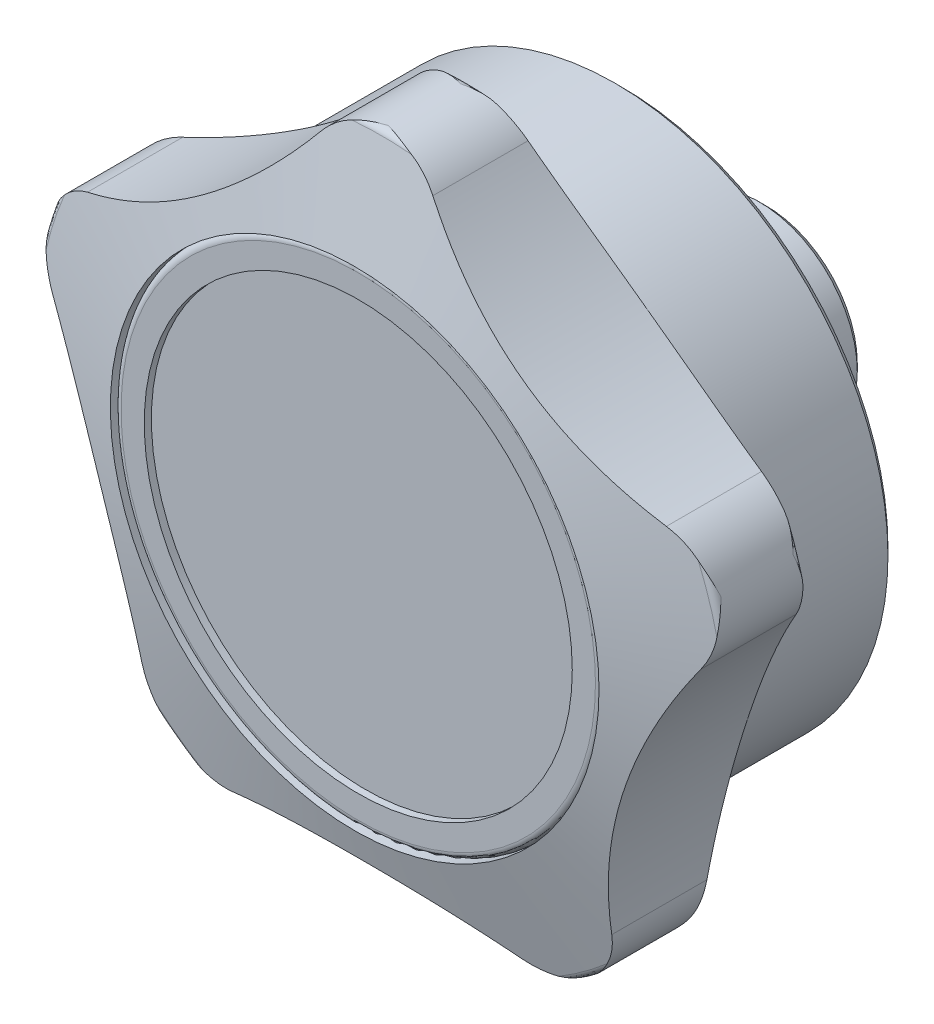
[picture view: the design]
ISO-10303-21;
HEADER;
FILE_DESCRIPTION(('STEP AP214'),'2;1');
FILE_NAME('part.step','',(''),(''),'','','');
FILE_SCHEMA(('AUTOMOTIVE_DESIGN { 1 0 10303 214 1 1 1 1 }'));
ENDSEC;
DATA;
#1=APPLICATION_CONTEXT('core data for automotive mechanical design processes');
#2=APPLICATION_PROTOCOL_DEFINITION('international standard','automotive_design',2000,#1);
#3=PRODUCT_CONTEXT('',#1,'mechanical');
#4=PRODUCT('Part','Part','',(#3));
#5=PRODUCT_RELATED_PRODUCT_CATEGORY('part','',(#4));
#6=PRODUCT_DEFINITION_FORMATION('','',#4);
#7=PRODUCT_DEFINITION_CONTEXT('part definition',#1,'design');
#8=PRODUCT_DEFINITION('design','',#6,#7);
#9=PRODUCT_DEFINITION_SHAPE('','',#8);
#10=(LENGTH_UNIT() NAMED_UNIT(*) SI_UNIT(.MILLI.,.METRE.));
#11=(NAMED_UNIT(*) PLANE_ANGLE_UNIT() SI_UNIT($,.RADIAN.));
#12=(NAMED_UNIT(*) SI_UNIT($,.STERADIAN.) SOLID_ANGLE_UNIT());
#13=UNCERTAINTY_MEASURE_WITH_UNIT(LENGTH_MEASURE(1.E-05),#10,'distance_accuracy_value','');
#14=(GEOMETRIC_REPRESENTATION_CONTEXT(3) GLOBAL_UNCERTAINTY_ASSIGNED_CONTEXT((#13)) GLOBAL_UNIT_ASSIGNED_CONTEXT((#10,
#11,#12)) REPRESENTATION_CONTEXT('',''));
#15=CARTESIAN_POINT('',(0.,0.,0.));
#16=DIRECTION('',(0.,0.,1.));
#17=DIRECTION('',(1.,0.,0.));
#18=AXIS2_PLACEMENT_3D('',#15,#16,#17);
#19=CARTESIAN_POINT('',(0.,0.,56.5000000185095));
#20=DIRECTION('',(0.,0.,1.));
#21=DIRECTION('',(1.,0.,0.));
#22=AXIS2_PLACEMENT_3D('',#19,#20,#21);
#23=TOROIDAL_SURFACE('',#22,33.2501924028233,1.);
#24=CARTESIAN_POINT('',(0.,0.,56.5196155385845));
#25=DIRECTION('',(0.,0.,1.));
#26=DIRECTION('',(1.,0.,0.));
#27=AXIS2_PLACEMENT_3D('',#24,#25,#26);
#28=CIRCLE('',#27,34.25);
#29=CARTESIAN_POINT('',(34.25,0.,56.5196155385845));
#30=VERTEX_POINT('',#29);
#31=EDGE_CURVE('E9',#30,#30,#28,.T.);
#32=ORIENTED_EDGE('',*,*,#31,.T.);
#33=EDGE_LOOP('',(#32));
#34=FACE_BOUND('',#33,.T.);
#35=CARTESIAN_POINT('',(0.,0.,57.5));
#36=DIRECTION('',(0.,0.,1.));
#37=DIRECTION('',(1.,0.,0.));
#38=AXIS2_PLACEMENT_3D('',#35,#36,#37);
#39=CIRCLE('',#38,33.25);
#40=CARTESIAN_POINT('',(33.25,0.,57.5));
#41=VERTEX_POINT('',#40);
#42=EDGE_CURVE('E23',#41,#41,#39,.T.);
#43=ORIENTED_EDGE('',*,*,#42,.F.);
#44=EDGE_LOOP('',(#43));
#45=FACE_BOUND('',#44,.T.);
#46=ADVANCED_FACE('F14',(#34,#45),#23,.T.);
#47=CARTESIAN_POINT('',(0.,-33.25,57.5));
#48=DIRECTION('',(0.,0.,-1.));
#49=DIRECTION('',(-1.,0.,0.));
#50=AXIS2_PLACEMENT_3D('',#47,#48,#49);
#51=PLANE('',#50);
#52=CARTESIAN_POINT('',(0.,0.,57.5));
#53=DIRECTION('',(0.,0.,1.));
#54=DIRECTION('',(1.,0.,0.));
#55=AXIS2_PLACEMENT_3D('',#52,#53,#54);
#56=CIRCLE('',#55,30.);
#57=CARTESIAN_POINT('',(30.,0.,57.5));
#58=VERTEX_POINT('',#57);
#59=EDGE_CURVE('E922',#58,#58,#56,.T.);
#60=ORIENTED_EDGE('',*,*,#59,.F.);
#61=EDGE_LOOP('',(#60));
#62=FACE_BOUND('',#61,.T.);
#63=ORIENTED_EDGE('',*,*,#42,.T.);
#64=EDGE_LOOP('',(#63));
#65=FACE_BOUND('',#64,.T.);
#66=ADVANCED_FACE('F856',(#62,#65),#51,.F.);
#67=CARTESIAN_POINT('',(0.,0.,56.5));
#68=DIRECTION('',(0.,0.,1.));
#69=DIRECTION('',(1.,0.,0.));
#70=AXIS2_PLACEMENT_3D('',#67,#68,#69);
#71=CYLINDRICAL_SURFACE('',#70,30.);
#72=CARTESIAN_POINT('',(0.,0.,56.5));
#73=DIRECTION('',(0.,0.,1.));
#74=DIRECTION('',(1.,0.,0.));
#75=AXIS2_PLACEMENT_3D('',#72,#73,#74);
#76=CIRCLE('',#75,30.);
#77=CARTESIAN_POINT('',(30.,0.,56.5));
#78=VERTEX_POINT('',#77);
#79=EDGE_CURVE('E924',#78,#78,#76,.T.);
#80=ORIENTED_EDGE('',*,*,#79,.F.);
#81=EDGE_LOOP('',(#80));
#82=FACE_BOUND('',#81,.T.);
#83=ORIENTED_EDGE('',*,*,#59,.T.);
#84=EDGE_LOOP('',(#83));
#85=FACE_BOUND('',#84,.T.);
#86=ADVANCED_FACE('F862',(#82,#85),#71,.F.);
#87=CARTESIAN_POINT('',(0.,0.,56.5));
#88=DIRECTION('',(0.,0.,1.));
#89=DIRECTION('',(1.,0.,0.));
#90=AXIS2_PLACEMENT_3D('',#87,#88,#89);
#91=PLANE('',#90);
#92=ORIENTED_EDGE('',*,*,#79,.T.);
#93=EDGE_LOOP('',(#92));
#94=FACE_BOUND('',#93,.T.);
#95=ADVANCED_FACE('F865',(#94),#91,.T.);
#96=CARTESIAN_POINT('',(0.,6.,8.0095));
#97=DIRECTION('',(0.,1.,0.));
#98=DIRECTION('',(-1.,0.,0.));
#99=AXIS2_PLACEMENT_3D('',#96,#97,#98);
#100=PLANE('',#99);
#101=CARTESIAN_POINT('',(0.,6.,6.));
#102=DIRECTION('',(0.,-1.,0.));
#103=DIRECTION('',(1.,0.,0.));
#104=AXIS2_PLACEMENT_3D('',#101,#102,#103);
#105=CIRCLE('',#104,2.0095);
#106=CARTESIAN_POINT('',(2.0095,6.,6.));
#107=VERTEX_POINT('',#106);
#108=EDGE_CURVE('E230',#107,#107,#105,.T.);
#109=ORIENTED_EDGE('',*,*,#108,.T.);
#110=EDGE_LOOP('',(#109));
#111=FACE_BOUND('',#110,.T.);
#112=ADVANCED_FACE('F852',(#111),#100,.F.);
#113=CARTESIAN_POINT('',(0.,6.4905,6.));
#114=DIRECTION('',(0.,1.,0.));
#115=DIRECTION('',(-1.,0.,0.));
#116=AXIS2_PLACEMENT_3D('',#113,#114,#115);
#117=CONICAL_SURFACE('',#116,2.5,0.785398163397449);
#118=ORIENTED_EDGE('',*,*,#108,.F.);
#119=EDGE_LOOP('',(#118));
#120=FACE_BOUND('',#119,.T.);
#121=CARTESIAN_POINT('',(0.,6.4905,6.));
#122=DIRECTION('',(0.,-1.,0.));
#123=DIRECTION('',(1.,0.,0.));
#124=AXIS2_PLACEMENT_3D('',#121,#122,#123);
#125=CIRCLE('',#124,2.5);
#126=CARTESIAN_POINT('',(2.5,6.4905,6.));
#127=VERTEX_POINT('',#126);
#128=EDGE_CURVE('E279',#127,#127,#125,.T.);
#129=ORIENTED_EDGE('',*,*,#128,.T.);
#130=EDGE_LOOP('',(#129));
#131=FACE_BOUND('',#130,.T.);
#132=ADVANCED_FACE('F872',(#120,#131),#117,.T.);
#133=CARTESIAN_POINT('',(0.,0.,22.));
#134=DIRECTION('',(0.,0.,1.));
#135=DIRECTION('',(1.,0.,0.));
#136=AXIS2_PLACEMENT_3D('',#133,#134,#135);
#137=PLANE('',#136);
#138=CARTESIAN_POINT('',(0.,0.,22.));
#139=DIRECTION('',(0.,0.,1.));
#140=DIRECTION('',(1.,0.,0.));
#141=AXIS2_PLACEMENT_3D('',#138,#139,#140);
#142=CIRCLE('',#141,6.);
#143=CARTESIAN_POINT('',(6.,0.,22.));
#144=VERTEX_POINT('',#143);
#145=EDGE_CURVE('E251',#144,#144,#142,.T.);
#146=ORIENTED_EDGE('',*,*,#145,.F.);
#147=EDGE_LOOP('',(#146));
#148=FACE_BOUND('',#147,.T.);
#149=ADVANCED_FACE('F869',(#148),#137,.F.);
#150=CARTESIAN_POINT('',(0.,5.,6.));
#151=DIRECTION('',(0.,-1.,0.));
#152=DIRECTION('',(1.,0.,0.));
#153=AXIS2_PLACEMENT_3D('',#150,#151,#152);
#154=CYLINDRICAL_SURFACE('',#153,2.5);
#155=CARTESIAN_POINT('',(2.5,5.45435605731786,6.));
#156=CARTESIAN_POINT('',(2.49999850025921,5.45435734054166,5.9332918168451));
#157=CARTESIAN_POINT('',(2.49732449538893,5.4555854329,5.86656520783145));
#158=CARTESIAN_POINT('',(2.48666416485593,5.460451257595,5.73361352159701));
#159=CARTESIAN_POINT('',(2.47867468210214,5.46409042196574,5.6673887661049));
#160=CARTESIAN_POINT('',(2.44679265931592,5.47848490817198,5.46994813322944));
#161=CARTESIAN_POINT('',(2.41498683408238,5.49271671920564,5.34016318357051));
#162=CARTESIAN_POINT('',(2.33180001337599,5.52853615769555,5.08884523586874));
#163=CARTESIAN_POINT('',(2.28049881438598,5.55009376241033,4.96728094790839));
#164=CARTESIAN_POINT('',(2.16001268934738,5.59808356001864,4.73448982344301));
#165=CARTESIAN_POINT('',(2.09083199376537,5.62451459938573,4.62326055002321));
#166=CARTESIAN_POINT('',(1.93194778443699,5.6811150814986,4.40734601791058));
#167=CARTESIAN_POINT('',(1.84130648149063,5.71141131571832,4.30338420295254));
#168=CARTESIAN_POINT('',(1.64404334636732,5.77128595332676,4.11160023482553));
#169=CARTESIAN_POINT('',(1.53741538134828,5.80086407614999,4.02378430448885));
#170=CARTESIAN_POINT('',(1.30552678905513,5.8575107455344,3.86310074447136));
#171=CARTESIAN_POINT('',(1.17965858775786,5.88441479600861,3.79104669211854));
#172=CARTESIAN_POINT('',(0.916264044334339,5.93113040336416,3.66944801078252));
#173=CARTESIAN_POINT('',(0.778742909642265,5.95094510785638,3.61989338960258));
#174=CARTESIAN_POINT('',(0.503536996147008,5.98035041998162,3.54732106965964));
#175=CARTESIAN_POINT('',(0.36623315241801,5.99041942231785,3.52305660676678));
#176=CARTESIAN_POINT('',(0.0891583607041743,6.00093657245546,3.49772472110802));
#177=CARTESIAN_POINT('',(-0.0506115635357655,6.00138862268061,3.49664788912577));
#178=CARTESIAN_POINT('',(-0.319585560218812,5.99290258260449,3.51706856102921));
#179=CARTESIAN_POINT('',(-0.448914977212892,5.98453429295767,3.53719620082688));
#180=CARTESIAN_POINT('',(-0.702165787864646,5.96013033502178,3.59710620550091));
#181=CARTESIAN_POINT('',(-0.826086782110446,5.94409410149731,3.63689001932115));
#182=CARTESIAN_POINT('',(-1.06727623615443,5.90559704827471,3.73545608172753));
#183=CARTESIAN_POINT('',(-1.18441435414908,5.88304194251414,3.79451892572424));
#184=CARTESIAN_POINT('',(-1.40742353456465,5.83371427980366,3.9296915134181));
#185=CARTESIAN_POINT('',(-1.51329059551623,5.80694023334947,4.00580728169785));
#186=CARTESIAN_POINT('',(-1.7186818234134,5.74963397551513,4.1791648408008));
#187=CARTESIAN_POINT('',(-1.81723287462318,5.71896988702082,4.27751758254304));
#188=CARTESIAN_POINT('',(-1.99686282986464,5.65875721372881,4.48942288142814));
#189=CARTESIAN_POINT('',(-2.0779349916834,5.62920906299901,4.60298127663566));
#190=CARTESIAN_POINT('',(-2.22280378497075,5.57363224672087,4.84679007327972));
#191=CARTESIAN_POINT('',(-2.28594506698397,5.54775116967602,4.9774664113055));
#192=CARTESIAN_POINT('',(-2.38892864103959,5.50419688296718,5.24896208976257));
#193=CARTESIAN_POINT('',(-2.42878759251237,5.48651780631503,5.38977409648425));
#194=CARTESIAN_POINT('',(-2.48160050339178,5.46282425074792,5.667793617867));
#195=CARTESIAN_POINT('',(-2.49613229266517,5.45612738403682,5.80464224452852));
#196=CARTESIAN_POINT('',(-2.50251261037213,5.45320573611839,6.07895696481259));
#197=CARTESIAN_POINT('',(-2.49436898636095,5.45697733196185,6.21642282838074));
#198=CARTESIAN_POINT('',(-2.45706955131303,5.47386262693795,6.4787967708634));
#199=CARTESIAN_POINT('',(-2.42929237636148,5.48636276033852,6.60394537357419));
#200=CARTESIAN_POINT('',(-2.355341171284,5.51851260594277,6.84770259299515));
#201=CARTESIAN_POINT('',(-2.30916284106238,5.53816398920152,6.96630967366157));
#202=CARTESIAN_POINT('',(-2.19755041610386,5.58341595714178,7.19923062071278));
#203=CARTESIAN_POINT('',(-2.13138366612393,5.60923324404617,7.31314994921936));
#204=CARTESIAN_POINT('',(-1.98240156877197,5.66360007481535,7.52881610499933));
#205=CARTESIAN_POINT('',(-1.89957901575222,5.69215079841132,7.63055763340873));
#206=CARTESIAN_POINT('',(-1.71168891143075,5.75157239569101,7.82760026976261));
#207=CARTESIAN_POINT('',(-1.6053593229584,5.78244293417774,7.92170279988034));
#208=CARTESIAN_POINT('',(-1.37770302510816,5.84086722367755,8.09094458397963));
#209=CARTESIAN_POINT('',(-1.25637521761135,5.86842073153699,8.16608244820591));
#210=CARTESIAN_POINT('',(-1.00130936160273,5.91728503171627,8.29517975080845));
#211=CARTESIAN_POINT('',(-0.867540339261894,5.93857966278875,8.34908448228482));
#212=CARTESIAN_POINT('',(-0.591717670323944,5.9723634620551,8.43323358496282));
#213=CARTESIAN_POINT('',(-0.449669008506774,5.98485787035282,8.46349203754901));
#214=CARTESIAN_POINT('',(-0.172033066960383,5.9990306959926,8.49771625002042));
#215=CARTESIAN_POINT('',(-0.0366881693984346,6.0014040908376,8.50337199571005));
#216=CARTESIAN_POINT('',(0.232973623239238,5.99699046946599,8.49277372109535));
#217=CARTESIAN_POINT('',(0.367290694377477,5.99020505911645,8.47652354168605));
#218=CARTESIAN_POINT('',(0.626172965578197,5.9686013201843,8.4237878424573));
#219=CARTESIAN_POINT('',(0.750915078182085,5.95407648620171,8.38804059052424));
#220=CARTESIAN_POINT('',(0.992584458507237,5.91858999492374,8.29813155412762));
#221=CARTESIAN_POINT('',(1.1095102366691,5.89762711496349,8.24396627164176));
#222=CARTESIAN_POINT('',(1.33804914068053,5.85011651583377,8.11602075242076));
#223=CARTESIAN_POINT('',(1.44918335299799,5.82335921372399,8.04146467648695));
#224=CARTESIAN_POINT('',(1.65783731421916,5.7674312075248,7.87598635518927));
#225=CARTESIAN_POINT('',(1.75535198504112,5.73825960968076,7.78505803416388));
#226=CARTESIAN_POINT('',(1.9408997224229,5.67829702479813,7.58210746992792));
#227=CARTESIAN_POINT('',(2.02783607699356,5.64753091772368,7.46907088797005));
#228=CARTESIAN_POINT('',(2.18166607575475,5.5899105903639,7.22909360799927));
#229=CARTESIAN_POINT('',(2.24854851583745,5.56305856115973,7.10214519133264));
#230=CARTESIAN_POINT('',(2.35965744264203,5.51685287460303,6.83807106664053));
#231=CARTESIAN_POINT('',(2.40400437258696,5.49745949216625,6.70100404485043));
#232=CARTESIAN_POINT('',(2.45239925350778,5.47594959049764,6.49083623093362));
#233=CARTESIAN_POINT('',(2.46550603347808,5.47004503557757,6.42008940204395));
#234=CARTESIAN_POINT('',(2.48558130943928,5.46095373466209,6.27757394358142));
#235=CARTESIAN_POINT('',(2.49255414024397,5.45776506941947,6.20580607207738));
#236=CARTESIAN_POINT('',(2.49880479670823,5.45490391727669,6.08928839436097));
#237=CARTESIAN_POINT('',(2.50000100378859,5.45435519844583,6.0446483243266));
#238=CARTESIAN_POINT('',(2.5,5.45435605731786,6.));
#239=B_SPLINE_CURVE_WITH_KNOTS('',3,(#155,#156,#157,#158,#159,#160,#161,#162,#163,#164,#165,
#166,#167,#168,#169,#170,#171,#172,#173,#174,#175,#176,#177,#178,#179,#180,#181,#182,#183,#184,
#185,#186,#187,#188,#189,#190,#191,#192,#193,#194,#195,#196,#197,#198,#199,#200,#201,#202,#203,
#204,#205,#206,#207,#208,#209,#210,#211,#212,#213,#214,#215,#216,#217,#218,#219,#220,#221,#222,
#223,#224,#225,#226,#227,#228,#229,#230,#231,#232,#233,#234,#235,#236,#237,#238),.UNSPECIFIED.,
.T.,.F.,(4,2,2,2,2,2,2,2,2,2,2,2,2,2,2,2,2,2,2,2,2,2,2,2,2,2,2,2,2,2,2,2,2,2,2,2,2,2,2,2,2,4),
(0.,0.200084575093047,0.400288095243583,0.801278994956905,1.20064597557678,1.59991854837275,
2.02172149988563,2.44368668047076,2.88395420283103,3.32402600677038,3.7411967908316,
4.15819828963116,4.54982147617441,4.94147353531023,5.33910096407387,5.73686909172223,
6.16267530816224,6.58864548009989,7.02861558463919,7.46827048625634,7.87940023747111,
8.29038772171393,8.6750626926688,9.05982760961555,9.46088720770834,9.86212068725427,
10.2960179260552,10.7299469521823,11.1649867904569,11.5997673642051,12.004157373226,
12.4084764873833,12.7984529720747,13.1885035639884,13.5961819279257,14.0040118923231,
14.4395932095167,14.8754174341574,15.3088871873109,15.5252058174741,15.7413714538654,
15.8752896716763),.UNSPECIFIED.);
#240=CARTESIAN_POINT('',(2.5,5.45435605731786,6.));
#241=VERTEX_POINT('',#240);
#242=EDGE_CURVE('E288',#241,#241,#239,.T.);
#243=ORIENTED_EDGE('',*,*,#242,.F.);
#244=EDGE_LOOP('',(#243));
#245=FACE_BOUND('',#244,.T.);
#246=ORIENTED_EDGE('',*,*,#128,.F.);
#247=EDGE_LOOP('',(#246));
#248=FACE_BOUND('',#247,.T.);
#249=ADVANCED_FACE('F309',(#245,#248),#154,.F.);
#250=CARTESIAN_POINT('',(0.,11.75,0.));
#251=DIRECTION('',(0.,1.,0.));
#252=DIRECTION('',(-1.,0.,0.));
#253=AXIS2_PLACEMENT_3D('',#250,#251,#252);
#254=PLANE('',#253);
#255=DIRECTION('',(-1.,0.,0.));
#256=VECTOR('',#255,1.);
#257=CARTESIAN_POINT('',(0.577350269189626,11.75,5.));
#258=LINE('',#257,#256);
#259=CARTESIAN_POINT('',(0.577350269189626,11.75,5.));
#260=VERTEX_POINT('',#259);
#261=CARTESIAN_POINT('',(-0.577350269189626,11.75,5.));
#262=VERTEX_POINT('',#261);
#263=EDGE_CURVE('E224',#260,#262,#258,.T.);
#264=ORIENTED_EDGE('',*,*,#263,.T.);
#265=DIRECTION('',(-0.5,0.,0.866025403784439));
#266=VECTOR('',#265,1.);
#267=CARTESIAN_POINT('',(-0.577350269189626,11.75,5.));
#268=LINE('',#267,#266);
#269=CARTESIAN_POINT('',(-1.15470053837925,11.75,6.));
#270=VERTEX_POINT('',#269);
#271=EDGE_CURVE('E234',#262,#270,#268,.T.);
#272=ORIENTED_EDGE('',*,*,#271,.T.);
#273=DIRECTION('',(0.5,0.,0.866025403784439));
#274=VECTOR('',#273,1.);
#275=CARTESIAN_POINT('',(-1.15470053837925,11.75,6.));
#276=LINE('',#275,#274);
#277=CARTESIAN_POINT('',(-0.577350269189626,11.75,7.));
#278=VERTEX_POINT('',#277);
#279=EDGE_CURVE('E239',#270,#278,#276,.T.);
#280=ORIENTED_EDGE('',*,*,#279,.T.);
#281=DIRECTION('',(1.,0.,0.));
#282=VECTOR('',#281,1.);
#283=CARTESIAN_POINT('',(-0.577350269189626,11.75,7.));
#284=LINE('',#283,#282);
#285=CARTESIAN_POINT('',(0.577350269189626,11.75,7.));
#286=VERTEX_POINT('',#285);
#287=EDGE_CURVE('E254',#278,#286,#284,.T.);
#288=ORIENTED_EDGE('',*,*,#287,.T.);
#289=DIRECTION('',(0.5,0.,-0.866025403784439));
#290=VECTOR('',#289,1.);
#291=CARTESIAN_POINT('',(0.577350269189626,11.75,7.));
#292=LINE('',#291,#290);
#293=CARTESIAN_POINT('',(1.15470053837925,11.75,6.));
#294=VERTEX_POINT('',#293);
#295=EDGE_CURVE('E257',#286,#294,#292,.T.);
#296=ORIENTED_EDGE('',*,*,#295,.T.);
#297=DIRECTION('',(-0.5,0.,-0.866025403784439));
#298=VECTOR('',#297,1.);
#299=CARTESIAN_POINT('',(1.15470053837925,11.75,6.));
#300=LINE('',#299,#298);
#301=EDGE_CURVE('E245',#294,#260,#300,.T.);
#302=ORIENTED_EDGE('',*,*,#301,.T.);
#303=EDGE_LOOP('',(#264,#272,#280,#288,#296,#302));
#304=FACE_BOUND('',#303,.T.);
#305=ADVANCED_FACE('F242',(#304),#254,.T.);
#306=CARTESIAN_POINT('',(0.,0.,58.));
#307=DIRECTION('',(0.,0.,1.));
#308=DIRECTION('',(1.,0.,0.));
#309=AXIS2_PLACEMENT_3D('',#306,#307,#308);
#310=CYLINDRICAL_SURFACE('',#309,6.);
#311=CARTESIAN_POINT('',(0.,0.,0.));
#312=DIRECTION('',(0.,0.,1.));
#313=DIRECTION('',(1.,0.,0.));
#314=AXIS2_PLACEMENT_3D('',#311,#312,#313);
#315=CIRCLE('',#314,6.);
#316=CARTESIAN_POINT('',(6.,0.,0.));
#317=VERTEX_POINT('',#316);
#318=EDGE_CURVE('E653',#317,#317,#315,.T.);
#319=ORIENTED_EDGE('',*,*,#318,.F.);
#320=EDGE_LOOP('',(#319));
#321=FACE_BOUND('',#320,.T.);
#322=ORIENTED_EDGE('',*,*,#242,.T.);
#323=EDGE_LOOP('',(#322));
#324=FACE_BOUND('',#323,.T.);
#325=ORIENTED_EDGE('',*,*,#145,.T.);
#326=EDGE_LOOP('',(#325));
#327=FACE_BOUND('',#326,.T.);
#328=ADVANCED_FACE('F298',(#321,#324,#327),#310,.F.);
#329=CARTESIAN_POINT('',(-0.577350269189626,11.75,7.));
#330=DIRECTION('',(0.,0.,1.));
#331=DIRECTION('',(1.,0.,0.));
#332=AXIS2_PLACEMENT_3D('',#329,#330,#331);
#333=PLANE('',#332);
#334=DIRECTION('',(0.,1.,0.));
#335=VECTOR('',#334,1.);
#336=CARTESIAN_POINT('',(-0.577350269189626,11.75,7.));
#337=LINE('',#336,#335);
#338=CARTESIAN_POINT('',(-0.577350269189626,13.75,7.));
#339=VERTEX_POINT('',#338);
#340=EDGE_CURVE('E273',#278,#339,#337,.T.);
#341=ORIENTED_EDGE('',*,*,#340,.T.);
#342=DIRECTION('',(-1.,0.,0.));
#343=VECTOR('',#342,1.);
#344=CARTESIAN_POINT('',(0.,13.75,7.));
#345=LINE('',#344,#343);
#346=CARTESIAN_POINT('',(0.577350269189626,13.75,7.));
#347=VERTEX_POINT('',#346);
#348=EDGE_CURVE('E18',#347,#339,#345,.T.);
#349=ORIENTED_EDGE('',*,*,#348,.F.);
#350=DIRECTION('',(0.,1.,0.));
#351=VECTOR('',#350,1.);
#352=CARTESIAN_POINT('',(0.577350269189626,11.75,7.));
#353=LINE('',#352,#351);
#354=EDGE_CURVE('E271',#286,#347,#353,.T.);
#355=ORIENTED_EDGE('',*,*,#354,.F.);
#356=ORIENTED_EDGE('',*,*,#287,.F.);
#357=EDGE_LOOP('',(#341,#349,#355,#356));
#358=FACE_BOUND('',#357,.T.);
#359=ADVANCED_FACE('F883',(#358),#333,.F.);
#360=CARTESIAN_POINT('',(0.577350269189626,11.75,7.));
#361=DIRECTION('',(0.866025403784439,0.,0.5));
#362=DIRECTION('',(0.5,0.,-0.866025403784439));
#363=AXIS2_PLACEMENT_3D('',#360,#361,#362);
#364=PLANE('',#363);
#365=DIRECTION('',(0.5,0.,-0.866025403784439));
#366=VECTOR('',#365,1.);
#367=CARTESIAN_POINT('',(0.577350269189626,13.75,7.));
#368=LINE('',#367,#366);
#369=CARTESIAN_POINT('',(1.15470053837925,13.75,6.));
#370=VERTEX_POINT('',#369);
#371=EDGE_CURVE('E31',#347,#370,#368,.T.);
#372=ORIENTED_EDGE('',*,*,#371,.T.);
#373=DIRECTION('',(0.,1.,0.));
#374=VECTOR('',#373,1.);
#375=CARTESIAN_POINT('',(1.15470053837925,11.75,6.));
#376=LINE('',#375,#374);
#377=EDGE_CURVE('E269',#294,#370,#376,.T.);
#378=ORIENTED_EDGE('',*,*,#377,.F.);
#379=ORIENTED_EDGE('',*,*,#295,.F.);
#380=ORIENTED_EDGE('',*,*,#354,.T.);
#381=EDGE_LOOP('',(#372,#378,#379,#380));
#382=FACE_BOUND('',#381,.T.);
#383=ADVANCED_FACE('F879',(#382),#364,.F.);
#384=CARTESIAN_POINT('',(1.15470053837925,11.75,6.));
#385=DIRECTION('',(0.866025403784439,0.,-0.5));
#386=DIRECTION('',(-0.5,0.,-0.866025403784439));
#387=AXIS2_PLACEMENT_3D('',#384,#385,#386);
#388=PLANE('',#387);
#389=DIRECTION('',(-0.5,0.,-0.866025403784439));
#390=VECTOR('',#389,1.);
#391=CARTESIAN_POINT('',(1.15470053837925,13.75,6.));
#392=LINE('',#391,#390);
#393=CARTESIAN_POINT('',(0.577350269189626,13.75,5.));
#394=VERTEX_POINT('',#393);
#395=EDGE_CURVE('E246',#370,#394,#392,.T.);
#396=ORIENTED_EDGE('',*,*,#395,.T.);
#397=DIRECTION('',(0.,1.,0.));
#398=VECTOR('',#397,1.);
#399=CARTESIAN_POINT('',(0.577350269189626,11.75,5.));
#400=LINE('',#399,#398);
#401=EDGE_CURVE('E260',#260,#394,#400,.T.);
#402=ORIENTED_EDGE('',*,*,#401,.F.);
#403=ORIENTED_EDGE('',*,*,#301,.F.);
#404=ORIENTED_EDGE('',*,*,#377,.T.);
#405=EDGE_LOOP('',(#396,#402,#403,#404));
#406=FACE_BOUND('',#405,.T.);
#407=ADVANCED_FACE('F876',(#406),#388,.F.);
#408=CARTESIAN_POINT('',(0.577350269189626,11.75,5.));
#409=DIRECTION('',(0.,0.,-1.));
#410=DIRECTION('',(-1.,0.,0.));
#411=AXIS2_PLACEMENT_3D('',#408,#409,#410);
#412=PLANE('',#411);
#413=DIRECTION('',(-1.,0.,0.));
#414=VECTOR('',#413,1.);
#415=CARTESIAN_POINT('',(0.577350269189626,13.75,5.));
#416=LINE('',#415,#414);
#417=CARTESIAN_POINT('',(-0.577350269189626,13.75,5.));
#418=VERTEX_POINT('',#417);
#419=EDGE_CURVE('E226',#394,#418,#416,.T.);
#420=ORIENTED_EDGE('',*,*,#419,.T.);
#421=DIRECTION('',(0.,1.,0.));
#422=VECTOR('',#421,1.);
#423=CARTESIAN_POINT('',(-0.577350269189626,11.75,5.));
#424=LINE('',#423,#422);
#425=EDGE_CURVE('E220',#262,#418,#424,.T.);
#426=ORIENTED_EDGE('',*,*,#425,.F.);
#427=ORIENTED_EDGE('',*,*,#263,.F.);
#428=ORIENTED_EDGE('',*,*,#401,.T.);
#429=EDGE_LOOP('',(#420,#426,#427,#428));
#430=FACE_BOUND('',#429,.T.);
#431=ADVANCED_FACE('F222',(#430),#412,.F.);
#432=CARTESIAN_POINT('',(-0.577350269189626,11.75,5.));
#433=DIRECTION('',(-0.866025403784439,0.,-0.5));
#434=DIRECTION('',(-0.5,0.,0.866025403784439));
#435=AXIS2_PLACEMENT_3D('',#432,#433,#434);
#436=PLANE('',#435);
#437=DIRECTION('',(-0.5,0.,0.866025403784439));
#438=VECTOR('',#437,1.);
#439=CARTESIAN_POINT('',(-0.577350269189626,13.75,5.));
#440=LINE('',#439,#438);
#441=CARTESIAN_POINT('',(-1.15470053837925,13.75,6.));
#442=VERTEX_POINT('',#441);
#443=EDGE_CURVE('E262',#418,#442,#440,.T.);
#444=ORIENTED_EDGE('',*,*,#443,.T.);
#445=DIRECTION('',(0.,1.,0.));
#446=VECTOR('',#445,1.);
#447=CARTESIAN_POINT('',(-1.15470053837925,11.75,6.));
#448=LINE('',#447,#446);
#449=EDGE_CURVE('E231',#270,#442,#448,.T.);
#450=ORIENTED_EDGE('',*,*,#449,.F.);
#451=ORIENTED_EDGE('',*,*,#271,.F.);
#452=ORIENTED_EDGE('',*,*,#425,.T.);
#453=EDGE_LOOP('',(#444,#450,#451,#452));
#454=FACE_BOUND('',#453,.T.);
#455=ADVANCED_FACE('F235',(#454),#436,.F.);
#456=CARTESIAN_POINT('',(-1.15470053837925,11.75,6.));
#457=DIRECTION('',(-0.866025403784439,0.,0.5));
#458=DIRECTION('',(0.5,0.,0.866025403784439));
#459=AXIS2_PLACEMENT_3D('',#456,#457,#458);
#460=PLANE('',#459);
#461=DIRECTION('',(0.5,0.,0.866025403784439));
#462=VECTOR('',#461,1.);
#463=CARTESIAN_POINT('',(-1.15470053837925,13.75,6.));
#464=LINE('',#463,#462);
#465=EDGE_CURVE('E264',#442,#339,#464,.T.);
#466=ORIENTED_EDGE('',*,*,#465,.T.);
#467=ORIENTED_EDGE('',*,*,#340,.F.);
#468=ORIENTED_EDGE('',*,*,#279,.F.);
#469=ORIENTED_EDGE('',*,*,#449,.T.);
#470=EDGE_LOOP('',(#466,#467,#468,#469));
#471=FACE_BOUND('',#470,.T.);
#472=ADVANCED_FACE('F887',(#471),#460,.F.);
#473=CARTESIAN_POINT('',(0.,11.,0.));
#474=DIRECTION('',(0.,0.,-1.));
#475=DIRECTION('',(-1.,0.,0.));
#476=AXIS2_PLACEMENT_3D('',#473,#474,#475);
#477=PLANE('',#476);
#478=ORIENTED_EDGE('',*,*,#318,.T.);
#479=EDGE_LOOP('',(#478));
#480=FACE_BOUND('',#479,.T.);
#481=CARTESIAN_POINT('',(0.,0.,0.));
#482=DIRECTION('',(0.,0.,1.));
#483=DIRECTION('',(1.,0.,0.));
#484=AXIS2_PLACEMENT_3D('',#481,#482,#483);
#485=CIRCLE('',#484,11.);
#486=CARTESIAN_POINT('',(11.,0.,0.));
#487=VERTEX_POINT('',#486);
#488=EDGE_CURVE('E614',#487,#487,#485,.T.);
#489=ORIENTED_EDGE('',*,*,#488,.F.);
#490=EDGE_LOOP('',(#489));
#491=FACE_BOUND('',#490,.T.);
#492=ADVANCED_FACE('F16',(#480,#491),#477,.T.);
#493=CARTESIAN_POINT('',(0.,13.75,6.));
#494=DIRECTION('',(0.,-1.,0.));
#495=DIRECTION('',(1.,0.,0.));
#496=AXIS2_PLACEMENT_3D('',#493,#494,#495);
#497=PLANE('',#496);
#498=CARTESIAN_POINT('',(0.,13.75,6.));
#499=DIRECTION('',(0.,-1.,0.));
#500=DIRECTION('',(1.,0.,0.));
#501=AXIS2_PLACEMENT_3D('',#498,#499,#500);
#502=CIRCLE('',#501,2.0095);
#503=CARTESIAN_POINT('',(2.0095,13.75,6.));
#504=VERTEX_POINT('',#503);
#505=EDGE_CURVE('E285',#504,#504,#502,.T.);
#506=ORIENTED_EDGE('',*,*,#505,.F.);
#507=EDGE_LOOP('',(#506));
#508=FACE_BOUND('',#507,.T.);
#509=ORIENTED_EDGE('',*,*,#465,.F.);
#510=ORIENTED_EDGE('',*,*,#443,.F.);
#511=ORIENTED_EDGE('',*,*,#419,.F.);
#512=ORIENTED_EDGE('',*,*,#395,.F.);
#513=ORIENTED_EDGE('',*,*,#371,.F.);
#514=ORIENTED_EDGE('',*,*,#348,.T.);
#515=EDGE_LOOP('',(#509,#510,#511,#512,#513,#514));
#516=FACE_BOUND('',#515,.T.);
#517=ADVANCED_FACE('F310',(#508,#516),#497,.F.);
#518=CARTESIAN_POINT('',(0.,0.,58.));
#519=DIRECTION('',(0.,0.,1.));
#520=DIRECTION('',(1.,0.,0.));
#521=AXIS2_PLACEMENT_3D('',#518,#519,#520);
#522=CYLINDRICAL_SURFACE('',#521,11.);
#523=ORIENTED_EDGE('',*,*,#488,.T.);
#524=EDGE_LOOP('',(#523));
#525=FACE_BOUND('',#524,.T.);
#526=CARTESIAN_POINT('',(0.,0.,0.3));
#527=DIRECTION('',(0.,0.,1.));
#528=DIRECTION('',(1.,0.,0.));
#529=AXIS2_PLACEMENT_3D('',#526,#527,#528);
#530=CIRCLE('',#529,11.);
#531=CARTESIAN_POINT('',(11.,0.,0.3));
#532=VERTEX_POINT('',#531);
#533=EDGE_CURVE('E617',#532,#532,#530,.T.);
#534=ORIENTED_EDGE('',*,*,#533,.F.);
#535=EDGE_LOOP('',(#534));
#536=FACE_BOUND('',#535,.T.);
#537=ADVANCED_FACE('F593',(#525,#536),#522,.T.);
#538=CARTESIAN_POINT('',(0.,13.75,6.));
#539=DIRECTION('',(0.,-1.,0.));
#540=DIRECTION('',(1.,0.,0.));
#541=AXIS2_PLACEMENT_3D('',#538,#539,#540);
#542=CONICAL_SURFACE('',#541,2.0095,0.785398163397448);
#543=CARTESIAN_POINT('',(0.,13.2595,6.));
#544=DIRECTION('',(0.,-1.,0.));
#545=DIRECTION('',(1.,0.,0.));
#546=AXIS2_PLACEMENT_3D('',#543,#544,#545);
#547=CIRCLE('',#546,2.5);
#548=CARTESIAN_POINT('',(2.5,13.2595,6.));
#549=VERTEX_POINT('',#548);
#550=EDGE_CURVE('E282',#549,#549,#547,.T.);
#551=ORIENTED_EDGE('',*,*,#550,.F.);
#552=EDGE_LOOP('',(#551));
#553=FACE_BOUND('',#552,.T.);
#554=ORIENTED_EDGE('',*,*,#505,.T.);
#555=EDGE_LOOP('',(#554));
#556=FACE_BOUND('',#555,.T.);
#557=ADVANCED_FACE('F895',(#553,#556),#542,.T.);
#558=CARTESIAN_POINT('',(0.,12.75,0.3));
#559=DIRECTION('',(0.,0.,-1.));
#560=DIRECTION('',(-1.,0.,0.));
#561=AXIS2_PLACEMENT_3D('',#558,#559,#560);
#562=PLANE('',#561);
#563=ORIENTED_EDGE('',*,*,#533,.T.);
#564=EDGE_LOOP('',(#563));
#565=FACE_BOUND('',#564,.T.);
#566=CARTESIAN_POINT('',(0.,0.,0.3));
#567=DIRECTION('',(0.,0.,1.));
#568=DIRECTION('',(1.,0.,0.));
#569=AXIS2_PLACEMENT_3D('',#566,#567,#568);
#570=CIRCLE('',#569,12.75);
#571=CARTESIAN_POINT('',(12.75,0.,0.3));
#572=VERTEX_POINT('',#571);
#573=EDGE_CURVE('E620',#572,#572,#570,.T.);
#574=ORIENTED_EDGE('',*,*,#573,.F.);
#575=EDGE_LOOP('',(#574));
#576=FACE_BOUND('',#575,.T.);
#577=ADVANCED_FACE('F307',(#565,#576),#562,.T.);
#578=ORIENTED_EDGE('',*,*,#550,.T.);
#579=EDGE_LOOP('',(#578));
#580=FACE_BOUND('',#579,.T.);
#581=CARTESIAN_POINT('',(0.,13.75,8.5));
#582=CARTESIAN_POINT('',(-0.139196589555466,13.7499975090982,8.49999460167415));
#583=CARTESIAN_POINT('',(-0.278464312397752,13.7478644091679,8.48833530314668));
#584=CARTESIAN_POINT('',(-0.553080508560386,13.7395605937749,8.44203316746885));
#585=CARTESIAN_POINT('',(-0.688425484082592,13.7333863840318,8.40737043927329));
#586=CARTESIAN_POINT('',(-0.951184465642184,13.7176915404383,8.31615358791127));
#587=CARTESIAN_POINT('',(-1.07860532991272,13.708173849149,8.2596187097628));
#588=CARTESIAN_POINT('',(-1.32214000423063,13.6868333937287,8.12631583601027));
#589=CARTESIAN_POINT('',(-1.43825483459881,13.6750108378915,8.04954966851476));
#590=CARTESIAN_POINT('',(-1.65720555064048,13.6502179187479,7.87704261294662));
#591=CARTESIAN_POINT('',(-1.75989528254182,13.6372371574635,7.78111769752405));
#592=CARTESIAN_POINT('',(-1.94781696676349,13.6116686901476,7.57341205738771));
#593=CARTESIAN_POINT('',(-2.03304770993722,13.5990810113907,7.46163023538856));
#594=CARTESIAN_POINT('',(-2.18423368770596,13.5756230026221,7.22435908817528));
#595=CARTESIAN_POINT('',(-2.25004141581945,13.5647660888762,7.09877433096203));
#596=CARTESIAN_POINT('',(-2.35956933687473,13.5461447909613,6.83810168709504));
#597=CARTESIAN_POINT('',(-2.40329131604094,13.5383801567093,6.70301456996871));
#598=CARTESIAN_POINT('',(-2.46693997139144,13.5269269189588,6.42873168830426));
#599=CARTESIAN_POINT('',(-2.48712083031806,13.5231948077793,6.28959676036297));
#600=CARTESIAN_POINT('',(-2.50390310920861,13.5200978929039,6.00986949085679));
#601=CARTESIAN_POINT('',(-2.50050651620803,13.5207327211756,5.86927727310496));
#602=CARTESIAN_POINT('',(-2.4704366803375,13.5262583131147,5.59246010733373));
#603=CARTESIAN_POINT('',(-2.4440514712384,13.5310964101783,5.45620266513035));
#604=CARTESIAN_POINT('',(-2.36920654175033,13.5444007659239,5.19008122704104));
#605=CARTESIAN_POINT('',(-2.32074593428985,13.552867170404,5.06021748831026));
#606=CARTESIAN_POINT('',(-2.20284122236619,13.5725297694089,4.80972151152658));
#607=CARTESIAN_POINT('',(-2.13327987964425,13.5837411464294,4.68914569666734));
#608=CARTESIAN_POINT('',(-1.97523129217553,13.6076202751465,4.46126907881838));
#609=CARTESIAN_POINT('',(-1.8867422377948,13.6202881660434,4.3539695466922));
#610=CARTESIAN_POINT('',(-1.6917924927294,13.6458830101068,4.15402625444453));
#611=CARTESIAN_POINT('',(-1.58508521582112,13.6588110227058,4.06162288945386));
#612=CARTESIAN_POINT('',(-1.35755567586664,13.6832968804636,3.89599358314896));
#613=CARTESIAN_POINT('',(-1.2367332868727,13.6948547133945,3.82276781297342));
#614=CARTESIAN_POINT('',(-0.984159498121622,13.7153192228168,3.69754076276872));
#615=CARTESIAN_POINT('',(-0.852395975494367,13.7242229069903,3.64556341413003));
#616=CARTESIAN_POINT('',(-0.581810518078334,13.738352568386,3.56454600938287));
#617=CARTESIAN_POINT('',(-0.442989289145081,13.7435789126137,3.53550366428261));
#618=CARTESIAN_POINT('',(-0.164298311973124,13.7497149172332,3.5015127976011));
#619=CARTESIAN_POINT('',(-0.0244700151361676,13.7506836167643,3.4962347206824));
#620=CARTESIAN_POINT('',(0.254071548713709,13.7483578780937,3.50903974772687));
#621=CARTESIAN_POINT('',(0.392784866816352,13.7450636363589,3.52712177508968));
#622=CARTESIAN_POINT('',(0.664121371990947,13.7346188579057,3.58585968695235));
#623=CARTESIAN_POINT('',(0.796781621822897,13.727496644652,3.62634983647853));
#624=CARTESIAN_POINT('',(1.05343089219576,13.7101911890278,3.72857603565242));
#625=CARTESIAN_POINT('',(1.17741935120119,13.7000077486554,3.79031345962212));
#626=CARTESIAN_POINT('',(1.41461905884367,13.6775622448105,3.93401829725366));
#627=CARTESIAN_POINT('',(1.5277055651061,13.6652797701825,4.01618835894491));
#628=CARTESIAN_POINT('',(1.73860267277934,13.6400536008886,4.19815047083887));
#629=CARTESIAN_POINT('',(1.83641193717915,13.6271098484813,4.29794406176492));
#630=CARTESIAN_POINT('',(2.01522172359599,13.6018254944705,4.51380860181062));
#631=CARTESIAN_POINT('',(2.09599795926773,13.5894944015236,4.63006663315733));
#632=CARTESIAN_POINT('',(2.23687483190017,13.5670188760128,4.87469522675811));
#633=CARTESIAN_POINT('',(2.29697620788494,13.5568743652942,5.00306535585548));
#634=CARTESIAN_POINT('',(2.39447431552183,13.5399943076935,5.26768843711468));
#635=CARTESIAN_POINT('',(2.431976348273,13.5332429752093,5.40390153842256));
#636=CARTESIAN_POINT('',(2.48353800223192,13.5238765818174,5.68082873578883));
#637=CARTESIAN_POINT('',(2.49760009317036,13.521261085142,5.82154235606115));
#638=CARTESIAN_POINT('',(2.5018039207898,13.5204836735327,6.10123171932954));
#639=CARTESIAN_POINT('',(2.49229921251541,13.5222559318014,6.24020208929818));
#640=CARTESIAN_POINT('',(2.45041058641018,13.5299088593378,6.51452954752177));
#641=CARTESIAN_POINT('',(2.41802678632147,13.5357895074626,6.64988665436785));
#642=CARTESIAN_POINT('',(2.33144458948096,13.5509696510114,6.91297024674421));
#643=CARTESIAN_POINT('',(2.2772822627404,13.5602634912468,7.04070895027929));
#644=CARTESIAN_POINT('',(2.14871842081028,13.5812272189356,7.28534305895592));
#645=CARTESIAN_POINT('',(2.07431559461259,13.5928972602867,7.40223776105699));
#646=CARTESIAN_POINT('',(1.90614429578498,13.6175040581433,7.62364109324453));
#647=CARTESIAN_POINT('',(1.81211769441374,13.6304563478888,7.72795196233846));
#648=CARTESIAN_POINT('',(1.60790814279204,13.6560499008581,7.91943385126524));
#649=CARTESIAN_POINT('',(1.49772148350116,13.6686910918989,8.00660092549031));
#650=CARTESIAN_POINT('',(1.26321398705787,13.6923621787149,8.16200037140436));
#651=CARTESIAN_POINT('',(1.13878231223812,13.7033776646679,8.23006773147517));
#652=CARTESIAN_POINT('',(0.88009238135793,13.7224157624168,8.34422402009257));
#653=CARTESIAN_POINT('',(0.745843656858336,13.7304412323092,8.39033394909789));
#654=CARTESIAN_POINT('',(0.509302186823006,13.7409258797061,8.44971928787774));
#655=CARTESIAN_POINT('',(0.408406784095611,13.7443097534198,8.46854291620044));
#656=CARTESIAN_POINT('',(0.205020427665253,13.748847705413,8.49368511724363));
#657=CARTESIAN_POINT('',(0.102529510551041,13.75000183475,8.50000397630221));
#658=CARTESIAN_POINT('',(0.,13.75,8.5));
#659=B_SPLINE_CURVE_WITH_KNOTS('',3,(#581,#582,#583,#584,#585,#586,#587,#588,#589,#590,#591,
#592,#593,#594,#595,#596,#597,#598,#599,#600,#601,#602,#603,#604,#605,#606,#607,#608,#609,#610,
#611,#612,#613,#614,#615,#616,#617,#618,#619,#620,#621,#622,#623,#624,#625,#626,#627,#628,#629,
#630,#631,#632,#633,#634,#635,#636,#637,#638,#639,#640,#641,#642,#643,#644,#645,#646,#647,#648,
#649,#650,#651,#652,#653,#654,#655,#656,#657,#658),.UNSPECIFIED.,.T.,.F.,(4,2,2,2,2,2,2,2,2,2,2,
2,2,2,2,2,2,2,2,2,2,2,2,2,2,2,2,2,2,2,2,2,2,2,2,2,2,2,4),(0.,0.417214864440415,
0.834790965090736,1.25200047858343,1.66917230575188,2.09056268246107,2.51198223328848,
2.93652440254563,3.36103223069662,3.78091276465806,4.20075791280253,4.61541709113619,
5.03009293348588,5.44711633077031,5.86417961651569,6.2874151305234,6.71065442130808,
7.13436908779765,7.55804146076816,7.97582001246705,8.39357931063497,8.80828929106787,
9.22302610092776,9.64205283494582,10.0611162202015,10.4853938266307,10.9096562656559,
11.331926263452,11.754151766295,12.1700813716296,12.5860088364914,13.001250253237,
13.4165185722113,13.8376389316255,14.2588560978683,14.6836075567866,15.1079519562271,
15.4152713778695,15.7225837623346),.UNSPECIFIED.);
#660=CARTESIAN_POINT('',(0.,13.75,8.5));
#661=VERTEX_POINT('',#660);
#662=EDGE_CURVE('E316',#661,#661,#659,.T.);
#663=ORIENTED_EDGE('',*,*,#662,.F.);
#664=EDGE_LOOP('',(#663));
#665=FACE_BOUND('',#664,.T.);
#666=ADVANCED_FACE('F301',(#580,#665),#154,.F.);
#667=CARTESIAN_POINT('',(0.,0.,1.3));
#668=DIRECTION('',(0.,0.,1.));
#669=DIRECTION('',(1.,0.,0.));
#670=AXIS2_PLACEMENT_3D('',#667,#668,#669);
#671=CONICAL_SURFACE('',#670,13.75,0.785398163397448);
#672=ORIENTED_EDGE('',*,*,#573,.T.);
#673=EDGE_LOOP('',(#672));
#674=FACE_BOUND('',#673,.T.);
#675=CARTESIAN_POINT('',(0.,0.,1.3));
#676=DIRECTION('',(0.,0.,1.));
#677=DIRECTION('',(1.,0.,0.));
#678=AXIS2_PLACEMENT_3D('',#675,#676,#677);
#679=CIRCLE('',#678,13.75);
#680=CARTESIAN_POINT('',(13.75,0.,1.3));
#681=VERTEX_POINT('',#680);
#682=EDGE_CURVE('E623',#681,#681,#679,.T.);
#683=ORIENTED_EDGE('',*,*,#682,.F.);
#684=EDGE_LOOP('',(#683));
#685=FACE_BOUND('',#684,.T.);
#686=ADVANCED_FACE('F306',(#674,#685),#671,.T.);
#687=CARTESIAN_POINT('',(0.,0.,58.));
#688=DIRECTION('',(0.,0.,1.));
#689=DIRECTION('',(1.,0.,0.));
#690=AXIS2_PLACEMENT_3D('',#687,#688,#689);
#691=CYLINDRICAL_SURFACE('',#690,13.75);
#692=ORIENTED_EDGE('',*,*,#682,.T.);
#693=EDGE_LOOP('',(#692));
#694=FACE_BOUND('',#693,.T.);
#695=ORIENTED_EDGE('',*,*,#662,.T.);
#696=EDGE_LOOP('',(#695));
#697=FACE_BOUND('',#696,.T.);
#698=CARTESIAN_POINT('',(0.,0.,19.5));
#699=DIRECTION('',(0.,0.,1.));
#700=DIRECTION('',(1.,0.,0.));
#701=AXIS2_PLACEMENT_3D('',#698,#699,#700);
#702=CIRCLE('',#701,13.75);
#703=CARTESIAN_POINT('',(13.75,0.,19.5));
#704=VERTEX_POINT('',#703);
#705=EDGE_CURVE('E626',#704,#704,#702,.T.);
#706=ORIENTED_EDGE('',*,*,#705,.F.);
#707=EDGE_LOOP('',(#706));
#708=FACE_BOUND('',#707,.T.);
#709=ADVANCED_FACE('F331',(#694,#697,#708),#691,.T.);
#710=CARTESIAN_POINT('',(0.,0.,19.5));
#711=DIRECTION('',(0.,0.,1.));
#712=DIRECTION('',(1.,0.,0.));
#713=AXIS2_PLACEMENT_3D('',#710,#711,#712);
#714=TOROIDAL_SURFACE('',#713,14.75,1.);
#715=CARTESIAN_POINT('',(0.,0.,20.5));
#716=DIRECTION('',(0.,0.,1.));
#717=DIRECTION('',(1.,0.,0.));
#718=AXIS2_PLACEMENT_3D('',#715,#716,#717);
#719=CIRCLE('',#718,14.75);
#720=CARTESIAN_POINT('',(14.75,0.,20.5));
#721=VERTEX_POINT('',#720);
#722=EDGE_CURVE('E629',#721,#721,#719,.T.);
#723=ORIENTED_EDGE('',*,*,#722,.F.);
#724=EDGE_LOOP('',(#723));
#725=FACE_BOUND('',#724,.T.);
#726=ORIENTED_EDGE('',*,*,#705,.T.);
#727=EDGE_LOOP('',(#726));
#728=FACE_BOUND('',#727,.T.);
#729=ADVANCED_FACE('F336',(#725,#728),#714,.F.);
#730=CARTESIAN_POINT('',(0.,37.25,20.5));
#731=DIRECTION('',(0.,0.,-1.));
#732=DIRECTION('',(-1.,0.,0.));
#733=AXIS2_PLACEMENT_3D('',#730,#731,#732);
#734=PLANE('',#733);
#735=ORIENTED_EDGE('',*,*,#722,.T.);
#736=EDGE_LOOP('',(#735));
#737=FACE_BOUND('',#736,.T.);
#738=CARTESIAN_POINT('',(0.,0.,20.5));
#739=DIRECTION('',(0.,0.,1.));
#740=DIRECTION('',(1.,0.,0.));
#741=AXIS2_PLACEMENT_3D('',#738,#739,#740);
#742=CIRCLE('',#741,37.25);
#743=CARTESIAN_POINT('',(37.25,0.,20.5));
#744=VERTEX_POINT('',#743);
#745=EDGE_CURVE('E632',#744,#744,#742,.T.);
#746=ORIENTED_EDGE('',*,*,#745,.F.);
#747=EDGE_LOOP('',(#746));
#748=FACE_BOUND('',#747,.T.);
#749=ADVANCED_FACE('F342',(#737,#748),#734,.T.);
#750=CARTESIAN_POINT('',(0.,0.,21.5));
#751=DIRECTION('',(0.,0.,1.));
#752=DIRECTION('',(1.,0.,0.));
#753=AXIS2_PLACEMENT_3D('',#750,#751,#752);
#754=CONICAL_SURFACE('',#753,38.25,0.785398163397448);
#755=ORIENTED_EDGE('',*,*,#745,.T.);
#756=EDGE_LOOP('',(#755));
#757=FACE_BOUND('',#756,.T.);
#758=CARTESIAN_POINT('',(0.,0.,21.5));
#759=DIRECTION('',(0.,0.,1.));
#760=DIRECTION('',(1.,0.,0.));
#761=AXIS2_PLACEMENT_3D('',#758,#759,#760);
#762=CIRCLE('',#761,38.25);
#763=CARTESIAN_POINT('',(38.25,0.,21.5));
#764=VERTEX_POINT('',#763);
#765=EDGE_CURVE('E635',#764,#764,#762,.T.);
#766=ORIENTED_EDGE('',*,*,#765,.F.);
#767=EDGE_LOOP('',(#766));
#768=FACE_BOUND('',#767,.T.);
#769=ADVANCED_FACE('F346',(#757,#768),#754,.T.);
#770=CARTESIAN_POINT('',(0.,0.,58.));
#771=DIRECTION('',(0.,0.,1.));
#772=DIRECTION('',(1.,0.,0.));
#773=AXIS2_PLACEMENT_3D('',#770,#771,#772);
#774=CYLINDRICAL_SURFACE('',#773,38.25);
#775=ORIENTED_EDGE('',*,*,#765,.T.);
#776=EDGE_LOOP('',(#775));
#777=FACE_BOUND('',#776,.T.);
#778=CARTESIAN_POINT('',(0.,0.,39.5));
#779=DIRECTION('',(0.,0.,1.));
#780=DIRECTION('',(1.,0.,0.));
#781=AXIS2_PLACEMENT_3D('',#778,#779,#780);
#782=CIRCLE('',#781,38.25);
#783=CARTESIAN_POINT('',(38.25,0.,39.5));
#784=VERTEX_POINT('',#783);
#785=EDGE_CURVE('E638',#784,#784,#782,.T.);
#786=ORIENTED_EDGE('',*,*,#785,.F.);
#787=EDGE_LOOP('',(#786));
#788=FACE_BOUND('',#787,.T.);
#789=ADVANCED_FACE('F350',(#777,#788),#774,.T.);
#790=CARTESIAN_POINT('',(0.,0.,43.1477808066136));
#791=DIRECTION('',(0.,0.,1.));
#792=DIRECTION('',(1.,0.,0.));
#793=AXIS2_PLACEMENT_3D('',#790,#791,#792);
#794=TOROIDAL_SURFACE('',#793,48.,1.);
#795=CARTESIAN_POINT('',(42.2411049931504,20.6236241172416,43.2647063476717));
#796=CARTESIAN_POINT('',(42.2375453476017,20.6257620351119,43.2455476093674));
#797=CARTESIAN_POINT('',(42.2348488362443,20.6273797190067,43.2261755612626));
#798=CARTESIAN_POINT('',(42.2312321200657,20.629548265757,43.1871994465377));
#799=CARTESIAN_POINT('',(42.2303126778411,20.6300986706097,43.1675952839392));
#800=CARTESIAN_POINT('',(42.2303002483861,20.630106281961,43.1157111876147));
#801=CARTESIAN_POINT('',(42.2327684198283,20.6286290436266,43.083413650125));
#802=CARTESIAN_POINT('',(42.2424377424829,20.6228250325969,43.0198054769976));
#803=CARTESIAN_POINT('',(42.2496427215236,20.6184959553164,42.9884956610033));
#804=CARTESIAN_POINT('',(42.2681281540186,20.6073375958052,42.9278240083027));
#805=CARTESIAN_POINT('',(42.2793821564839,20.6005245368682,42.8984509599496));
#806=CARTESIAN_POINT('',(42.3052415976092,20.5847772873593,42.8418470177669));
#807=CARTESIAN_POINT('',(42.3198487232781,20.575842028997,42.814617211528));
#808=CARTESIAN_POINT('',(42.3618688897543,20.5499580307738,42.7458099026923));
#809=CARTESIAN_POINT('',(42.3915097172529,20.5315317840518,42.7061505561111));
#810=CARTESIAN_POINT('',(42.4554058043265,20.4912584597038,42.6327045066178));
#811=CARTESIAN_POINT('',(42.4896745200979,20.4694013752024,42.5989356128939));
#812=CARTESIAN_POINT('',(42.5552369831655,20.4269605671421,42.5417777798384));
#813=CARTESIAN_POINT('',(42.5860968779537,20.40675592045,42.5175947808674));
#814=CARTESIAN_POINT('',(42.6492039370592,20.3649098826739,42.4724806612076));
#815=CARTESIAN_POINT('',(42.6814520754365,20.3432674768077,42.4515518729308));
#816=CARTESIAN_POINT('',(42.7796136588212,20.276517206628,42.3930251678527));
#817=CARTESIAN_POINT('',(42.8468900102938,20.2296211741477,42.3597312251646));
#818=CARTESIAN_POINT('',(42.9599776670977,20.1486141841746,42.3118119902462));
#819=CARTESIAN_POINT('',(43.0054687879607,20.1154522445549,42.2946631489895));
#820=CARTESIAN_POINT('',(43.0966462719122,20.0477796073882,42.26383473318));
#821=CARTESIAN_POINT('',(43.1423326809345,20.0132685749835,42.2501560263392));
#822=CARTESIAN_POINT('',(43.2791591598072,19.9080252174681,42.2136518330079));
#823=CARTESIAN_POINT('',(43.3701432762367,19.8355277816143,42.1953278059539));
#824=CARTESIAN_POINT('',(43.569443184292,19.6708828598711,42.1650721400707));
#825=CARTESIAN_POINT('',(43.6773263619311,19.5778371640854,42.1553310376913));
#826=CARTESIAN_POINT('',(43.8893025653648,19.3869364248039,42.1462848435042));
#827=CARTESIAN_POINT('',(43.9933917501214,19.2890767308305,42.1469900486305));
#828=CARTESIAN_POINT('',(44.1974400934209,19.0888440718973,42.1566388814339));
#829=CARTESIAN_POINT('',(44.2973827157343,18.9864558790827,42.1656126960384));
#830=CARTESIAN_POINT('',(44.4924218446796,18.7779082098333,42.1901932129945));
#831=CARTESIAN_POINT('',(44.5875167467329,18.6717475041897,42.2058020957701));
#832=CARTESIAN_POINT('',(44.8387142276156,18.3790153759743,42.2554205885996));
#833=CARTESIAN_POINT('',(44.9899382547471,18.1891120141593,42.294613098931));
#834=CARTESIAN_POINT('',(45.277123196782,17.8005053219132,42.3840500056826));
#835=CARTESIAN_POINT('',(45.4130737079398,17.601796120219,42.4343018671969));
#836=CARTESIAN_POINT('',(45.6693017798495,17.19690733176,42.5424590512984));
#837=CARTESIAN_POINT('',(45.7895994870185,16.9907377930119,42.6003543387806));
#838=CARTESIAN_POINT('',(46.0145721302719,16.5716287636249,42.7212136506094));
#839=CARTESIAN_POINT('',(46.1192511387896,16.3586910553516,42.7841763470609));
#840=CARTESIAN_POINT('',(46.3597384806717,15.8222652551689,42.9441552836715));
#841=CARTESIAN_POINT('',(46.4861960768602,15.4950107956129,43.0429439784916));
#842=CARTESIAN_POINT('',(46.5973171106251,15.1555100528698,43.1437228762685));
#843=CARTESIAN_POINT('',(46.5995469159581,15.1486725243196,43.145751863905));
#844=CARTESIAN_POINT('',(46.6017692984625,15.1418327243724,43.1477808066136));
#845=B_SPLINE_CURVE_WITH_KNOTS('',3,(#795,#796,#797,#798,#799,#800,#801,#802,#803,#804,#805,
#806,#807,#808,#809,#810,#811,#812,#813,#814,#815,#816,#817,#818,#819,#820,#821,#822,#823,#824,
#825,#826,#827,#828,#829,#830,#831,#832,#833,#834,#835,#836,#837,#838,#839,#840,#841,#842,#843,
#844),.UNSPECIFIED.,.F.,.F.,(4,2,2,2,2,2,2,2,2,2,2,2,2,2,2,2,2,2,2,2,2,2,2,2,4),(0.,
0.0587720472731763,0.117569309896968,0.214302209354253,0.311113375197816,0.407303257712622,
0.503541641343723,0.661124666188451,0.819176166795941,0.951306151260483,1.08353040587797,
1.34821119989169,1.52466450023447,1.70116187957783,2.05386097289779,2.48162571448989,
2.90981213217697,3.33956798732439,3.76946517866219,4.50607330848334,5.24318018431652,
5.97932875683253,6.71528504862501,7.80634771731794,7.8287656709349),.UNSPECIFIED.);
#846=CARTESIAN_POINT('',(44.4253300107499,18.8495004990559,42.1818549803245));
#847=VERTEX_POINT('',#846);
#848=CARTESIAN_POINT('',(46.6017692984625,15.1418327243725,43.1477808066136));
#849=VERTEX_POINT('',#848);
#850=EDGE_CURVE('E713',#847,#849,#845,.T.);
#851=ORIENTED_EDGE('',*,*,#850,.T.);
#852=CARTESIAN_POINT('',(46.6017692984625,15.1418327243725,43.1477808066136));
#853=CARTESIAN_POINT('',(46.6039916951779,15.1349928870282,43.1457518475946));
#854=CARTESIAN_POINT('',(46.60620674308,15.1281505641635,43.1437228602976));
#855=CARTESIAN_POINT('',(46.7074056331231,14.8143907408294,43.0507157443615));
#856=CARTESIAN_POINT('',(46.7916129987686,14.502500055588,42.9597363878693));
#857=CARTESIAN_POINT('',(46.9297349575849,13.8704667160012,42.7826969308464));
#858=CARTESIAN_POINT('',(46.9836266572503,13.550318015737,42.6966405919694));
#859=CARTESIAN_POINT('',(47.0448054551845,13.0334100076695,42.5675611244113));
#860=CARTESIAN_POINT('',(47.0621153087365,12.8386576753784,42.521120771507));
#861=CARTESIAN_POINT('',(47.0852967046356,12.4473028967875,42.4335544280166));
#862=CARTESIAN_POINT('',(47.0911705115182,12.2507008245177,42.392427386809));
#863=CARTESIAN_POINT('',(47.0912375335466,11.8556523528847,42.3171995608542));
#864=CARTESIAN_POINT('',(47.0854047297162,11.6572028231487,42.2831146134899));
#865=CARTESIAN_POINT('',(47.0676795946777,11.3589325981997,42.2391248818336));
#866=CARTESIAN_POINT('',(47.0602688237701,11.2593561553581,42.2256459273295));
#867=CARTESIAN_POINT('',(47.0424271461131,11.0601145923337,42.201466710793));
#868=CARTESIAN_POINT('',(47.0319955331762,10.9604494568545,42.1907670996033));
#869=CARTESIAN_POINT('',(47.0200433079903,10.8608006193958,42.1816549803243));
#870=B_SPLINE_CURVE_WITH_KNOTS('',3,(#852,#853,#854,#855,#856,#857,#858,#859,#860,#861,#862,
#863,#864,#865,#866,#867,#868,#869),.UNSPECIFIED.,.F.,.F.,(4,2,2,2,2,2,2,2,4),(0.,
0.0224179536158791,1.0276203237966,2.03358077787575,2.63610666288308,3.23851322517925,
3.84226017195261,4.14445886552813,4.44672826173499),.UNSPECIFIED.);
#871=CARTESIAN_POINT('',(47.0203053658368,10.8629875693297,42.1818549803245));
#872=VERTEX_POINT('',#871);
#873=EDGE_CURVE('E723',#849,#872,#870,.T.);
#874=ORIENTED_EDGE('',*,*,#873,.T.);
#875=CARTESIAN_POINT('',(0.,0.,42.1818549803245));
#876=DIRECTION('',(0.,0.,1.));
#877=DIRECTION('',(1.,0.,0.));
#878=AXIS2_PLACEMENT_3D('',#875,#876,#877);
#879=CIRCLE('',#878,48.2588190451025);
#880=EDGE_CURVE('E641',#872,#847,#879,.T.);
#881=ORIENTED_EDGE('',*,*,#880,.T.);
#882=EDGE_LOOP('',(#851,#874,#881));
#883=FACE_BOUND('',#882,.T.);
#884=ADVANCED_FACE('F353',(#883),#794,.T.);
#885=CARTESIAN_POINT('',(32.6640085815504,-33.8154924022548,43.3212286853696));
#886=CARTESIAN_POINT('',(32.6660689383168,-33.8066140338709,43.2932936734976));
#887=CARTESIAN_POINT('',(32.6676353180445,-33.7998320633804,43.2646356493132));
#888=CARTESIAN_POINT('',(32.6697360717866,-33.7907148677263,43.206647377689));
#889=CARTESIAN_POINT('',(32.6702725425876,-33.7883706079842,43.1773186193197));
#890=CARTESIAN_POINT('',(32.6702784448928,-33.788343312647,43.1156887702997));
#891=CARTESIAN_POINT('',(32.6696349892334,-33.7911534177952,43.0833857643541));
#892=CARTESIAN_POINT('',(32.6671015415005,-33.8021501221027,43.0197836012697));
#893=CARTESIAN_POINT('',(32.6652115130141,-33.8103368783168,42.9884844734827));
#894=CARTESIAN_POINT('',(32.6603130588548,-33.8313592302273,42.9278278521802));
#895=CARTESIAN_POINT('',(32.6573116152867,-33.8441657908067,42.8984595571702));
#896=CARTESIAN_POINT('',(32.6503263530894,-33.8736248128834,42.8418553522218));
#897=CARTESIAN_POINT('',(32.6463417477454,-33.8902803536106,42.8146211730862));
#898=CARTESIAN_POINT('',(32.6347084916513,-33.9382468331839,42.7458073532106));
#899=CARTESIAN_POINT('',(32.6263430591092,-33.9721331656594,42.7061459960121));
#900=CARTESIAN_POINT('',(32.6077856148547,-34.0453477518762,42.6327006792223));
#901=CARTESIAN_POINT('',(32.5975884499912,-34.0846912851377,42.5989338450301));
#902=CARTESIAN_POINT('',(32.5774855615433,-34.1601568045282,42.5417782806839));
#903=CARTESIAN_POINT('',(32.567806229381,-34.1957491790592,42.5175957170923));
#904=CARTESIAN_POINT('',(32.5475098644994,-34.2686972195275,42.4724823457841));
#905=CARTESIAN_POINT('',(32.5368921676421,-34.3060541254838,42.4515538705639));
#906=CARTESIAN_POINT('',(32.5037423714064,-34.4200388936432,42.3930264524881));
#907=CARTESIAN_POINT('',(32.4799306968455,-34.4985156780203,42.3597317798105));
#908=CARTESIAN_POINT('',(32.4378338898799,-34.6311028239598,42.3118118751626));
#909=CARTESIAN_POINT('',(32.4203524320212,-34.6846153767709,42.2946629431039));
#910=CARTESIAN_POINT('',(32.3841670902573,-34.7922429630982,42.2638343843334));
#911=CARTESIAN_POINT('',(32.3654629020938,-34.8463581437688,42.2501556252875));
#912=CARTESIAN_POINT('',(32.3076523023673,-35.0090095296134,42.2136516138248));
#913=CARTESIAN_POINT('',(32.266819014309,-35.1179428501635,42.1953277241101));
#914=CARTESIAN_POINT('',(32.1718198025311,-35.3583655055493,42.1650721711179));
#915=CARTESIAN_POINT('',(32.1166659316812,-35.4897209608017,42.1553310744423));
#916=CARTESIAN_POINT('',(32.0006130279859,-35.7503134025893,42.1462848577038));
#917=CARTESIAN_POINT('',(31.9397083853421,-35.879548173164,42.1469900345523));
#918=CARTESIAN_POINT('',(31.8123302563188,-36.1354849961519,42.1566388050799));
#919=CARTESIAN_POINT('',(31.7458371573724,-36.2621760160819,42.1656126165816));
#920=CARTESIAN_POINT('',(31.6077667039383,-36.5121145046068,42.1901931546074));
#921=CARTESIAN_POINT('',(31.536187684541,-36.6353608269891,42.2058020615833));
#922=CARTESIAN_POINT('',(31.3354069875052,-36.9647233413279,42.2554206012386));
#923=CARTESIAN_POINT('',(31.2015288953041,-37.1672293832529,42.2946131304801));
#924=CARTESIAN_POINT('',(30.920686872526,-37.5604447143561,42.3840500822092));
#925=CARTESIAN_POINT('',(30.7737141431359,-37.7511459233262,42.4343019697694));
#926=CARTESIAN_POINT('',(30.4678208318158,-38.1199507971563,42.5424591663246));
#927=CARTESIAN_POINT('',(30.3089160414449,-38.2980705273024,42.6003544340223));
#928=CARTESIAN_POINT('',(29.979840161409,-38.6415438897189,42.7212137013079));
#929=CARTESIAN_POINT('',(29.8096720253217,-38.8069008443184,42.7841763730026));
#930=CARTESIAN_POINT('',(29.3738155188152,-39.2013825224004,42.9441552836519));
#931=CARTESIAN_POINT('',(29.1016555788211,-39.4227780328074,43.0429439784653));
#932=CARTESIAN_POINT('',(28.8131094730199,-39.6333719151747,43.1437228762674));
#933=CARTESIAN_POINT('',(28.8072956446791,-39.6376054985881,43.1457518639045));
#934=CARTESIAN_POINT('',(28.8014773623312,-39.6418327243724,43.1477808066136));
#935=B_SPLINE_CURVE_WITH_KNOTS('',3,(#885,#886,#887,#888,#889,#890,#891,#892,#893,#894,#895,
#896,#897,#898,#899,#900,#901,#902,#903,#904,#905,#906,#907,#908,#909,#910,#911,#912,#913,#914,
#915,#916,#917,#918,#919,#920,#921,#922,#923,#924,#925,#926,#927,#928,#929,#930,#931,#932,#933,
#934),.UNSPECIFIED.,.F.,.F.,(4,2,2,2,2,2,2,2,2,2,2,2,2,2,2,2,2,2,2,2,2,2,2,2,4),(0.,
0.0880971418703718,0.176014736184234,0.272785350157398,0.369558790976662,0.46573432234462,
0.561987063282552,0.719579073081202,0.877621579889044,1.00974900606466,1.14197070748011,
1.40665660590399,1.58311096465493,1.75960939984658,2.11230638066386,2.54007031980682,
2.96825593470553,3.39801259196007,3.82791058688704,4.56451901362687,5.30162618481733,
6.03777446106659,6.77373045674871,7.86479312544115,7.88721107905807),.UNSPECIFIED.);
#936=CARTESIAN_POINT('',(31.655122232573,-36.426183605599,42.1818549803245));
#937=VERTEX_POINT('',#936);
#938=CARTESIAN_POINT('',(28.8014773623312,-39.6418327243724,43.1477808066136));
#939=VERTEX_POINT('',#938);
#940=EDGE_CURVE('E768',#937,#939,#935,.T.);
#941=ORIENTED_EDGE('',*,*,#940,.T.);
#942=CARTESIAN_POINT('',(28.8014773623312,-39.6418327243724,43.1477808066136));
#943=CARTESIAN_POINT('',(28.795659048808,-39.6460599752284,43.1457518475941));
#944=CARTESIAN_POINT('',(28.7898361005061,-39.6502810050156,43.1437228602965));
#945=CARTESIAN_POINT('',(28.5227049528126,-39.8434839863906,43.0507157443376));
#946=CARTESIAN_POINT('',(28.2521007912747,-40.019949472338,42.959736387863));
#947=CARTESIAN_POINT('',(27.6936833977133,-40.3466203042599,42.7826969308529));
#948=CARTESIAN_POINT('',(27.4058573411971,-40.4968057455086,42.6966405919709));
#949=CARTESIAN_POINT('',(26.9331539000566,-40.7147235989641,42.5675611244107));
#950=CARTESIAN_POINT('',(26.7532824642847,-40.7913680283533,42.5211207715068));
#951=CARTESIAN_POINT('',(26.3882453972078,-40.9343501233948,42.4335544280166));
#952=CARTESIAN_POINT('',(26.2030808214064,-41.0006898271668,42.3924273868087));
#953=CARTESIAN_POINT('',(25.8273881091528,-41.1228302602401,42.3171995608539));
#954=CARTESIAN_POINT('',(25.6368489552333,-41.1786072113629,42.2831146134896));
#955=CARTESIAN_POINT('',(25.3476997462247,-41.2539201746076,42.2391248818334));
#956=CARTESIAN_POINT('',(25.2507068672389,-41.2776429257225,42.2256459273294));
#957=CARTESIAN_POINT('',(25.0557034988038,-41.3222435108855,42.201466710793));
#958=CARTESIAN_POINT('',(24.9576927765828,-41.3431206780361,42.1907670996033));
#959=CARTESIAN_POINT('',(24.8592276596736,-41.3625466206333,42.1816549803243));
#960=B_SPLINE_CURVE_WITH_KNOTS('',3,(#942,#943,#944,#945,#946,#947,#948,#949,#950,#951,#952,
#953,#954,#955,#956,#957,#958,#959),.UNSPECIFIED.,.F.,.F.,(4,2,2,2,2,2,2,2,4),(0.,
0.0224179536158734,1.02762032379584,2.03358077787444,2.63610666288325,3.238513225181,
3.84226017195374,4.14445886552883,4.44672826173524),.UNSPECIFIED.);
#961=CARTESIAN_POINT('',(24.861388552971,-41.3621200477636,42.181854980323));
#962=VERTEX_POINT('',#961);
#963=EDGE_CURVE('E774',#939,#962,#960,.T.);
#964=ORIENTED_EDGE('',*,*,#963,.T.);
#965=EDGE_CURVE('E1289',#962,#937,#879,.T.);
#966=ORIENTED_EDGE('',*,*,#965,.T.);
#967=EDGE_LOOP('',(#941,#964,#966));
#968=FACE_BOUND('',#967,.T.);
#969=ADVANCED_FACE('F1097',(#968),#794,.T.);
#970=CARTESIAN_POINT('',(-24.8592276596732,-41.3625466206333,42.1816549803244));
#971=CARTESIAN_POINT('',(-24.9416055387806,-41.3462943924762,42.1892747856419));
#972=CARTESIAN_POINT('',(-25.0236680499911,-41.3290259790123,42.1980104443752));
#973=CARTESIAN_POINT('',(-25.1870963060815,-41.2924895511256,42.2174744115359));
#974=CARTESIAN_POINT('',(-25.2684621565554,-41.2732218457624,42.2282024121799));
#975=CARTESIAN_POINT('',(-25.5113148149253,-41.2124956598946,42.2630006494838));
#976=CARTESIAN_POINT('',(-25.6716981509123,-41.168086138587,42.2896990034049));
#977=CARTESIAN_POINT('',(-25.9889668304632,-41.0717020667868,42.3485735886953));
#978=CARTESIAN_POINT('',(-26.1458550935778,-41.0197341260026,42.3807450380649));
#979=CARTESIAN_POINT('',(-26.4560497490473,-40.9084323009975,42.4494183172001));
#980=CARTESIAN_POINT('',(-26.6093552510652,-40.8490966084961,42.4859212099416));
#981=CARTESIAN_POINT('',(-27.1212099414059,-40.6364098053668,42.6149452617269));
#982=CARTESIAN_POINT('',(-27.4709843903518,-40.4663342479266,42.7152440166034));
#983=CARTESIAN_POINT('',(-28.1462660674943,-40.0882687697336,42.9242691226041));
#984=CARTESIAN_POINT('',(-28.4717913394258,-39.8803074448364,43.0329890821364));
#985=CARTESIAN_POINT('',(-28.7898361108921,-39.6502809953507,43.1437228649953));
#986=CARTESIAN_POINT('',(-28.7956590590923,-39.6460599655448,43.1457518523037));
#987=CARTESIAN_POINT('',(-28.8014773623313,-39.6418327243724,43.1477808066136));
#988=B_SPLINE_CURVE_WITH_KNOTS('',3,(#970,#971,#972,#973,#974,#975,#976,#977,#978,#979,#980,
#981,#982,#983,#984,#985,#986,#987),.UNSPECIFIED.,.F.,.F.,(4,2,2,2,2,2,2,2,4),(0.,
0.252899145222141,0.505759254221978,1.01104586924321,1.51589324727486,2.02086477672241,
3.22282684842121,4.42388542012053,4.44630337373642),.UNSPECIFIED.);
#989=CARTESIAN_POINT('',(-24.8613885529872,-41.3621200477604,42.1818549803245));
#990=VERTEX_POINT('',#989);
#991=CARTESIAN_POINT('',(-28.8014773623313,-39.6418327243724,43.1477808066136));
#992=VERTEX_POINT('',#991);
#993=EDGE_CURVE('E811',#990,#992,#988,.T.);
#994=ORIENTED_EDGE('',*,*,#993,.T.);
#995=CARTESIAN_POINT('',(-28.8014773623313,-39.6418327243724,43.1477808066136));
#996=CARTESIAN_POINT('',(-28.8072956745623,-39.6376054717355,43.145751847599));
#997=CARTESIAN_POINT('',(-28.8131095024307,-39.6333718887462,43.1437228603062));
#998=CARTESIAN_POINT('',(-29.0794045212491,-39.4390180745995,43.050715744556));
#999=CARTESIAN_POINT('',(-29.3308544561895,-39.2361890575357,42.9597363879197));
#1000=CARTESIAN_POINT('',(-29.8140973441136,-38.8060493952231,42.7826969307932));
#1001=CARTESIAN_POINT('',(-30.0458753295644,-38.5787204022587,42.6966405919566));
#1002=CARTESIAN_POINT('',(-30.3992009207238,-38.1964930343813,42.5675611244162));
#1003=CARTESIAN_POINT('',(-30.5276774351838,-38.0491095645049,42.5211207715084));
#1004=CARTESIAN_POINT('',(-30.776464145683,-37.7461225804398,42.4335544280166));
#1005=CARTESIAN_POINT('',(-30.8967759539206,-37.5905206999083,42.3924273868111));
#1006=CARTESIAN_POINT('',(-31.1290338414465,-37.2709591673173,42.3171995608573));
#1007=CARTESIAN_POINT('',(-31.2409607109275,-37.1069816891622,42.2831146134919));
#1008=CARTESIAN_POINT('',(-31.4019396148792,-36.8552574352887,42.2391248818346));
#1009=CARTESIAN_POINT('',(-31.4544737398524,-36.7703424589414,42.2256459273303));
#1010=CARTESIAN_POINT('',(-31.557150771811,-36.5986655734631,42.2014667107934));
#1011=CARTESIAN_POINT('',(-31.6072931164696,-36.5119032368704,42.1907670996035));
#1012=CARTESIAN_POINT('',(-31.6561956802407,-36.4242602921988,42.1816549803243));
#1013=B_SPLINE_CURVE_WITH_KNOTS('',3,(#995,#996,#997,#998,#999,#1000,#1001,#1002,#1003,#1004,
#1005,#1006,#1007,#1008,#1009,#1010,#1011,#1012),.UNSPECIFIED.,.F.,.F.,(4,2,2,2,2,2,2,2,4),(0.,
0.0224179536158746,1.02762032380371,2.03358077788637,2.63610666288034,3.23851322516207,
3.84226017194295,4.14445886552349,4.44672826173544),.UNSPECIFIED.);
#1014=CARTESIAN_POINT('',(-31.6551222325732,-36.4261836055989,42.1818549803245));
#1015=VERTEX_POINT('',#1014);
#1016=EDGE_CURVE('E820',#992,#1015,#1013,.T.);
#1017=ORIENTED_EDGE('',*,*,#1016,.T.);
#1018=EDGE_CURVE('E1288',#1015,#990,#879,.T.);
#1019=ORIENTED_EDGE('',*,*,#1018,.T.);
#1020=EDGE_LOOP('',(#994,#1017,#1019));
#1021=FACE_BOUND('',#1020,.T.);
#1022=ADVANCED_FACE('F362',(#1021),#794,.T.);
#1023=CARTESIAN_POINT('',(-47.0200433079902,10.8608006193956,42.1816549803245));
#1024=CARTESIAN_POINT('',(-47.0300426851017,10.9441688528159,42.1892747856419));
#1025=CARTESIAN_POINT('',(-47.0389781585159,11.0275511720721,42.1980104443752));
#1026=CARTESIAN_POINT('',(-47.054732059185,11.1942710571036,42.2174744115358));
#1027=CARTESIAN_POINT('',(-47.0615508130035,11.2776086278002,42.2282024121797));
#1028=CARTESIAN_POINT('',(-47.0788423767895,11.5273406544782,42.2630006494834));
#1029=CARTESIAN_POINT('',(-47.0861675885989,11.6935975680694,42.2896990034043));
#1030=CARTESIAN_POINT('',(-47.0925423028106,12.025122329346,42.3485735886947));
#1031=CARTESIAN_POINT('',(-47.0915989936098,12.1903909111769,42.3807450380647));
#1032=CARTESIAN_POINT('',(-47.0816000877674,12.5197977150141,42.4494183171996));
#1033=CARTESIAN_POINT('',(-47.0725424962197,12.6839356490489,42.4859212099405));
#1034=CARTESIAN_POINT('',(-47.0284371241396,13.2364622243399,42.6149452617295));
#1035=CARTESIAN_POINT('',(-46.9747719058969,13.621673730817,42.7152440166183));
#1036=CARTESIAN_POINT('',(-46.8238837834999,14.3807334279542,42.9242691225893));
#1037=CARTESIAN_POINT('',(-46.7266936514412,14.7545899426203,43.0329890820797));
#1038=CARTESIAN_POINT('',(-46.6062067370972,15.1281505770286,43.1437228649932));
#1039=CARTESIAN_POINT('',(-46.6039916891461,15.134992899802,43.1457518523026));
#1040=CARTESIAN_POINT('',(-46.6017692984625,15.1418327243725,43.1477808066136));
#1041=B_SPLINE_CURVE_WITH_KNOTS('',3,(#1023,#1024,#1025,#1026,#1027,#1028,#1029,#1030,#1031,
#1032,#1033,#1034,#1035,#1036,#1037,#1038,#1039,#1040),.UNSPECIFIED.,.F.,.F.,(4,2,2,2,2,2,2,2,
4),(0.,0.252899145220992,0.505759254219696,1.01104586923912,1.51589324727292,2.02086477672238,
3.22282684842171,4.42388542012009,4.44630337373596),.UNSPECIFIED.);
#1042=CARTESIAN_POINT('',(-47.0203053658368,10.8629875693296,42.1818549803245));
#1043=VERTEX_POINT('',#1042);
#1044=CARTESIAN_POINT('',(-46.6017692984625,15.1418327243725,43.1477808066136));
#1045=VERTEX_POINT('',#1044);
#1046=EDGE_CURVE('E600',#1043,#1045,#1041,.T.);
#1047=ORIENTED_EDGE('',*,*,#1046,.T.);
#1048=CARTESIAN_POINT('',(-46.6017692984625,15.1418327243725,43.1477808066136));
#1049=CARTESIAN_POINT('',(-46.5995468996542,15.1486725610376,43.1457518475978));
#1050=CARTESIAN_POINT('',(-46.5973170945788,15.1555100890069,43.1437228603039));
#1051=CARTESIAN_POINT('',(-46.4947653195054,15.4688303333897,43.0507157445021));
#1052=CARTESIAN_POINT('',(-46.3795657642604,15.7706510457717,42.9597363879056));
#1053=CARTESIAN_POINT('',(-46.1198089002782,16.3631628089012,42.7826969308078));
#1054=CARTESIAN_POINT('',(-45.9752295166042,16.653845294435,42.6966405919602));
#1055=CARTESIAN_POINT('',(-45.7208932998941,17.1079926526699,42.5675611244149));
#1056=CARTESIAN_POINT('',(-45.6204247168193,17.2757250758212,42.521120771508));
#1057=CARTESIAN_POINT('',(-45.4091462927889,17.605963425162,42.4335544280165));
#1058=CARTESIAN_POINT('',(-45.2983385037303,17.7684703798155,42.3924273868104));
#1059=CARTESIAN_POINT('',(-45.0661890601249,18.0881107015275,42.3171995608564));
#1060=CARTESIAN_POINT('',(-44.9448245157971,18.24523130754,42.2831146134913));
#1061=CARTESIAN_POINT('',(-44.7551657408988,18.4761184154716,42.2391248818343));
#1062=CARTESIAN_POINT('',(-44.6906407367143,18.5523215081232,42.2256459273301));
#1063=CARTESIAN_POINT('',(-44.5590952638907,18.7030242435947,42.2014667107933));
#1064=CARTESIAN_POINT('',(-44.4920742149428,18.777523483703,42.1907670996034));
#1065=CARTESIAN_POINT('',(-44.4238325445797,18.8511157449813,42.1816549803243));
#1066=B_SPLINE_CURVE_WITH_KNOTS('',3,(#1048,#1049,#1050,#1051,#1052,#1053,#1054,#1055,#1056,
#1057,#1058,#1059,#1060,#1061,#1062,#1063,#1064,#1065),.UNSPECIFIED.,.F.,.F.,(4,2,2,2,2,2,2,2,
4),(0.,0.0224179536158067,1.02762032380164,2.03358077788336,2.63610666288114,3.238513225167,
3.84226017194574,4.14445886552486,4.44672826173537),.UNSPECIFIED.);
#1067=CARTESIAN_POINT('',(-44.4253300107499,18.8495004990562,42.1818549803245));
#1068=VERTEX_POINT('',#1067);
#1069=EDGE_CURVE('E579',#1045,#1068,#1066,.T.);
#1070=ORIENTED_EDGE('',*,*,#1069,.T.);
#1071=EDGE_CURVE('E646',#1068,#1043,#879,.T.);
#1072=ORIENTED_EDGE('',*,*,#1071,.T.);
#1073=EDGE_LOOP('',(#1047,#1070,#1072));
#1074=FACE_BOUND('',#1073,.T.);
#1075=ADVANCED_FACE('F363',(#1074),#794,.T.);
#1076=CARTESIAN_POINT('',(4.19875832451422,48.0758155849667,42.181854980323));
#1077=VERTEX_POINT('',#1076);
#1078=CARTESIAN_POINT('',(-4.19875832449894,48.0758155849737,42.1818549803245));
#1079=VERTEX_POINT('',#1078);
#1080=EDGE_CURVE('E642',#1077,#1079,#879,.T.);
#1081=ORIENTED_EDGE('',*,*,#1080,.T.);
#1082=CARTESIAN_POINT('',(-4.20075725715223,48.0748905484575,42.1816549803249));
#1083=CARTESIAN_POINT('',(-4.12455933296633,48.1101627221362,42.1892747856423));
#1084=CARTESIAN_POINT('',(-4.04801924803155,48.1444274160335,42.1980104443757));
#1085=CARTESIAN_POINT('',(-3.89432743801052,48.2109295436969,42.2174744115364));
#1086=CARTESIAN_POINT('',(-3.81717580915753,48.2431672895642,42.2282024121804));
#1087=CARTESIAN_POINT('',(-3.58500992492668,48.3367839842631,42.2630006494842));
#1088=CARTESIAN_POINT('',(-3.42915381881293,48.3951268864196,42.2896990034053));
#1089=CARTESIAN_POINT('',(-3.11582492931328,48.5036363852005,42.3485735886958));
#1090=CARTESIAN_POINT('',(-2.95835366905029,48.55381004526,42.3807450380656));
#1091=CARTESIAN_POINT('',(-2.64197934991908,48.646092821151,42.4494183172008));
#1092=CARTESIAN_POINT('',(-2.48307594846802,48.6881999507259,42.4859212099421));
#1093=CARTESIAN_POINT('',(-1.94396263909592,48.8169933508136,42.6149452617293));
#1094=CARTESIAN_POINT('',(-1.56102126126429,48.8849915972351,42.7152440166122));
#1095=CARTESIAN_POINT('',(-0.79248559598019,48.9760508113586,42.9242691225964));
#1096=CARTESIAN_POINT('',(-0.406893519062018,48.9991455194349,43.0329890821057));
#1097=CARTESIAN_POINT('',(-0.014383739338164,48.9999922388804,43.1437228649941));
#1098=CARTESIAN_POINT('',(-0.00719181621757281,48.9999999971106,43.1457518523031));
#1099=CARTESIAN_POINT('',(0.,49.,43.1477808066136));
#1100=B_SPLINE_CURVE_WITH_KNOTS('',3,(#1082,#1083,#1084,#1085,#1086,#1087,#1088,#1089,#1090,
#1091,#1092,#1093,#1094,#1095,#1096,#1097,#1098,#1099),.UNSPECIFIED.,.F.,.F.,(4,2,2,2,2,2,2,2,
4),(0.,0.252899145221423,0.50575925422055,1.01104586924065,1.51589324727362,2.02086477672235,
3.2228268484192,4.42388542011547,4.44630337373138),.UNSPECIFIED.);
#1101=CARTESIAN_POINT('',(0.,49.,43.1477808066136));
#1102=VERTEX_POINT('',#1101);
#1103=EDGE_CURVE('E467',#1079,#1102,#1100,.T.);
#1104=ORIENTED_EDGE('',*,*,#1103,.T.);
#1105=CARTESIAN_POINT('',(0.,49.,43.1477808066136));
#1106=CARTESIAN_POINT('',(0.00719183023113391,48.9999999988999,43.1457518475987));
#1107=CARTESIAN_POINT('',(0.0143837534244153,48.9999922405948,43.1437228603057));
#1108=CARTESIAN_POINT('',(0.344059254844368,48.9992809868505,43.0507157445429));
#1109=CARTESIAN_POINT('',(0.666706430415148,48.9829874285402,42.9597363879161));
#1110=CARTESIAN_POINT('',(1.31048788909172,48.9190401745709,42.7826969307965));
#1111=CARTESIAN_POINT('',(1.63162084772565,48.871362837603,42.6966405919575));
#1112=CARTESIAN_POINT('',(2.14213486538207,48.7698139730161,42.5675611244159));
#1113=CARTESIAN_POINT('',(2.33270437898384,48.7260948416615,42.5211207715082));
#1114=CARTESIAN_POINT('',(2.7120683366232,48.6272063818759,42.4335544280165));
#1115=CARTESIAN_POINT('',(2.90086312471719,48.5720393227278,42.3924273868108));
#1116=CARTESIAN_POINT('',(3.2765972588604,48.4500263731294,42.3171995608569));
#1117=CARTESIAN_POINT('',(3.4635315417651,48.3831547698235,42.2831146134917));
#1118=CARTESIAN_POINT('',(3.74172601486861,48.2741265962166,42.2391248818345));
#1119=CARTESIAN_POINT('',(3.83413878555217,48.2363077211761,42.2256459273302));
#1120=CARTESIAN_POINT('',(4.01811539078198,48.1577702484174,42.2014667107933));
#1121=CARTESIAN_POINT('',(4.10967902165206,48.1170509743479,42.1907670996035));
#1122=CARTESIAN_POINT('',(4.20075725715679,48.0748905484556,42.1816549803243));
#1123=B_SPLINE_CURVE_WITH_KNOTS('',3,(#1105,#1106,#1107,#1108,#1109,#1110,#1111,#1112,#1113,
#1114,#1115,#1116,#1117,#1118,#1119,#1120,#1121,#1122),.UNSPECIFIED.,.F.,.F.,(4,2,2,2,2,2,2,2,
4),(0.,0.0224179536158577,1.02762032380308,2.03358077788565,2.63610666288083,3.23851322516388,
3.84226017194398,4.14445886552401,4.44672826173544),.UNSPECIFIED.);
#1124=EDGE_CURVE('E475',#1102,#1077,#1123,.T.);
#1125=ORIENTED_EDGE('',*,*,#1124,.T.);
#1126=EDGE_LOOP('',(#1081,#1104,#1125));
#1127=FACE_BOUND('',#1126,.T.);
#1128=ADVANCED_FACE('F360',(#1127),#794,.T.);
#1129=CARTESIAN_POINT('',(0.,0.,42.1818549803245));
#1130=DIRECTION('',(0.,0.,1.));
#1131=DIRECTION('',(1.,0.,0.));
#1132=AXIS2_PLACEMENT_3D('',#1129,#1130,#1131);
#1133=CONICAL_SURFACE('',#1132,48.2588190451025,1.30899693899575);
#1134=ORIENTED_EDGE('',*,*,#785,.T.);
#1135=EDGE_LOOP('',(#1134));
#1136=FACE_BOUND('',#1135,.T.);
#1137=ORIENTED_EDGE('',*,*,#1071,.F.);
#1138=CARTESIAN_POINT('',(-43.3598928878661,4.26041504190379,40.925140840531));
#1139=CARTESIAN_POINT('',(-43.557459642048,4.41934880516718,40.9819893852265));
#1140=CARTESIAN_POINT('',(-43.7491684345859,4.58599585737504,41.0376556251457));
#1141=CARTESIAN_POINT('',(-44.119744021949,4.93379092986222,41.1464110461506));
#1142=CARTESIAN_POINT('',(-44.2986103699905,5.11493945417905,41.1995001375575));
#1143=CARTESIAN_POINT('',(-44.6428085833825,5.49128996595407,41.303019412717));
#1144=CARTESIAN_POINT('',(-44.8081039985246,5.68652731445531,41.3534423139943));
#1145=CARTESIAN_POINT('',(-45.1235704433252,6.08956761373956,41.4512773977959));
#1146=CARTESIAN_POINT('',(-45.2737414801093,6.29737055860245,41.4986895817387));
#1147=CARTESIAN_POINT('',(-45.5697080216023,6.74204284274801,41.5940996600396));
#1148=CARTESIAN_POINT('',(-45.7141182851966,6.97989541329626,41.6418226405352));
#1149=CARTESIAN_POINT('',(-45.9828878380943,7.46740290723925,41.7332918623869));
#1150=CARTESIAN_POINT('',(-46.1072469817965,7.7170579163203,41.7770380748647));
#1151=CARTESIAN_POINT('',(-46.334618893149,8.22586272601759,41.8602472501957));
#1152=CARTESIAN_POINT('',(-46.4376819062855,8.48498843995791,41.89972018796));
#1153=CARTESIAN_POINT('',(-46.6219193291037,9.01140244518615,41.974299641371));
#1154=CARTESIAN_POINT('',(-46.7031036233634,9.27868698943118,42.0094081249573));
#1155=CARTESIAN_POINT('',(-46.8288216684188,9.76505819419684,42.0684820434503));
#1156=CARTESIAN_POINT('',(-46.8774446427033,9.9829982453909,42.0932670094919));
#1157=CARTESIAN_POINT('',(-46.9600490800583,10.4220012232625,42.1398900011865));
#1158=CARTESIAN_POINT('',(-46.9940271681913,10.6430648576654,42.1617273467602));
#1159=CARTESIAN_POINT('',(-47.0531149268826,11.1375666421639,42.2069849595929));
#1160=CARTESIAN_POINT('',(-47.0744749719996,11.411530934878,42.229644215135));
#1161=CARTESIAN_POINT('',(-47.0945676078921,11.9607344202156,42.2703177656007));
#1162=CARTESIAN_POINT('',(-47.0932908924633,12.2359740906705,42.2883301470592));
#1163=CARTESIAN_POINT('',(-47.0680037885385,12.7860995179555,42.319638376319));
#1164=CARTESIAN_POINT('',(-47.0439590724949,13.060984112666,42.3329270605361));
#1165=CARTESIAN_POINT('',(-46.9731998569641,13.6080121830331,42.3546865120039));
#1166=CARTESIAN_POINT('',(-46.9264854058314,13.8801556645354,42.363157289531));
#1167=CARTESIAN_POINT('',(-46.8107125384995,14.4196208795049,42.3752379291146));
#1168=CARTESIAN_POINT('',(-46.7416649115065,14.6869448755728,42.3788501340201));
#1169=CARTESIAN_POINT('',(-46.5816958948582,15.2149956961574,42.3812040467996));
#1170=CARTESIAN_POINT('',(-46.4907739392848,15.4757223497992,42.3799456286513));
#1171=CARTESIAN_POINT('',(-46.2877498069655,15.9886146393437,42.3725653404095));
#1172=CARTESIAN_POINT('',(-46.1756552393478,16.2407833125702,42.3664452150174));
#1173=CARTESIAN_POINT('',(-45.9310909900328,16.7348648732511,42.3493728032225));
#1174=CARTESIAN_POINT('',(-45.7986214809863,16.9767778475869,42.338420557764));
#1175=CARTESIAN_POINT('',(-45.5146530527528,17.4480505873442,42.3117696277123));
#1176=CARTESIAN_POINT('',(-45.3632031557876,17.6774405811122,42.296083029));
#1177=CARTESIAN_POINT('',(-45.0421374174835,18.1227421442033,42.2600273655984));
#1178=CARTESIAN_POINT('',(-44.8725215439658,18.3386536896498,42.2396582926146));
#1179=CARTESIAN_POINT('',(-44.5163717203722,18.7555461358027,42.1943312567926));
#1180=CARTESIAN_POINT('',(-44.3298366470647,18.9565260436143,42.1693729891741));
#1181=CARTESIAN_POINT('',(-43.9412387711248,19.3422022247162,42.1149846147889));
#1182=CARTESIAN_POINT('',(-43.7391760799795,19.5268986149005,42.0855545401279));
#1183=CARTESIAN_POINT('',(-43.3193182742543,19.8802307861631,42.0221033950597));
#1184=CARTESIAN_POINT('',(-43.1014097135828,20.0487254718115,41.9880473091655));
#1185=CARTESIAN_POINT('',(-42.6529202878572,20.3668846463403,41.9156866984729));
#1186=CARTESIAN_POINT('',(-42.4223391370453,20.516548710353,41.8773820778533));
#1187=CARTESIAN_POINT('',(-41.9502094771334,20.7961068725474,41.7967055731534));
#1188=CARTESIAN_POINT('',(-41.7086627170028,20.9260041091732,41.7543343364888));
#1189=CARTESIAN_POINT('',(-41.2163968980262,21.1652631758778,41.6657328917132));
#1190=CARTESIAN_POINT('',(-40.965679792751,21.274629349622,41.6195035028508));
#1191=CARTESIAN_POINT('',(-40.3666150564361,21.5072496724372,41.5063544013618));
#1192=CARTESIAN_POINT('',(-40.0150907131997,21.6217421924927,41.4378984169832));
#1193=CARTESIAN_POINT('',(-39.4813438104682,21.7635695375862,41.3307079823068));
#1194=CARTESIAN_POINT('',(-39.3024800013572,21.8058407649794,41.2942540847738));
#1195=CARTESIAN_POINT('',(-38.9430062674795,21.8804211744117,41.2198956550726));
#1196=CARTESIAN_POINT('',(-38.7623965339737,21.9127314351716,41.1819912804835));
#1197=CARTESIAN_POINT('',(-38.581136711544,21.9400448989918,41.1433897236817));
#1198=B_SPLINE_CURVE_WITH_KNOTS('',3,(#1138,#1139,#1140,#1141,#1142,#1143,#1144,#1145,#1146,
#1147,#1148,#1149,#1150,#1151,#1152,#1153,#1154,#1155,#1156,#1157,#1158,#1159,#1160,#1161,#1162,
#1163,#1164,#1165,#1166,#1167,#1168,#1169,#1170,#1171,#1172,#1173,#1174,#1175,#1176,#1177,#1178,
#1179,#1180,#1181,#1182,#1183,#1184,#1185,#1186,#1187,#1188,#1189,#1190,#1191,#1192,#1193,#1194,
#1195,#1196,#1197),.UNSPECIFIED.,.F.,.F.,(4,2,2,2,2,2,2,2,2,2,2,2,2,2,2,2,2,2,2,2,2,2,2,2,2,2,2,
2,2,4),(0.,0.779389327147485,1.55880575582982,2.34025143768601,3.12169675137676,
3.96766912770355,4.81364764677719,5.65760680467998,6.50118402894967,7.17469361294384,
7.84835832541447,8.67454634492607,9.50107402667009,10.3288498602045,11.156623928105,
11.9839986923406,12.8113948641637,13.6384942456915,14.4655866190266,15.2905851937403,
16.1155852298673,16.9406400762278,17.7656889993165,18.5973725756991,19.4290749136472,
20.2606450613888,21.0920390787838,22.2173883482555,22.7792701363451,23.3410910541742),.UNSPECIFIED.);
#1199=CARTESIAN_POINT('',(-40.5694319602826,21.4272657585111,41.5445461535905));
#1200=VERTEX_POINT('',#1199);
#1201=EDGE_CURVE('E323',#1068,#1200,#1198,.T.);
#1202=ORIENTED_EDGE('',*,*,#1201,.T.);
#1203=CARTESIAN_POINT('',(-7.84173970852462,45.2054104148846,41.5445913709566));
#1204=CARTESIAN_POINT('',(-8.42085756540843,44.4735265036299,41.3779127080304));
#1205=CARTESIAN_POINT('',(-9.014507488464,43.751377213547,41.2186648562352));
#1206=CARTESIAN_POINT('',(-10.2303671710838,42.3275993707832,40.9174273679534));
#1207=CARTESIAN_POINT('',(-10.852582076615,41.6259745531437,40.7754408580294));
#1208=CARTESIAN_POINT('',(-12.1256219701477,40.2437327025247,40.5110259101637));
#1209=CARTESIAN_POINT('',(-12.7764804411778,39.5631419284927,40.388621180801));
#1210=CARTESIAN_POINT('',(-14.1052590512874,38.2251851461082,40.1660730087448));
#1211=CARTESIAN_POINT('',(-14.7831775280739,37.5678177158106,40.0659282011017));
#1212=CARTESIAN_POINT('',(-16.1445755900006,36.2968020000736,39.8928294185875));
#1213=CARTESIAN_POINT('',(-16.8272924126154,35.6824351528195,39.8191563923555));
#1214=CARTESIAN_POINT('',(-18.2161489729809,34.4781324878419,39.6967609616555));
#1215=CARTESIAN_POINT('',(-18.9222890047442,33.8881969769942,39.6480388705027));
#1216=CARTESIAN_POINT('',(-20.3561039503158,32.7345158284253,39.5768694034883));
#1217=CARTESIAN_POINT('',(-21.0837630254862,32.1707516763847,39.554403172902));
#1218=CARTESIAN_POINT('',(-22.5595455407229,31.0702579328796,39.5363126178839));
#1219=CARTESIAN_POINT('',(-23.30766821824,30.5335273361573,39.5406872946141));
#1220=CARTESIAN_POINT('',(-24.7008252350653,29.5723621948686,39.5732890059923));
#1221=CARTESIAN_POINT('',(-25.3430810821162,29.1437533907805,39.5975654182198));
#1222=CARTESIAN_POINT('',(-26.6398244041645,28.306994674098,39.664437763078));
#1223=CARTESIAN_POINT('',(-27.2943115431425,27.8988442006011,39.7070331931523));
#1224=CARTESIAN_POINT('',(-28.614800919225,27.1033485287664,39.8097759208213));
#1225=CARTESIAN_POINT('',(-29.2808074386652,26.7160112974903,39.8699298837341));
#1226=CARTESIAN_POINT('',(-30.6230901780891,25.9627400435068,40.0067256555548));
#1227=CARTESIAN_POINT('',(-31.2993664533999,25.5968061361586,40.0833675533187));
#1228=CARTESIAN_POINT('',(-33.3774079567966,24.5132916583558,40.3405727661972));
#1229=CARTESIAN_POINT('',(-34.7945405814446,23.8304050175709,40.5456900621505));
#1230=CARTESIAN_POINT('',(-36.9437456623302,22.8763834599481,40.8928356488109));
#1231=CARTESIAN_POINT('',(-37.6638275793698,22.570182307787,41.0150830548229));
#1232=CARTESIAN_POINT('',(-39.1113408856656,21.9811595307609,41.2713489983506));
#1233=CARTESIAN_POINT('',(-39.8387715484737,21.6983356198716,41.4053663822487));
#1234=CARTESIAN_POINT('',(-40.5696319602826,21.427191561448,41.5445842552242));
#1235=B_SPLINE_CURVE_WITH_KNOTS('',3,(#1203,#1204,#1205,#1206,#1207,#1208,#1209,#1210,#1211,
#1212,#1213,#1214,#1215,#1216,#1217,#1218,#1219,#1220,#1221,#1222,#1223,#1224,#1225,#1226,#1227,
#1228,#1229,#1230,#1231,#1232,#1233,#1234),.UNSPECIFIED.,.F.,.F.,(4,2,2,2,2,2,2,2,2,2,2,2,2,2,2,
4),(0.,2.84406583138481,5.68864604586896,8.53664467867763,11.3844686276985,14.1477362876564,
16.9110386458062,19.6723554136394,22.4335694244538,24.7505562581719,27.0674795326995,
29.3852834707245,31.7030999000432,36.4572944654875,38.8328505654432,41.2081740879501),.UNSPECIFIED.);
#1236=CARTESIAN_POINT('',(-7.84189796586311,45.2052104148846,41.5445458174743));
#1237=VERTEX_POINT('',#1236);
#1238=EDGE_CURVE('E324',#1237,#1200,#1235,.T.);
#1239=ORIENTED_EDGE('',*,*,#1238,.F.);
#1240=CARTESIAN_POINT('',(-7.96224178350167,45.0500170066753,41.5091469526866));
#1241=CARTESIAN_POINT('',(-7.92270376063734,45.102053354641,41.5210333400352));
#1242=CARTESIAN_POINT('',(-7.88263929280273,45.1537214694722,41.5328183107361));
#1243=CARTESIAN_POINT('',(-7.67013182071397,45.4222887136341,41.5939891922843));
#1244=CARTESIAN_POINT('',(-7.48890844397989,45.6327511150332,41.6416267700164));
#1245=CARTESIAN_POINT('',(-7.10900674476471,46.0384182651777,41.7329639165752));
#1246=CARTESIAN_POINT('',(-6.9103168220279,46.2336127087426,41.7766608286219));
#1247=CARTESIAN_POINT('',(-6.49670797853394,46.6072661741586,41.8599129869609));
#1248=CARTESIAN_POINT('',(-6.28177818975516,46.7857138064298,41.8994654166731));
#1249=CARTESIAN_POINT('',(-5.83736569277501,47.1242312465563,41.9741842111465));
#1250=CARTESIAN_POINT('',(-5.60789129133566,47.2843114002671,42.00935304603));
#1251=CARTESIAN_POINT('',(-5.18373496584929,47.5544536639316,42.068488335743));
#1252=CARTESIAN_POINT('',(-4.99142563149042,47.6680780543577,42.093280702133));
#1253=CARTESIAN_POINT('',(-4.59942596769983,47.8822941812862,42.1399025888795));
#1254=CARTESIAN_POINT('',(-4.39973839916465,47.9828907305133,42.1617332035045));
#1255=CARTESIAN_POINT('',(-3.94769988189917,48.1918952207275,42.2069906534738));
#1256=CARTESIAN_POINT('',(-3.69368564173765,48.2968911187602,42.2296545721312));
#1257=CARTESIAN_POINT('',(-3.17743015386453,48.4857542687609,42.2703368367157));
#1258=CARTESIAN_POINT('',(-2.91518496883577,48.5696112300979,42.2883529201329));
#1259=CARTESIAN_POINT('',(-2.38405232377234,48.7155666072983,42.3196625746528));
#1260=CARTESIAN_POINT('',(-2.11515655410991,48.7776361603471,42.3329498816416));
#1261=CARTESIAN_POINT('',(-1.57308666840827,48.8793438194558,42.3547011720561));
#1262=CARTESIAN_POINT('',(-1.29991441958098,48.9189914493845,42.3631672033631));
#1263=CARTESIAN_POINT('',(-0.732227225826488,48.9775095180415,42.3756583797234));
#1264=CARTESIAN_POINT('',(-0.437536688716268,48.9947632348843,42.3793380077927));
#1265=CARTESIAN_POINT('',(0.151365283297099,49.0031892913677,42.3811329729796));
#1266=CARTESIAN_POINT('',(0.445575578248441,48.9944381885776,42.3792646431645));
#1267=CARTESIAN_POINT('',(0.738774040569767,48.9726733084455,42.3746246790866));
#1268=B_SPLINE_CURVE_WITH_KNOTS('',3,(#1240,#1241,#1242,#1243,#1244,#1245,#1246,#1247,#1248,
#1249,#1250,#1251,#1252,#1253,#1254,#1255,#1256,#1257,#1258,#1259,#1260,#1261,#1262,#1263,#1264,
#1265,#1266,#1267),.UNSPECIFIED.,.F.,.F.,(4,2,2,2,2,2,2,2,2,2,2,2,2,4),(0.,0.199291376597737,
1.04357386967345,1.88842138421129,2.73383938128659,3.5787788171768,4.25249918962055,
4.9259699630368,5.75234687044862,6.57912529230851,7.40699488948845,8.23451257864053,
9.11895028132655,10.000786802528),.UNSPECIFIED.);
#1269=EDGE_CURVE('E446',#1237,#1079,#1268,.T.);
#1270=ORIENTED_EDGE('',*,*,#1269,.T.);
#1271=ORIENTED_EDGE('',*,*,#1080,.F.);
#1272=CARTESIAN_POINT('',(4.19676130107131,48.0767392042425,42.1820549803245));
#1273=CARTESIAN_POINT('',(4.45388260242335,47.9578941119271,42.156318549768));
#1274=CARTESIAN_POINT('',(4.70571350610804,47.8281603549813,42.1281514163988));
#1275=CARTESIAN_POINT('',(5.1971405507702,47.5480728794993,42.0671043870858));
#1276=CARTESIAN_POINT('',(5.43673294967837,47.3977129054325,42.0342230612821));
#1277=CARTESIAN_POINT('',(5.89737309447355,47.0806992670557,41.9645919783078));
#1278=CARTESIAN_POINT('',(6.11868986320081,46.9144169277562,41.9279293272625));
#1279=CARTESIAN_POINT('',(6.54625857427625,46.5645714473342,41.8504189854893));
#1280=CARTESIAN_POINT('',(6.75251797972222,46.3810169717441,41.809573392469));
#1281=CARTESIAN_POINT('',(7.1095479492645,46.0358513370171,41.7323517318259));
#1282=CARTESIAN_POINT('',(7.26322749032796,45.8770752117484,41.6966882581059));
#1283=CARTESIAN_POINT('',(7.5606611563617,45.548733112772,41.6225973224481));
#1284=CARTESIAN_POINT('',(7.70432715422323,45.3790917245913,41.584150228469));
#1285=CARTESIAN_POINT('',(7.8420567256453,45.2050097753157,41.5445001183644));
#1286=B_SPLINE_CURVE_WITH_KNOTS('',3,(#1272,#1273,#1274,#1275,#1276,#1277,#1278,#1279,#1280,
#1281,#1282,#1283,#1284,#1285),.UNSPECIFIED.,.F.,.F.,(4,2,2,2,2,2,4),(0.,0.852995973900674,
1.70625121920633,2.54300585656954,3.37934290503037,4.05035350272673,4.72667188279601),.UNSPECIFIED.);
#1287=CARTESIAN_POINT('',(7.84189847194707,45.2052097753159,41.5445456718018));
#1288=VERTEX_POINT('',#1287);
#1289=EDGE_CURVE('E441',#1077,#1288,#1286,.T.);
#1290=ORIENTED_EDGE('',*,*,#1289,.T.);
#1291=CARTESIAN_POINT('',(40.56962997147,21.4271922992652,41.544583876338));
#1292=CARTESIAN_POINT('',(39.6946102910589,21.7518019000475,41.3779055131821));
#1293=CARTESIAN_POINT('',(38.8243581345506,22.0932404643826,41.2186579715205));
#1294=CARTESIAN_POINT('',(37.0945447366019,22.8096208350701,40.917421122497));
#1295=CARTESIAN_POINT('',(36.2349854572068,23.1845686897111,40.7754349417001));
#1296=CARTESIAN_POINT('',(34.5270055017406,23.9681659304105,40.5110206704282));
#1297=CARTESIAN_POINT('',(33.6785994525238,24.3768552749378,40.3886162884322));
#1298=CARTESIAN_POINT('',(31.9955129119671,25.2271479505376,40.1660688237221));
#1299=CARTESIAN_POINT('',(31.1608315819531,25.6687492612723,40.0659243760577));
#1300=CARTESIAN_POINT('',(29.5313297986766,26.5707507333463,39.892826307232));
#1301=CARTESIAN_POINT('',(28.7360616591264,27.0302034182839,39.8191536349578));
#1302=CARTESIAN_POINT('',(27.161522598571,27.9789348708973,39.696758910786));
#1303=CARTESIAN_POINT('',(26.3822518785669,28.4682140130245,39.648037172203));
#1304=CARTESIAN_POINT('',(24.8419638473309,29.4753462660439,39.5768683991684));
#1305=CARTESIAN_POINT('',(24.0809338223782,29.9931785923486,39.5544025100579));
#1306=CARTESIAN_POINT('',(22.5782613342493,31.0566601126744,39.5363126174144));
#1307=CARTESIAN_POINT('',(21.8366181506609,31.6023082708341,39.54068761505));
#1308=CARTESIAN_POINT('',(20.4919871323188,32.6302634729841,39.5732899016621));
#1309=CARTESIAN_POINT('',(19.8858879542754,33.1086381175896,39.5975665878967));
#1310=CARTESIAN_POINT('',(18.6893674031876,34.0833425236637,39.6644394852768));
#1311=CARTESIAN_POINT('',(18.0989456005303,34.5796717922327,39.707035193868));
#1312=CARTESIAN_POINT('',(16.934330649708,35.5897110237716,39.8097784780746));
#1313=CARTESIAN_POINT('',(16.3601437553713,36.103427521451,39.8699327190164));
#1314=CARTESIAN_POINT('',(15.2289521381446,37.1472415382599,40.0067290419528));
#1315=CARTESIAN_POINT('',(14.6719475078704,37.6773391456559,40.0833712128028));
#1316=CARTESIAN_POINT('',(12.9993140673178,39.318851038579,40.3405772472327));
#1317=CARTESIAN_POINT('',(11.9119323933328,40.4556016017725,40.5456950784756));
#1318=CARTESIAN_POINT('',(10.3404634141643,42.2048096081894,40.8928414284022));
#1319=CARTESIAN_POINT('',(9.82673138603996,42.7950273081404,41.0150890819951));
#1320=CARTESIAN_POINT('',(8.81923149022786,43.9896771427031,41.2713555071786));
#1321=CARTESIAN_POINT('',(8.32546167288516,44.5941078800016,41.4053731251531));
#1322=CARTESIAN_POINT('',(7.84174021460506,45.2054097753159,41.5445912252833));
#1323=B_SPLINE_CURVE_WITH_KNOTS('',3,(#1291,#1292,#1293,#1294,#1295,#1296,#1297,#1298,#1299,
#1300,#1301,#1302,#1303,#1304,#1305,#1306,#1307,#1308,#1309,#1310,#1311,#1312,#1313,#1314,#1315,
#1316,#1317,#1318,#1319,#1320,#1321,#1322),.UNSPECIFIED.,.F.,.F.,(4,2,2,2,2,2,2,2,2,2,2,2,2,2,2,
4),(0.,2.8440645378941,5.68864345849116,8.53664077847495,11.3844634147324,14.1477298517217,
16.9110309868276,19.6723465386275,22.4335593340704,24.7505470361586,27.067471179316,
29.3852759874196,31.7030932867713,36.4572896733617,38.8328466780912,41.2081711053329),.UNSPECIFIED.);
#1324=CARTESIAN_POINT('',(40.56942997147,21.4272664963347,41.5445457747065));
#1325=VERTEX_POINT('',#1324);
#1326=EDGE_CURVE('E434',#1325,#1288,#1323,.T.);
#1327=ORIENTED_EDGE('',*,*,#1326,.F.);
#1328=CARTESIAN_POINT('',(38.5811362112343,21.9400449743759,41.1433896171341));
#1329=CARTESIAN_POINT('',(38.7498552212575,21.9146218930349,41.1793204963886));
#1330=CARTESIAN_POINT('',(38.9180147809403,21.8848682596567,41.2146480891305));
#1331=CARTESIAN_POINT('',(39.2528528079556,21.8167274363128,41.2840509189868));
#1332=CARTESIAN_POINT('',(39.4195311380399,21.7783394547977,41.3181260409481));
#1333=CARTESIAN_POINT('',(39.9177013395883,21.6500296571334,41.4185852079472));
#1334=CARTESIAN_POINT('',(40.2463602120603,21.5471074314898,41.4829972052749));
#1335=CARTESIAN_POINT('',(40.8294061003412,21.3308298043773,41.5940742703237));
#1336=CARTESIAN_POINT('',(41.085823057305,21.223380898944,41.6417567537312));
#1337=CARTESIAN_POINT('',(41.5895137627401,20.9871301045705,41.7331747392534));
#1338=CARTESIAN_POINT('',(41.8367841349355,20.8583204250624,41.7769087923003));
#1339=CARTESIAN_POINT('',(42.3198817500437,20.5803501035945,41.860137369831));
#1340=CARTESIAN_POINT('',(42.5557242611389,20.431217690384,41.8996376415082));
#1341=CARTESIAN_POINT('',(43.014473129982,20.1134660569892,41.9742647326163));
#1342=CARTESIAN_POINT('',(43.2373862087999,19.9448571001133,42.0093938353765));
#1343=CARTESIAN_POINT('',(43.6251894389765,19.6250942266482,42.0685002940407));
#1344=CARTESIAN_POINT('',(43.7927185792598,19.4772719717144,42.0932982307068));
#1345=CARTESIAN_POINT('',(44.1175864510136,19.1706350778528,42.1399190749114));
#1346=CARTESIAN_POINT('',(44.2749352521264,19.0118316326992,42.1617449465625));
#1347=CARTESIAN_POINT('',(44.4327777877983,18.8414619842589,42.182850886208));
#1348=CARTESIAN_POINT('',(44.4387216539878,18.8350294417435,42.1836444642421));
#1349=CARTESIAN_POINT('',(44.6226844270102,18.6354160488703,42.2081682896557));
#1350=CARTESIAN_POINT('',(44.7933005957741,18.4349939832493,42.2298249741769));
#1351=CARTESIAN_POINT('',(45.1184497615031,18.0209749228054,42.2688792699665));
#1352=CARTESIAN_POINT('',(45.2729720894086,17.8073693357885,42.2862740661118));
#1353=CARTESIAN_POINT('',(45.5651424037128,17.3678779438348,42.3167539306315));
#1354=CARTESIAN_POINT('',(45.7027502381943,17.1419646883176,42.32982886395));
#1355=CARTESIAN_POINT('',(45.9597152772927,16.6797763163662,42.3515548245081));
#1356=CARTESIAN_POINT('',(46.0790716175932,16.4435007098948,42.3602056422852));
#1357=CARTESIAN_POINT('',(46.3033061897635,15.9520640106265,42.3733134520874));
#1358=CARTESIAN_POINT('',(46.4073714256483,15.6965263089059,42.3775801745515));
#1359=CARTESIAN_POINT('',(46.5940480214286,15.1776794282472,42.3812502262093));
#1360=CARTESIAN_POINT('',(46.6766578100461,14.9143696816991,42.3806531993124));
#1361=CARTESIAN_POINT('',(46.8197931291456,14.3820046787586,42.3745994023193));
#1362=CARTESIAN_POINT('',(46.8803292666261,14.1129522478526,42.3691449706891));
#1363=CARTESIAN_POINT('',(46.9789628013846,13.5709101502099,42.3534055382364));
#1364=CARTESIAN_POINT('',(47.0170605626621,13.2979205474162,42.34312061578));
#1365=CARTESIAN_POINT('',(47.0705924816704,12.7499436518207,42.3177686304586));
#1366=CARTESIAN_POINT('',(47.0860261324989,12.4749563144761,42.3027014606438));
#1367=CARTESIAN_POINT('',(47.0941831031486,11.9249439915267,42.2678560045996));
#1368=CARTESIAN_POINT('',(47.0869063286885,11.6499190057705,42.2480776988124));
#1369=CARTESIAN_POINT('',(47.0497784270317,11.1017964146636,42.2039046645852));
#1370=CARTESIAN_POINT('',(47.019929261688,10.8286986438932,42.1795103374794));
#1371=CARTESIAN_POINT('',(46.9379682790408,10.2863123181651,42.12621783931));
#1372=CARTESIAN_POINT('',(46.8858564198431,10.0170237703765,42.097319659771));
#1373=CARTESIAN_POINT('',(46.7594977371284,9.48263588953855,42.0349810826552));
#1374=CARTESIAN_POINT('',(46.6851300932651,9.21756796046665,42.0015164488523));
#1375=CARTESIAN_POINT('',(46.515012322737,8.69497509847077,41.9303237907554));
#1376=CARTESIAN_POINT('',(46.419262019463,8.43745022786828,41.8925957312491));
#1377=CARTESIAN_POINT('',(46.2071290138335,7.93156864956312,41.8130329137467));
#1378=CARTESIAN_POINT('',(46.0907373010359,7.68321600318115,41.7711963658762));
#1379=CARTESIAN_POINT('',(45.8382837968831,7.19743461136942,41.6836216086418));
#1380=CARTESIAN_POINT('',(45.7022215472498,6.96000612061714,41.6378833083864));
#1381=CARTESIAN_POINT('',(45.4088842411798,6.4934732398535,41.5418618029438));
#1382=CARTESIAN_POINT('',(45.2512731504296,6.26459384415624,41.4915119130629));
#1383=CARTESIAN_POINT('',(44.9179977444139,5.82123516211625,41.3872206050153));
#1384=CARTESIAN_POINT('',(44.7423323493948,5.60675673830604,41.3332789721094));
#1385=CARTESIAN_POINT('',(44.3743102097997,5.19361252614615,41.2220651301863));
#1386=CARTESIAN_POINT('',(44.1819551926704,4.99494510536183,41.1647932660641));
#1387=CARTESIAN_POINT('',(43.7819999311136,4.61462434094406,41.0471925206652));
#1388=CARTESIAN_POINT('',(43.5744010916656,4.43296943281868,40.9868639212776));
#1389=CARTESIAN_POINT('',(43.3598932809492,4.26041535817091,40.9251409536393));
#1390=B_SPLINE_CURVE_WITH_KNOTS('',3,(#1328,#1329,#1330,#1331,#1332,#1333,#1334,#1335,#1336,
#1337,#1338,#1339,#1340,#1341,#1342,#1343,#1344,#1345,#1346,#1347,#1348,#1349,#1350,#1351,#1352,
#1353,#1354,#1355,#1356,#1357,#1358,#1359,#1360,#1361,#1362,#1363,#1364,#1365,#1366,#1367,#1368,
#1369,#1370,#1371,#1372,#1373,#1374,#1375,#1376,#1377,#1378,#1379,#1380,#1381,#1382,#1383,#1384,
#1385,#1386,#1387,#1388,#1389),.UNSPECIFIED.,.F.,.F.,(4,2,2,2,2,2,2,2,2,2,2,2,2,2,2,2,2,2,2,2,2,
2,2,2,2,2,2,2,2,2,4),(0.,0.52297250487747,1.04599297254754,2.09502156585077,2.94035374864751,
3.7859949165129,4.63047321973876,5.47450853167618,6.14842143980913,6.82165723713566,
6.84803987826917,7.63933379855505,8.43114899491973,9.22480893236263,10.0185064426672,
10.8453567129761,11.6722675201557,12.4987804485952,13.3252799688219,14.1517979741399,
14.9783194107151,15.8047690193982,16.6312201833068,17.4622419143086,18.2932705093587,
19.1246627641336,19.9560743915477,20.8023642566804,21.6487047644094,22.4949577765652,
23.3411328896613),.UNSPECIFIED.);
#1391=EDGE_CURVE('E683',#1325,#847,#1390,.T.);
#1392=ORIENTED_EDGE('',*,*,#1391,.T.);
#1393=ORIENTED_EDGE('',*,*,#880,.F.);
#1394=CARTESIAN_POINT('',(45.4159899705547,6.51109053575,41.5445459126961));
#1395=VERTEX_POINT('',#1394);
#1396=EDGE_CURVE('E426',#872,#1395,#1390,.T.);
#1397=ORIENTED_EDGE('',*,*,#1396,.T.);
#1398=CARTESIAN_POINT('',(32.9151764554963,-31.9626327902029,41.5445818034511));
#1399=CARTESIAN_POINT('',(32.9535027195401,-31.0301298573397,41.3779035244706));
#1400=CARTESIAN_POINT('',(33.0093075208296,-30.0969606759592,41.2186560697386));
#1401=CARTESIAN_POINT('',(33.1560842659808,-28.2304369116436,40.917419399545));
#1402=CARTESIAN_POINT('',(33.2470625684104,-27.2970823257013,40.7754333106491));
#1403=CARTESIAN_POINT('',(33.4645132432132,-25.4305522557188,40.5110192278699));
#1404=CARTESIAN_POINT('',(33.5910281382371,-24.4973783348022,40.3886149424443));
#1405=CARTESIAN_POINT('',(33.8796024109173,-22.6339132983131,40.1660676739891));
#1406=CARTESIAN_POINT('',(34.0416596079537,-21.7036220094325,40.0659233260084));
#1407=CARTESIAN_POINT('',(34.3959704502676,-19.8751401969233,39.8928254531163));
#1408=CARTESIAN_POINT('',(34.5871846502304,-18.9768166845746,39.8191528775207));
#1409=CARTESIAN_POINT('',(35.0029227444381,-17.1861671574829,39.6967583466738));
#1410=CARTESIAN_POINT('',(35.2274470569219,-16.293841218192,39.6480367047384));
#1411=CARTESIAN_POINT('',(35.7093117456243,-14.5177195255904,39.5768681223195));
#1412=CARTESIAN_POINT('',(35.9666284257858,-13.6339181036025,39.5544023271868));
#1413=CARTESIAN_POINT('',(36.5137082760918,-11.8761580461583,39.5363126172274));
#1414=CARTESIAN_POINT('',(36.8034702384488,-11.0021990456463,39.5406877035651));
#1415=CARTESIAN_POINT('',(37.3655997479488,-9.40572435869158,39.5732901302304));
#1416=CARTESIAN_POINT('',(37.6332658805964,-8.68146477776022,39.5975668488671));
#1417=CARTESIAN_POINT('',(38.1905191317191,-7.24230763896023,39.6644397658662));
#1418=CARTESIAN_POINT('',(38.4801056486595,-6.52740982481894,39.707035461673));
#1419=CARTESIAN_POINT('',(39.0808235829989,-5.10767761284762,39.8097786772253));
#1420=CARTESIAN_POINT('',(39.3919631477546,-4.40284714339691,39.8699328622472));
#1421=CARTESIAN_POINT('',(40.0351310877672,-3.00446538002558,40.0067290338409));
#1422=CARTESIAN_POINT('',(40.3671595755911,-2.31091414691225,40.0833711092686));
#1423=CARTESIAN_POINT('',(41.4114566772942,-0.212892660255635,40.3405767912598));
#1424=CARTESIAN_POINT('',(42.1565502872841,1.17254235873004,40.5456943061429));
#1425=CARTESIAN_POINT('',(43.3345336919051,3.20763081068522,40.8928400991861));
#1426=CARTESIAN_POINT('',(43.7371115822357,3.87860553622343,41.015087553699));
#1427=CARTESIAN_POINT('',(44.5619553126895,5.20596048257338,41.2713535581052));
#1428=CARTESIAN_POINT('',(44.9842192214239,5.86234212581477,41.4053709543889));
#1429=CARTESIAN_POINT('',(45.4161230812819,6.51129053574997,41.544588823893));
#1430=B_SPLINE_CURVE_WITH_KNOTS('',3,(#1398,#1399,#1400,#1401,#1402,#1403,#1404,#1405,#1406,
#1407,#1408,#1409,#1410,#1411,#1412,#1413,#1414,#1415,#1416,#1417,#1418,#1419,#1420,#1421,#1422,
#1423,#1424,#1425,#1426,#1427,#1428,#1429),.UNSPECIFIED.,.F.,.F.,(4,2,2,2,2,2,2,2,2,2,2,2,2,2,2,
4),(0.,2.84406415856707,5.68864269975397,8.53663963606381,11.3844618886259,14.1477280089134,
16.9110288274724,19.6723440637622,22.4335565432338,24.7505415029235,27.0674629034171,
29.3852649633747,31.7030795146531,36.4572700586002,38.8328241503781,41.2081456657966),.UNSPECIFIED.);
#1431=CARTESIAN_POINT('',(32.9151846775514,-31.9624327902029,41.5445460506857));
#1432=VERTEX_POINT('',#1431);
#1433=EDGE_CURVE('E418',#1432,#1395,#1430,.T.);
#1434=ORIENTED_EDGE('',*,*,#1433,.F.);
#1435=CARTESIAN_POINT('',(32.5694068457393,-28.9136920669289,40.9206393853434));
#1436=CARTESIAN_POINT('',(32.6367544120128,-29.1598747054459,40.9779277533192));
#1437=CARTESIAN_POINT('',(32.6947117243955,-29.4089100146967,41.0340210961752));
#1438=CARTESIAN_POINT('',(32.791469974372,-29.9112490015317,41.1436010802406));
#1439=CARTESIAN_POINT('',(32.8302701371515,-30.1645528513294,41.1970876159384));
#1440=CARTESIAN_POINT('',(32.8884059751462,-30.6746145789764,41.3013640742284));
#1441=CARTESIAN_POINT('',(32.9076922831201,-30.9313795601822,41.3521468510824));
#1442=CARTESIAN_POINT('',(32.9263857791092,-31.4462110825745,41.4506631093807));
#1443=CARTESIAN_POINT('',(32.9257930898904,-31.7042776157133,41.4983966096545));
#1444=CARTESIAN_POINT('',(32.9037921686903,-32.2396689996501,41.5941065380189));
#1445=CARTESIAN_POINT('',(32.8808153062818,-32.5169763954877,41.6418290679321));
#1446=CARTESIAN_POINT('',(32.8117030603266,-33.0693535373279,41.7332973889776));
#1447=CARTESIAN_POINT('',(32.7655675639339,-33.3444232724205,41.7770431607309));
#1448=CARTESIAN_POINT('',(32.6504457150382,-33.8897002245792,41.8602519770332));
#1449=CARTESIAN_POINT('',(32.5815138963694,-34.1599174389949,41.8997249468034));
#1450=CARTESIAN_POINT('',(32.421143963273,-34.6940895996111,41.9743044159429));
#1451=CARTESIAN_POINT('',(32.3297160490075,-34.9580473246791,42.0094128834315));
#1452=CARTESIAN_POINT('',(32.1455420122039,-35.425420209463,42.0684858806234));
#1453=CARTESIAN_POINT('',(32.0567785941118,-35.6303115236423,42.0932700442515));
#1454=CARTESIAN_POINT('',(31.8655724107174,-36.0340135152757,42.1398914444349));
#1455=CARTESIAN_POINT('',(31.76312658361,-36.232822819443,42.1617280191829));
#1456=CARTESIAN_POINT('',(31.5202753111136,-36.6676019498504,42.2069843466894));
#1457=CARTESIAN_POINT('',(31.3765270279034,-36.9017935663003,42.2296430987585));
#1458=CARTESIAN_POINT('',(31.0699703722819,-37.3579191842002,42.2703169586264));
#1459=CARTESIAN_POINT('',(30.9071531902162,-37.5798474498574,42.288329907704));
#1460=CARTESIAN_POINT('',(30.5633381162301,-38.0100437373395,42.3196377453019));
#1461=CARTESIAN_POINT('',(30.3823145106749,-38.2182917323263,42.3329258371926));
#1462=CARTESIAN_POINT('',(30.003637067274,-38.6191572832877,42.3546811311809));
#1463=CARTESIAN_POINT('',(29.8059888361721,-38.8117800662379,42.3631499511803));
#1464=CARTESIAN_POINT('',(29.3278440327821,-39.2406196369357,42.3772150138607));
#1465=CARTESIAN_POINT('',(29.0414432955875,-39.47040098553,42.3809568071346));
#1466=CARTESIAN_POINT('',(28.5948199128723,-39.7900507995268,42.380121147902));
#1467=CARTESIAN_POINT('',(28.4432955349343,-39.8923253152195,42.3787731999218));
#1468=CARTESIAN_POINT('',(28.134867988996,-40.0884256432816,42.3739430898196));
#1469=CARTESIAN_POINT('',(27.9779638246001,-40.1822498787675,42.3704605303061));
#1470=CARTESIAN_POINT('',(27.8185901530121,-40.2717152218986,42.3659136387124));
#1471=B_SPLINE_CURVE_WITH_KNOTS('',3,(#1435,#1436,#1437,#1438,#1439,#1440,#1441,#1442,#1443,
#1444,#1445,#1446,#1447,#1448,#1449,#1450,#1451,#1452,#1453,#1454,#1455,#1456,#1457,#1458,#1459,
#1460,#1461,#1462,#1463,#1464,#1465,#1466,#1467,#1468,#1469,#1470),.UNSPECIFIED.,.F.,.F.,(4,2,2,
2,2,2,2,2,2,2,2,2,2,2,2,2,2,4),(0.,0.78455960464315,1.56915093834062,2.35572224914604,
3.14228870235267,3.98825744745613,4.83423031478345,5.67819389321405,6.5217755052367,
7.19526700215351,7.86890946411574,8.69507721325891,9.52162816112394,10.3493633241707,
11.1768204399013,12.2757948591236,12.8240012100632,13.3723096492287),.UNSPECIFIED.);
#1472=EDGE_CURVE('E411',#1432,#937,#1471,.T.);
#1473=ORIENTED_EDGE('',*,*,#1472,.T.);
#1474=ORIENTED_EDGE('',*,*,#965,.F.);
#1475=CARTESIAN_POINT('',(24.8635470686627,-41.361693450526,42.1820549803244));
#1476=CARTESIAN_POINT('',(24.5856762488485,-41.416677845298,42.1563185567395));
#1477=CARTESIAN_POINT('',(24.3056852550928,-41.459743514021,42.1281514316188));
#1478=CARTESIAN_POINT('',(23.7434812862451,-41.5220015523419,42.0671044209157));
#1479=CARTESIAN_POINT('',(23.461267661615,-41.5411866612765,42.0342231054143));
#1480=CARTESIAN_POINT('',(22.902266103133,-41.5554747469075,41.9645920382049));
#1481=CARTESIAN_POINT('',(22.6254787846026,-41.5510362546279,41.9279293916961));
#1482=CARTESIAN_POINT('',(22.0739344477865,-41.5193239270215,41.8504190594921));
#1483=CARTESIAN_POINT('',(21.7991764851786,-41.4920614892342,41.8095734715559));
#1484=CARTESIAN_POINT('',(21.3074578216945,-41.4226747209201,41.7323530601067));
#1485=CARTESIAN_POINT('',(21.0898100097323,-41.3845543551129,41.6966909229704));
#1486=CARTESIAN_POINT('',(20.6562019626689,-41.2937514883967,41.6226028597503));
#1487=CARTESIAN_POINT('',(20.4402686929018,-41.2409561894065,41.5841573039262));
#1488=CARTESIAN_POINT('',(20.2265277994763,-41.1810795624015,41.5445088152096));
#1489=B_SPLINE_CURVE_WITH_KNOTS('',3,(#1475,#1476,#1477,#1478,#1479,#1480,#1481,#1482,#1483,
#1484,#1485,#1486,#1487,#1488),.UNSPECIFIED.,.F.,.F.,(4,2,2,2,2,2,4),(0.,0.852995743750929,
1.70625076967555,2.54300536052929,3.37934235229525,4.05032872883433,4.72662244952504),.UNSPECIFIED.);
#1490=CARTESIAN_POINT('',(20.2267277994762,-41.1811355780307,41.5445459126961));
#1491=VERTEX_POINT('',#1490);
#1492=EDGE_CURVE('E403',#962,#1491,#1489,.T.);
#1493=ORIENTED_EDGE('',*,*,#1492,.T.);
#1494=CARTESIAN_POINT('',(-20.2269284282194,-41.1811917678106,41.5445831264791));
#1495=CARTESIAN_POINT('',(-19.3282219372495,-40.929482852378,41.3779047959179));
#1496=CARTESIAN_POINT('',(-18.4234806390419,-40.6941911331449,41.218657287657));
#1497=CARTESIAN_POINT('',(-16.6029544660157,-40.2569963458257,40.9174205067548));
#1498=CARTESIAN_POINT('',(-15.6871676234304,-40.0550993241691,40.775434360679));
#1499=CARTESIAN_POINT('',(-13.8447959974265,-39.6851174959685,40.5110201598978));
#1500=CARTESIAN_POINT('',(-12.9181995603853,-39.517073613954,40.388615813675));
#1501=CARTESIAN_POINT('',(-11.0567645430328,-39.2156815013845,40.1660684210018));
#1502=CARTESIAN_POINT('',(-10.1219264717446,-39.0823311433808,40.0659240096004));
#1503=CARTESIAN_POINT('',(-8.27344874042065,-38.8542686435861,39.8928260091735));
#1504=CARTESIAN_POINT('',(-7.36000380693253,-38.7585268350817,39.8191533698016));
#1505=CARTESIAN_POINT('',(-5.52852463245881,-38.6005759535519,39.6967587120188));
#1506=CARTESIAN_POINT('',(-4.61049033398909,-38.5383673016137,39.6480370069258));
#1507=CARTESIAN_POINT('',(-2.77239370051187,-38.4477959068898,39.5768683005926));
#1508=CARTESIAN_POINT('',(-1.85233329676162,-38.4194088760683,39.5544024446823));
#1509=CARTESIAN_POINT('',(-0.0115470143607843,-38.3965348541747,39.5363126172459));
#1510=CARTESIAN_POINT('',(0.909178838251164,-38.4020466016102,39.5406876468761));
#1511=CARTESIAN_POINT('',(2.60122304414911,-38.4433255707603,39.5732899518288));
#1512=CARTESIAN_POINT('',(3.37274712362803,-38.4740825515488,39.5975665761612));
#1513=CARTESIAN_POINT('',(4.9136654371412,-38.5593375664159,39.664439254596));
#1514=CARTESIAN_POINT('',(5.68305972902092,-38.6138349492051,39.7070348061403));
#1515=CARTESIAN_POINT('',(7.21893518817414,-38.7464298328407,39.8097776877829));
#1516=CARTESIAN_POINT('',(7.98541513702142,-38.8245362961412,39.8699316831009));
#1517=CARTESIAN_POINT('',(9.51410291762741,-39.0041010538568,40.0067274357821));
#1518=CARTESIAN_POINT('',(10.27631072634,-39.1055594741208,40.083369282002));
#1519=CARTESIAN_POINT('',(12.5943500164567,-39.4504196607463,40.3405742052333));
#1520=CARTESIAN_POINT('',(14.1422214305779,-39.7309219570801,40.5456911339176));
#1521=CARTESIAN_POINT('',(16.4417192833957,-40.2223723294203,40.8928359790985));
#1522=CARTESIAN_POINT('',(17.2042565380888,-40.3979035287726,41.0150831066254));
#1523=CARTESIAN_POINT('',(18.7215347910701,-40.7722001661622,41.2713484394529));
#1524=CARTESIAN_POINT('',(19.4762765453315,-40.9709633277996,41.4053654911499));
#1525=CARTESIAN_POINT('',(20.2269277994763,-41.1811915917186,41.5445830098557));
#1526=B_SPLINE_CURVE_WITH_KNOTS('',3,(#1494,#1495,#1496,#1497,#1498,#1499,#1500,#1501,#1502,
#1503,#1504,#1505,#1506,#1507,#1508,#1509,#1510,#1511,#1512,#1513,#1514,#1515,#1516,#1517,#1518,
#1519,#1520,#1521,#1522,#1523,#1524,#1525),.UNSPECIFIED.,.F.,.F.,(4,2,2,2,2,2,2,2,2,2,2,2,2,2,2,
4),(0.,2.84406436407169,5.68864311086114,8.53664025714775,11.384462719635,14.1477290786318,
16.9110301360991,19.6723456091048,22.4335583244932,24.7505399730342,27.0674580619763,
29.3852568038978,31.7030680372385,36.4572515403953,38.8328021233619,41.2081201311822),.UNSPECIFIED.);
#1527=CARTESIAN_POINT('',(-20.2267284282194,-41.1811357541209,41.5445460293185));
#1528=VERTEX_POINT('',#1527);
#1529=EDGE_CURVE('E395',#1528,#1491,#1526,.T.);
#1530=ORIENTED_EDGE('',*,*,#1529,.F.);
#1531=CARTESIAN_POINT('',(-19.1284327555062,-40.8035013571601,41.3259799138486));
#1532=CARTESIAN_POINT('',(-19.3070511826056,-40.8767769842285,41.3640725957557));
#1533=CARTESIAN_POINT('',(-19.487931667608,-40.9449276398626,41.4013317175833));
#1534=CARTESIAN_POINT('',(-19.854142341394,-41.070898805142,41.4742048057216));
#1535=CARTESIAN_POINT('',(-20.039483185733,-41.1286910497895,41.509814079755));
#1536=CARTESIAN_POINT('',(-20.4935422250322,-41.2558664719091,41.5940370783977));
#1537=CARTESIAN_POINT('',(-20.7640293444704,-41.3196415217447,41.6417017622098));
#1538=CARTESIAN_POINT('',(-21.3101535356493,-41.4245589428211,41.7330868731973));
#1539=CARTESIAN_POINT('',(-21.5857933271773,-41.4656889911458,41.7768051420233));
#1540=CARTESIAN_POINT('',(-22.1400306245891,-41.5248071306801,41.8600443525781));
#1541=CARTESIAN_POINT('',(-22.4186265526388,-41.5428069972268,41.8995674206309));
#1542=CARTESIAN_POINT('',(-22.9767939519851,-41.5554141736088,41.9742337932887));
#1543=CARTESIAN_POINT('',(-23.2563647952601,-41.5500344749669,42.0093795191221));
#1544=CARTESIAN_POINT('',(-23.7582019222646,-41.5192757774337,42.0685029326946));
#1545=CARTESIAN_POINT('',(-23.9806432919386,-41.4981532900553,42.0933028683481));
#1546=CARTESIAN_POINT('',(-24.4236853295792,-41.4410324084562,42.1399215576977));
#1547=CARTESIAN_POINT('',(-24.6442878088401,-41.4050510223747,42.1617436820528));
#1548=CARTESIAN_POINT('',(-25.0094399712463,-41.3328437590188,42.1955699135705));
#1549=CARTESIAN_POINT('',(-25.154738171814,-41.3007283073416,42.2084159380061));
#1550=CARTESIAN_POINT('',(-25.4439536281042,-41.2299953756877,42.2327628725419));
#1551=CARTESIAN_POINT('',(-25.5878699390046,-41.1913737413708,42.2442629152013));
#1552=CARTESIAN_POINT('',(-25.9840663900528,-41.0754874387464,42.2742195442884));
#1553=CARTESIAN_POINT('',(-26.2344872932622,-40.9913611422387,42.2912170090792));
#1554=CARTESIAN_POINT('',(-26.7282025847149,-40.8034199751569,42.320847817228));
#1555=CARTESIAN_POINT('',(-26.9714935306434,-40.6995957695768,42.3334790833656));
#1556=CARTESIAN_POINT('',(-27.449658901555,-40.4727140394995,42.3543321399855));
#1557=CARTESIAN_POINT('',(-27.6845180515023,-40.3496235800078,42.3625462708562));
#1558=CARTESIAN_POINT('',(-28.1438090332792,-40.0851212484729,42.3744952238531));
#1559=CARTESIAN_POINT('',(-28.3682404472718,-39.9437086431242,42.3782298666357));
#1560=CARTESIAN_POINT('',(-28.8143667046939,-39.6371711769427,42.3812653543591));
#1561=CARTESIAN_POINT('',(-29.0355504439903,-39.4712997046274,42.3803733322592));
#1562=CARTESIAN_POINT('',(-29.4633952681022,-39.1218479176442,42.3737109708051));
#1563=CARTESIAN_POINT('',(-29.6700554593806,-38.9382665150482,42.3679403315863));
#1564=CARTESIAN_POINT('',(-30.0672656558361,-38.5548441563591,42.3515525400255));
#1565=CARTESIAN_POINT('',(-30.2578246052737,-38.3550123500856,42.3409380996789));
#1566=CARTESIAN_POINT('',(-30.6216333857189,-37.9404591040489,42.3149138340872));
#1567=CARTESIAN_POINT('',(-30.7948831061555,-37.7257375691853,42.2995039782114));
#1568=CARTESIAN_POINT('',(-31.1228298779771,-37.28305770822,42.263968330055));
#1569=CARTESIAN_POINT('',(-31.2775337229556,-37.0551042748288,42.2438442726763));
#1570=CARTESIAN_POINT('',(-31.5674387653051,-36.5875485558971,42.1989715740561));
#1571=CARTESIAN_POINT('',(-31.7026397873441,-36.3479461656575,42.1742228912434));
#1572=CARTESIAN_POINT('',(-31.9527367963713,-35.858709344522,42.1202032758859));
#1573=CARTESIAN_POINT('',(-32.0676226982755,-35.6090700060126,42.0909301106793));
#1574=CARTESIAN_POINT('',(-32.2763099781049,-35.1016676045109,42.0280066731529));
#1575=CARTESIAN_POINT('',(-32.3701114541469,-34.8439045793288,41.9943564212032));
#1576=CARTESIAN_POINT('',(-32.5367392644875,-34.3200820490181,41.9225590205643));
#1577=CARTESIAN_POINT('',(-32.6093991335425,-34.0539740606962,41.8843793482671));
#1578=CARTESIAN_POINT('',(-32.7324106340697,-33.5172511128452,41.8039085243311));
#1579=CARTESIAN_POINT('',(-32.7827611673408,-33.2466359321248,41.7616171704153));
#1580=CARTESIAN_POINT('',(-32.8609416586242,-32.7028173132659,41.6731199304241));
#1581=CARTESIAN_POINT('',(-32.8887721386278,-32.4296139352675,41.6269141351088));
#1582=CARTESIAN_POINT('',(-32.9219141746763,-31.8825117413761,41.5308063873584));
#1583=CARTESIAN_POINT('',(-32.9272273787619,-31.6086129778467,41.4809047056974));
#1584=CARTESIAN_POINT('',(-32.9212838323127,-31.3352958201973,41.4292612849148));
#1585=B_SPLINE_CURVE_WITH_KNOTS('',3,(#1531,#1532,#1533,#1534,#1535,#1536,#1537,#1538,#1539,
#1540,#1541,#1542,#1543,#1544,#1545,#1546,#1547,#1548,#1549,#1550,#1551,#1552,#1553,#1554,#1555,
#1556,#1557,#1558,#1559,#1560,#1561,#1562,#1563,#1564,#1565,#1566,#1567,#1568,#1569,#1570,#1571,
#1572,#1573,#1574,#1575,#1576,#1577,#1578,#1579,#1580,#1581,#1582,#1583,#1584),.UNSPECIFIED.,
.F.,.F.,(4,2,2,2,2,2,2,2,2,2,2,2,2,2,2,2,2,2,2,2,2,2,2,2,2,2,4),(0.,0.590244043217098,
1.18207494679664,2.02693480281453,2.87225395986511,3.71714260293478,4.5615618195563,
5.23551729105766,5.90870345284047,6.35663474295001,6.8048531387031,7.5980865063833,
8.39169673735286,9.18667874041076,9.98169257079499,10.8101069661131,11.6385722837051,
12.4665743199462,13.294581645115,14.1222847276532,14.9499952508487,15.7781155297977,
16.606231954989,17.4407025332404,18.275214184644,19.1097064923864,19.9441377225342),.UNSPECIFIED.);
#1586=EDGE_CURVE('E662',#1528,#990,#1585,.T.);
#1587=ORIENTED_EDGE('',*,*,#1586,.T.);
#1588=ORIENTED_EDGE('',*,*,#1018,.F.);
#1589=CARTESIAN_POINT('',(-32.9151846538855,-31.9624333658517,41.5445461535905));
#1590=VERTEX_POINT('',#1589);
#1591=EDGE_CURVE('E379',#1015,#1590,#1585,.T.);
#1592=ORIENTED_EDGE('',*,*,#1591,.T.);
#1593=CARTESIAN_POINT('',(-45.4161234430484,6.51129107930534,41.5445889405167));
#1594=CARTESIAN_POINT('',(-44.899017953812,5.73435271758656,41.3779103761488));
#1595=CARTESIAN_POINT('',(-44.3956612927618,4.94660170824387,41.2186626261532));
#1596=CARTESIAN_POINT('',(-43.4172898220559,3.3502789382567,40.9174253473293));
#1597=CARTESIAN_POINT('',(-42.9422801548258,2.54170343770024,40.7754389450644));
#1598=CARTESIAN_POINT('',(-42.0210814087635,0.903834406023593,40.5110242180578));
#1599=CARTESIAN_POINT('',(-41.5749276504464,0.074517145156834,40.3886196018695));
#1600=CARTESIAN_POINT('',(-40.7130707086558,-1.60267769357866,40.1660716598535));
#1601=CARTESIAN_POINT('',(-40.2973656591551,-2.45055412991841,40.0659269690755));
#1602=CARTESIAN_POINT('',(-39.5092533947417,-4.13808598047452,39.8928284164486));
#1603=CARTESIAN_POINT('',(-39.1359270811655,-4.97723801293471,39.8191555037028));
#1604=CARTESIAN_POINT('',(-38.4197478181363,-6.67026897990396,39.6967602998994));
#1605=CARTESIAN_POINT('',(-38.0768952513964,-7.52414809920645,39.6480383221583));
#1606=CARTESIAN_POINT('',(-37.4227528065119,-9.24429410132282,39.5768690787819));
#1607=CARTESIAN_POINT('',(-37.1114404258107,-10.1105516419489,39.554402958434));
#1608=CARTESIAN_POINT('',(-36.5208508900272,-11.85417534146,39.5363126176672));
#1609=CARTESIAN_POINT('',(-36.2415725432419,-12.7315410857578,39.5406873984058));
#1610=CARTESIAN_POINT('',(-35.7579599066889,-14.3535275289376,39.5732892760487));
#1611=CARTESIAN_POINT('',(-35.5487970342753,-15.0967956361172,39.5975657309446));
#1612=CARTESIAN_POINT('',(-35.1537085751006,-16.5886426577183,39.6644381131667));
#1613=CARTESIAN_POINT('',(-34.9677823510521,-17.3372214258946,39.7070335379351));
#1614=CARTESIAN_POINT('',(-34.6192751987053,-18.8389012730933,39.8097762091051));
#1615=CARTESIAN_POINT('',(-34.456703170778,-19.592003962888,39.8699301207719));
#1616=CARTESIAN_POINT('',(-34.1550882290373,-21.1013624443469,40.0067257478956));
#1617=CARTESIAN_POINT('',(-34.0160454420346,-21.8576182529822,40.0833675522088));
#1618=CARTESIAN_POINT('',(-33.627712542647,-24.1687745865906,40.3405724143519));
#1619=CARTESIAN_POINT('',(-33.4161670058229,-25.7275693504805,40.5456893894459));
#1620=CARTESIAN_POINT('',(-33.1729795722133,-28.0663906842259,40.8928344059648));
#1621=CARTESIAN_POINT('',(-33.1042825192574,-28.8458496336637,41.0150816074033));
#1622=CARTESIAN_POINT('',(-32.9913947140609,-30.4045326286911,41.2713471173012));
#1623=CARTESIAN_POINT('',(-32.9472015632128,-31.1837566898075,41.40536427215));
#1624=CARTESIAN_POINT('',(-32.915176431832,-31.9626333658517,41.5445819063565));
#1625=B_SPLINE_CURVE_WITH_KNOTS('',3,(#1593,#1594,#1595,#1596,#1597,#1598,#1599,#1600,#1601,
#1602,#1603,#1604,#1605,#1606,#1607,#1608,#1609,#1610,#1611,#1612,#1613,#1614,#1615,#1616,#1617,
#1618,#1619,#1620,#1621,#1622,#1623,#1624),.UNSPECIFIED.,.F.,.F.,(4,2,2,2,2,2,2,2,2,2,2,2,2,2,2,
4),(0.,2.84406538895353,5.68864516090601,8.53664334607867,11.3844668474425,14.1477341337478,
16.9110361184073,19.6723525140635,22.4335661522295,24.750550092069,27.0674704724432,
29.3852715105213,31.703085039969,36.457273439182,38.8328264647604,41.2081469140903),.UNSPECIFIED.);
#1626=CARTESIAN_POINT('',(-45.4159903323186,6.51109107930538,41.5445460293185));
#1627=VERTEX_POINT('',#1626);
#1628=EDGE_CURVE('E369',#1627,#1590,#1625,.T.);
#1629=ORIENTED_EDGE('',*,*,#1628,.F.);
#1630=EDGE_CURVE('E387',#1627,#1043,#1198,.T.);
#1631=ORIENTED_EDGE('',*,*,#1630,.T.);
#1632=EDGE_LOOP('',(#1137,#1202,#1239,#1270,#1271,#1290,#1327,#1392,#1393,#1397,#1434,#1473,
#1474,#1493,#1530,#1587,#1588,#1592,#1629,#1631));
#1633=FACE_BOUND('',#1632,.T.);
#1634=ADVANCED_FACE('F355',(#1136,#1633),#1133,.T.);
#1635=CARTESIAN_POINT('',(66.6561298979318,91.7442920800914,0.));
#1636=DIRECTION('',(0.,0.,1.));
#1637=DIRECTION('',(1.,0.,0.));
#1638=AXIS2_PLACEMENT_3D('',#1635,#1636,#1637);
#1639=CYLINDRICAL_SURFACE('',#1638,75.);
#1640=CARTESIAN_POINT('',(7.84174021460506,45.2054097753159,54.8836120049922));
#1641=CARTESIAN_POINT('',(8.42085807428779,44.4735258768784,55.0502906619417));
#1642=CARTESIAN_POINT('',(9.01450799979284,43.7513765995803,55.209538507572));
#1643=CARTESIAN_POINT('',(10.2303676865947,42.327598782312,55.5107759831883));
#1644=CARTESIAN_POINT('',(10.8525825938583,41.6259739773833,55.6527624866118));
#1645=CARTESIAN_POINT('',(12.1256224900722,40.2437321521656,55.9171774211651));
#1646=CARTESIAN_POINT('',(12.7764809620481,39.5631413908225,56.0395821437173));
#1647=CARTESIAN_POINT('',(14.1052595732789,38.225184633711,56.2621303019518));
#1648=CARTESIAN_POINT('',(14.7831780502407,37.5678172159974,56.3622751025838));
#1649=CARTESIAN_POINT('',(16.1445761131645,36.2968015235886,56.5353738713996));
#1650=CARTESIAN_POINT('',(16.827292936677,35.6824346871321,56.6090468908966));
#1651=CARTESIAN_POINT('',(18.2161494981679,34.4781320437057,56.731442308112));
#1652=CARTESIAN_POINT('',(18.9222895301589,33.888196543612,56.7801643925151));
#1653=CARTESIAN_POINT('',(20.3561044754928,32.7345154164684,56.8513338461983));
#1654=CARTESIAN_POINT('',(21.0837635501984,32.1707512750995,56.873800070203));
#1655=CARTESIAN_POINT('',(22.5595460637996,31.070257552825,56.8918906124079));
#1656=CARTESIAN_POINT('',(23.3076687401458,30.5335269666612,56.8875159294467));
#1657=CARTESIAN_POINT('',(24.7008256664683,29.5723619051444,56.8549142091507));
#1658=CARTESIAN_POINT('',(25.3430814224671,29.1437531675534,56.8306377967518));
#1659=CARTESIAN_POINT('',(26.6398245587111,28.3069945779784,56.7637654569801));
#1660=CARTESIAN_POINT('',(27.2943116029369,27.8988441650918,56.7211700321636));
#1661=CARTESIAN_POINT('',(28.614800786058,27.1033486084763,56.6184273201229));
#1662=CARTESIAN_POINT('',(29.2808072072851,26.716011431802,56.5582733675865));
#1663=CARTESIAN_POINT('',(30.6230897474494,25.9627402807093,56.4214776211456));
#1664=CARTESIAN_POINT('',(31.2993659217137,25.5968064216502,56.3448357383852));
#1665=CARTESIAN_POINT('',(33.3774071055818,24.5132920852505,56.0876305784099));
#1666=CARTESIAN_POINT('',(34.7945395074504,23.8304055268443,55.8825133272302));
#1667=CARTESIAN_POINT('',(36.9437442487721,22.8763840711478,55.5353678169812));
#1668=CARTESIAN_POINT('',(37.6638260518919,22.5701829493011,55.4131204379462));
#1669=CARTESIAN_POINT('',(39.1113391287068,21.981160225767,55.1568545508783));
#1670=CARTESIAN_POINT('',(39.8387696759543,21.6983363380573,55.0228371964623));
#1671=CARTESIAN_POINT('',(40.56962997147,21.4271922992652,54.8836193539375));
#1672=B_SPLINE_CURVE_WITH_KNOTS('',3,(#1640,#1641,#1642,#1643,#1644,#1645,#1646,#1647,#1648,
#1649,#1650,#1651,#1652,#1653,#1654,#1655,#1656,#1657,#1658,#1659,#1660,#1661,#1662,#1663,#1664,
#1665,#1666,#1667,#1668,#1669,#1670,#1671),.UNSPECIFIED.,.F.,.F.,(4,2,2,2,2,2,2,2,2,2,2,2,2,2,2,
4),(0.,2.84406580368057,5.6886459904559,8.53664459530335,11.3844685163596,14.1477361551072,
16.9110384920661,19.6723552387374,22.4335692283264,24.7505557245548,27.0674786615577,
29.3852822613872,31.7030983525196,36.4572921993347,38.8328479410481,41.2081711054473),.UNSPECIFIED.);
#1673=CARTESIAN_POINT('',(7.84189847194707,45.2052097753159,54.8836575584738));
#1674=VERTEX_POINT('',#1673);
#1675=CARTESIAN_POINT('',(40.56942997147,21.4272664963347,54.883657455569));
#1676=VERTEX_POINT('',#1675);
#1677=EDGE_CURVE('E700',#1674,#1676,#1672,.T.);
#1678=ORIENTED_EDGE('',*,*,#1677,.T.);
#1679=DIRECTION('',(0.,0.,1.));
#1680=VECTOR('',#1679,1.);
#1681=CARTESIAN_POINT('',(40.56942997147,21.4272664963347,0.));
#1682=LINE('',#1681,#1680);
#1683=EDGE_CURVE('E1292',#1325,#1676,#1682,.T.);
#1684=ORIENTED_EDGE('',*,*,#1683,.F.);
#1685=ORIENTED_EDGE('',*,*,#1326,.T.);
#1686=DIRECTION('',(0.,0.,1.));
#1687=VECTOR('',#1686,1.);
#1688=CARTESIAN_POINT('',(7.84189847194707,45.2052097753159,0.));
#1689=LINE('',#1688,#1687);
#1690=EDGE_CURVE('E697',#1288,#1674,#1689,.T.);
#1691=ORIENTED_EDGE('',*,*,#1690,.T.);
#1692=EDGE_LOOP('',(#1678,#1684,#1685,#1691));
#1693=FACE_BOUND('',#1692,.T.);
#1694=ADVANCED_FACE('F359',(#1693),#1639,.F.);
#1695=CARTESIAN_POINT('',(0.,0.,53.280422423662));
#1696=DIRECTION('',(0.,0.,1.));
#1697=DIRECTION('',(1.,0.,0.));
#1698=AXIS2_PLACEMENT_3D('',#1695,#1696,#1697);
#1699=TOROIDAL_SURFACE('',#1698,48.,0.999999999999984);
#1700=CARTESIAN_POINT('',(47.0200433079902,10.8608006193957,54.246548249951));
#1701=CARTESIAN_POINT('',(47.0300426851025,10.9441688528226,54.2389284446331));
#1702=CARTESIAN_POINT('',(47.0389781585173,11.0275511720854,54.230192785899));
#1703=CARTESIAN_POINT('',(47.0547320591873,11.19427105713,54.2107288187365));
#1704=CARTESIAN_POINT('',(47.0615508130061,11.2776086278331,54.2000008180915));
#1705=CARTESIAN_POINT('',(47.0788423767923,11.5273406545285,54.1652025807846));
#1706=CARTESIAN_POINT('',(47.0861675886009,11.6935975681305,54.1385042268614));
#1707=CARTESIAN_POINT('',(47.0925423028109,12.025122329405,54.0796296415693));
#1708=CARTESIAN_POINT('',(47.0915989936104,12.1903909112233,54.0474581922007));
#1709=CARTESIAN_POINT('',(47.0816000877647,12.5197977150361,53.9787849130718));
#1710=CARTESIAN_POINT('',(47.0725424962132,12.6839356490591,53.9422820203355));
#1711=CARTESIAN_POINT('',(47.028437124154,13.2364622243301,53.8132579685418));
#1712=CARTESIAN_POINT('',(46.9747719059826,13.6216737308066,53.7129592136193));
#1713=CARTESIAN_POINT('',(46.8238837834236,14.3807334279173,53.5039341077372));
#1714=CARTESIAN_POINT('',(46.7266936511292,14.7545899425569,53.3952141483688));
#1715=CARTESIAN_POINT('',(46.6062067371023,15.128150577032,53.2844803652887));
#1716=CARTESIAN_POINT('',(46.6039916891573,15.1349928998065,53.2824513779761));
#1717=CARTESIAN_POINT('',(46.6017692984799,15.1418327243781,53.280422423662));
#1718=B_SPLINE_CURVE_WITH_KNOTS('',3,(#1700,#1701,#1702,#1703,#1704,#1705,#1706,#1707,#1708,
#1709,#1710,#1711,#1712,#1713,#1714,#1715,#1716,#1717),.UNSPECIFIED.,.F.,.F.,(4,2,2,2,2,2,2,2,
4),(0.,0.252899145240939,0.505759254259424,1.01104586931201,1.51589324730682,2.02086477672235,
3.22282684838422,4.4238854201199,4.44630337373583),.UNSPECIFIED.);
#1719=CARTESIAN_POINT('',(47.0203053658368,10.8629875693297,54.2463482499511));
#1720=VERTEX_POINT('',#1719);
#1721=CARTESIAN_POINT('',(46.6017692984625,15.1418327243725,53.280422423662));
#1722=VERTEX_POINT('',#1721);
#1723=EDGE_CURVE('E553',#1720,#1722,#1718,.T.);
#1724=ORIENTED_EDGE('',*,*,#1723,.T.);
#1725=CARTESIAN_POINT('',(46.6017692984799,15.1418327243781,53.280422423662));
#1726=CARTESIAN_POINT('',(46.5995468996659,15.1486725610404,53.2824513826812));
#1727=CARTESIAN_POINT('',(46.5973170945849,15.1555100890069,53.2844803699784));
#1728=CARTESIAN_POINT('',(46.4947653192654,15.4688303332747,53.3774874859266));
#1729=CARTESIAN_POINT('',(46.3795657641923,15.7706510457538,53.468466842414));
#1730=CARTESIAN_POINT('',(46.119808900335,16.3631628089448,53.6455062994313));
#1731=CARTESIAN_POINT('',(45.9752295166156,16.6538452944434,53.7315626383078));
#1732=CARTESIAN_POINT('',(45.7208932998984,17.1079926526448,53.8606421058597));
#1733=CARTESIAN_POINT('',(45.6204247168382,17.2757250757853,53.9070824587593));
#1734=CARTESIAN_POINT('',(45.4091462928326,17.6059634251,53.9946488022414));
#1735=CARTESIAN_POINT('',(45.2983385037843,17.7684703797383,54.0357758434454));
#1736=CARTESIAN_POINT('',(45.0661890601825,18.0881107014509,54.1110036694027));
#1737=CARTESIAN_POINT('',(44.944824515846,18.2452313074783,54.1450886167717));
#1738=CARTESIAN_POINT('',(44.7551657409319,18.4761184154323,54.1890783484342));
#1739=CARTESIAN_POINT('',(44.6906407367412,18.5523215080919,54.2025573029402));
#1740=CARTESIAN_POINT('',(44.5590952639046,18.7030242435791,54.2267365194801));
#1741=CARTESIAN_POINT('',(44.4920742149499,18.7775234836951,54.2374361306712));
#1742=CARTESIAN_POINT('',(44.4238325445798,18.8511157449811,54.2465482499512));
#1743=B_SPLINE_CURVE_WITH_KNOTS('',3,(#1725,#1726,#1727,#1728,#1729,#1730,#1731,#1732,#1733,
#1734,#1735,#1736,#1737,#1738,#1739,#1740,#1741,#1742),.UNSPECIFIED.,.F.,.F.,(4,2,2,2,2,2,2,2,
4),(0.,0.0224179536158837,1.02762032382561,2.03358077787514,2.63610666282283,3.23851322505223,
3.84226017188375,4.14445886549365,4.44672826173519),.UNSPECIFIED.);
#1744=CARTESIAN_POINT('',(44.4253300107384,18.8495004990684,54.2463482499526));
#1745=VERTEX_POINT('',#1744);
#1746=EDGE_CURVE('E562',#1722,#1745,#1743,.T.);
#1747=ORIENTED_EDGE('',*,*,#1746,.T.);
#1748=CARTESIAN_POINT('',(0.,0.,54.2463482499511));
#1749=DIRECTION('',(0.,0.,1.));
#1750=DIRECTION('',(1.,0.,0.));
#1751=AXIS2_PLACEMENT_3D('',#1748,#1749,#1750);
#1752=CIRCLE('',#1751,48.2588190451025);
#1753=EDGE_CURVE('E645',#1720,#1745,#1752,.T.);
#1754=ORIENTED_EDGE('',*,*,#1753,.F.);
#1755=EDGE_LOOP('',(#1724,#1747,#1754));
#1756=FACE_BOUND('',#1755,.T.);
#1757=ADVANCED_FACE('F740',(#1756),#1699,.T.);
#1758=CARTESIAN_POINT('',(37.091204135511,12.0516627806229,0.));
#1759=DIRECTION('',(0.,0.,1.));
#1760=DIRECTION('',(1.,0.,0.));
#1761=AXIS2_PLACEMENT_3D('',#1758,#1759,#1760);
#1762=CYLINDRICAL_SURFACE('',#1761,10.);
#1763=ORIENTED_EDGE('',*,*,#1746,.F.);
#1764=ORIENTED_EDGE('',*,*,#1723,.F.);
#1765=CARTESIAN_POINT('',(43.3702146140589,4.26873098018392,55.5000918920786));
#1766=CARTESIAN_POINT('',(43.5667173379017,4.42723858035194,55.4435320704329));
#1767=CARTESIAN_POINT('',(43.7574028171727,4.59338506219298,55.3881462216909));
#1768=CARTESIAN_POINT('',(44.1260279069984,4.94004057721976,55.2799321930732));
#1769=CARTESIAN_POINT('',(44.3039671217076,5.12055005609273,55.2271040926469));
#1770=CARTESIAN_POINT('',(44.6464246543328,5.49549765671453,55.1240838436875));
#1771=CARTESIAN_POINT('',(44.8109065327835,5.68997108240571,55.0738989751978));
#1772=CARTESIAN_POINT('',(45.124873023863,6.0913703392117,54.9765145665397));
#1773=CARTESIAN_POINT('',(45.2743575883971,6.29829621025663,54.929315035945));
#1774=CARTESIAN_POINT('',(45.5697066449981,6.74204079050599,54.8341040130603));
#1775=CARTESIAN_POINT('',(45.7141163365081,6.97989220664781,54.7863812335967));
#1776=CARTESIAN_POINT('',(45.9828849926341,7.46739741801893,54.6949123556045));
#1777=CARTESIAN_POINT('',(46.1072437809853,7.71705131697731,54.6511662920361));
#1778=CARTESIAN_POINT('',(46.3346162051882,8.22585614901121,54.5679569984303));
#1779=CARTESIAN_POINT('',(46.4376799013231,8.48498308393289,54.528483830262));
#1780=CARTESIAN_POINT('',(46.621918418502,9.01139947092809,54.4539039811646));
#1781=CARTESIAN_POINT('',(46.703103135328,9.27868517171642,54.4187953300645));
#1782=CARTESIAN_POINT('',(46.8288215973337,9.76505786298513,54.3597212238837));
#1783=CARTESIAN_POINT('',(46.8774446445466,9.98299822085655,54.3349362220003));
#1784=CARTESIAN_POINT('',(46.9600491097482,10.4220014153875,54.2883132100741));
#1785=CARTESIAN_POINT('',(46.9940271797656,10.6430649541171,54.2664758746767));
#1786=CARTESIAN_POINT('',(47.0531149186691,11.137566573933,54.221218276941));
#1787=CARTESIAN_POINT('',(47.0744749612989,11.4115307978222,54.1985590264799));
#1788=CARTESIAN_POINT('',(47.0945676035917,11.960734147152,54.1578854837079));
#1789=CARTESIAN_POINT('',(47.0932908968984,12.2359737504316,54.1398731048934));
#1790=CARTESIAN_POINT('',(47.0680038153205,12.7860991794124,54.1085648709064));
#1791=CARTESIAN_POINT('',(47.0439591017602,13.0609838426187,54.0952761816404));
#1792=CARTESIAN_POINT('',(46.9731998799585,13.6080120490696,54.0735167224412));
#1793=CARTESIAN_POINT('',(46.926485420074,13.8801555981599,54.0650459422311));
#1794=CARTESIAN_POINT('',(46.8107125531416,14.4196208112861,54.0529653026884));
#1795=CARTESIAN_POINT('',(46.7416649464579,14.6869447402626,54.0493530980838));
#1796=CARTESIAN_POINT('',(46.5816959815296,15.2149954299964,54.0469991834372));
#1797=CARTESIAN_POINT('',(46.4907740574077,15.4757220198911,54.0482575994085));
#1798=CARTESIAN_POINT('',(46.2877499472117,15.9886143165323,54.0556378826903));
#1799=CARTESIAN_POINT('',(46.1756553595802,16.2407830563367,54.0617580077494));
#1800=CARTESIAN_POINT('',(45.9310910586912,16.7348647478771,54.0788304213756));
#1801=CARTESIAN_POINT('',(45.7986215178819,16.9767777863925,54.0897826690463));
#1802=CARTESIAN_POINT('',(45.5146528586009,17.4480509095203,54.1164336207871));
#1803=CARTESIAN_POINT('',(45.3632027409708,17.6774412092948,54.1321202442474));
#1804=CARTESIAN_POINT('',(45.0421365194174,18.1227433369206,54.1681759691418));
#1805=CARTESIAN_POINT('',(44.8725203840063,18.3386551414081,54.1885450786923));
#1806=CARTESIAN_POINT('',(44.516370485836,18.7555474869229,54.2338721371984));
#1807=CARTESIAN_POINT('',(44.3298356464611,18.9565270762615,54.2588303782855));
#1808=CARTESIAN_POINT('',(43.9412382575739,19.3422026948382,54.3132186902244));
#1809=CARTESIAN_POINT('',(43.7391758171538,19.5268988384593,54.3426487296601));
#1810=CARTESIAN_POINT('',(43.3193197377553,19.8802295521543,54.4060996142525));
#1811=CARTESIAN_POINT('',(43.1014127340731,20.0487231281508,54.4401554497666));
#1812=CARTESIAN_POINT('',(42.6529257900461,20.3668809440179,54.5125156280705));
#1813=CARTESIAN_POINT('',(42.4223455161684,20.5165446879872,54.5508200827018));
#1814=CARTESIAN_POINT('',(41.9502158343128,20.7961033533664,54.6314965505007));
#1815=CARTESIAN_POINT('',(41.7086680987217,20.9260012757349,54.6738679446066));
#1816=CARTESIAN_POINT('',(41.2164002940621,21.1652617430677,54.7624697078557));
#1817=CARTESIAN_POINT('',(40.9656821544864,21.2746285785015,54.808699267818));
#1818=CARTESIAN_POINT('',(40.3645373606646,21.5080562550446,54.9222412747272));
#1819=CARTESIAN_POINT('',(40.0108483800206,21.6231225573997,54.9911310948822));
#1820=CARTESIAN_POINT('',(39.4738193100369,21.7654389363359,55.0990195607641));
#1821=CARTESIAN_POINT('',(39.2938674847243,21.8078096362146,55.1357114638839));
#1822=CARTESIAN_POINT('',(38.9321578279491,21.8824799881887,55.2105718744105));
#1823=CARTESIAN_POINT('',(38.7503997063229,21.9147779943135,55.248740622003));
#1824=CARTESIAN_POINT('',(38.5679897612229,21.9420168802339,55.2876143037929));
#1825=B_SPLINE_CURVE_WITH_KNOTS('',3,(#1765,#1766,#1767,#1768,#1769,#1770,#1771,#1772,#1773,
#1774,#1775,#1776,#1777,#1778,#1779,#1780,#1781,#1782,#1783,#1784,#1785,#1786,#1787,#1788,#1789,
#1790,#1791,#1792,#1793,#1794,#1795,#1796,#1797,#1798,#1799,#1800,#1801,#1802,#1803,#1804,#1805,
#1806,#1807,#1808,#1809,#1810,#1811,#1812,#1813,#1814,#1815,#1816,#1817,#1818,#1819,#1820,#1821,
#1822,#1823,#1824),.UNSPECIFIED.,.F.,.F.,(4,2,2,2,2,2,2,2,2,2,2,2,2,2,2,2,2,2,2,2,2,2,2,2,2,2,2,
2,2,4),(0.,0.775993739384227,1.55201156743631,2.33006555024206,3.10812202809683,
3.95408982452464,4.8000650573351,5.64402836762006,6.48760931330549,7.16111984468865,
7.83478426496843,8.66097207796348,9.4874995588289,10.3152755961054,11.1430498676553,
11.9704244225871,12.7978203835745,13.6249199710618,14.4520125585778,15.2770122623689,
16.1020133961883,16.9270670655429,17.75211493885,18.5837927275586,19.4154924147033,
20.2470657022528,21.0784650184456,22.2105974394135,22.7757975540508,23.3410899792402),.UNSPECIFIED.);
#1826=CARTESIAN_POINT('',(45.4159899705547,6.51109053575,54.8836573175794));
#1827=VERTEX_POINT('',#1826);
#1828=EDGE_CURVE('E705',#1827,#1720,#1825,.T.);
#1829=ORIENTED_EDGE('',*,*,#1828,.F.);
#1830=DIRECTION('',(0.,0.,1.));
#1831=VECTOR('',#1830,1.);
#1832=CARTESIAN_POINT('',(45.4159899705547,6.51109053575,0.));
#1833=LINE('',#1832,#1831);
#1834=EDGE_CURVE('E1291',#1395,#1827,#1833,.T.);
#1835=ORIENTED_EDGE('',*,*,#1834,.F.);
#1836=ORIENTED_EDGE('',*,*,#1396,.F.);
#1837=ORIENTED_EDGE('',*,*,#873,.F.);
#1838=ORIENTED_EDGE('',*,*,#850,.F.);
#1839=ORIENTED_EDGE('',*,*,#1391,.F.);
#1840=ORIENTED_EDGE('',*,*,#1683,.T.);
#1841=EDGE_CURVE('E701',#1745,#1676,#1825,.T.);
#1842=ORIENTED_EDGE('',*,*,#1841,.F.);
#1843=EDGE_LOOP('',(#1763,#1764,#1829,#1835,#1836,#1837,#1838,#1839,#1840,#1842));
#1844=FACE_BOUND('',#1843,.T.);
#1845=ADVANCED_FACE('F458',(#1844),#1762,.T.);
#1846=CARTESIAN_POINT('',(107.851883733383,-35.0432013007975,0.));
#1847=DIRECTION('',(0.,0.,1.));
#1848=DIRECTION('',(1.,0.,0.));
#1849=AXIS2_PLACEMENT_3D('',#1846,#1847,#1848);
#1850=CYLINDRICAL_SURFACE('',#1849,75.);
#1851=CARTESIAN_POINT('',(45.4161230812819,6.51129053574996,54.8836144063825));
#1852=CARTESIAN_POINT('',(44.8990176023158,5.73435217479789,55.0502929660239));
#1853=CARTESIAN_POINT('',(44.3956609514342,4.94660116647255,55.2095407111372));
#1854=CARTESIAN_POINT('',(43.4172895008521,3.35027839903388,55.5107779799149));
#1855=CARTESIAN_POINT('',(42.942279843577,2.54170290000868,55.6527643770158));
#1856=CARTESIAN_POINT('',(42.0210811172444,0.903833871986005,55.9171790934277));
#1857=CARTESIAN_POINT('',(41.5749273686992,0.074516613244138,56.0395837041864));
#1858=CARTESIAN_POINT('',(40.7130704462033,-1.60267822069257,56.2621316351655));
#1859=CARTESIAN_POINT('',(40.2973654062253,-2.45055465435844,56.362276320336));
#1860=CARTESIAN_POINT('',(39.5092531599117,-4.13808649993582,56.5353748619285));
#1861=CARTESIAN_POINT('',(39.1359268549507,-4.97723853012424,56.6090477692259));
#1862=CARTESIAN_POINT('',(38.4197476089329,-6.67026949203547,56.7314429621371));
#1863=CARTESIAN_POINT('',(38.0768950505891,-7.52414860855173,56.7801649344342));
#1864=CARTESIAN_POINT('',(37.4227526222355,-9.24429460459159,56.8513341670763));
#1865=CARTESIAN_POINT('',(37.1114402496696,-10.110552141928,56.8738002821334));
#1866=CARTESIAN_POINT('',(36.5208507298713,-11.8541758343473,56.8918906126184));
#1867=CARTESIAN_POINT('',(36.2415723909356,-12.7315415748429,56.8875158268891));
#1868=CARTESIAN_POINT('',(35.7579597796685,-14.3535279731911,56.8549139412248));
#1869=CARTESIAN_POINT('',(35.5487969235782,-15.0967960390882,56.8306374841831));
#1870=CARTESIAN_POINT('',(35.1537084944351,-16.5886429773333,56.7637650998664));
#1871=CARTESIAN_POINT('',(34.9677822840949,-17.337221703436,56.7211696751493));
#1872=CARTESIAN_POINT('',(34.6192751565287,-18.8389014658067,56.6184270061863));
#1873=CARTESIAN_POINT('',(34.4567031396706,-19.5920041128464,56.5582730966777));
#1874=CARTESIAN_POINT('',(34.1550882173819,-21.1013625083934,56.4214774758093));
#1875=CARTESIAN_POINT('',(34.016045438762,-21.8576182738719,56.3448356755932));
#1876=CARTESIAN_POINT('',(33.6277125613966,-24.1687744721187,56.0876308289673));
#1877=CARTESIAN_POINT('',(33.4161670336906,-25.7275691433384,55.8825138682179));
#1878=CARTESIAN_POINT('',(33.1729796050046,-28.066390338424,55.5353688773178));
#1879=CARTESIAN_POINT('',(33.1042825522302,-28.8458492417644,55.4131216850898));
#1880=CARTESIAN_POINT('',(32.9913947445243,-30.4045321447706,55.1568561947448));
#1881=CARTESIAN_POINT('',(32.9472015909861,-31.1837561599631,55.0228390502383));
#1882=CARTESIAN_POINT('',(32.9151764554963,-31.9626327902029,54.8836214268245));
#1883=B_SPLINE_CURVE_WITH_KNOTS('',3,(#1851,#1852,#1853,#1854,#1855,#1856,#1857,#1858,#1859,
#1860,#1861,#1862,#1863,#1864,#1865,#1866,#1867,#1868,#1869,#1870,#1871,#1872,#1873,#1874,#1875,
#1876,#1877,#1878,#1879,#1880,#1881,#1882),.UNSPECIFIED.,.F.,.F.,(4,2,2,2,2,2,2,2,2,2,2,2,2,2,2,
4),(0.,2.84406536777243,5.68864511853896,8.53664328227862,11.3844667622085,14.1477340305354,
16.911035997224,19.6723523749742,22.4335659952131,24.7505498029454,27.0674700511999,
29.3852709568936,31.7030843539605,36.4572724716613,38.8328253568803,41.2081456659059),.UNSPECIFIED.);
#1884=CARTESIAN_POINT('',(32.9151846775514,-31.9624327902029,54.8836571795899));
#1885=VERTEX_POINT('',#1884);
#1886=EDGE_CURVE('E726',#1827,#1885,#1883,.T.);
#1887=ORIENTED_EDGE('',*,*,#1886,.T.);
#1888=DIRECTION('',(0.,0.,1.));
#1889=VECTOR('',#1888,1.);
#1890=CARTESIAN_POINT('',(32.9151846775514,-31.9624327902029,0.));
#1891=LINE('',#1890,#1889);
#1892=EDGE_CURVE('E795',#1432,#1885,#1891,.T.);
#1893=ORIENTED_EDGE('',*,*,#1892,.F.);
#1894=ORIENTED_EDGE('',*,*,#1433,.T.);
#1895=ORIENTED_EDGE('',*,*,#1834,.T.);
#1896=EDGE_LOOP('',(#1887,#1893,#1894,#1895));
#1897=FACE_BOUND('',#1896,.T.);
#1898=ADVANCED_FACE('F739',(#1897),#1850,.F.);
#1899=CARTESIAN_POINT('',(24.8592276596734,-41.3625466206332,54.246548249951));
#1900=CARTESIAN_POINT('',(24.9416055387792,-41.3462943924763,54.2389284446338));
#1901=CARTESIAN_POINT('',(25.0236680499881,-41.3290259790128,54.2301927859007));
#1902=CARTESIAN_POINT('',(25.1870963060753,-41.2924895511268,54.2107288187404));
#1903=CARTESIAN_POINT('',(25.2684621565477,-41.2732218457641,54.2000008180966));
#1904=CARTESIAN_POINT('',(25.5113148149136,-41.2124956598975,54.1652025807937));
#1905=CARTESIAN_POINT('',(25.6716981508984,-41.1680861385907,54.1385042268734));
#1906=CARTESIAN_POINT('',(25.9889668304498,-41.0717020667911,54.0796296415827));
#1907=CARTESIAN_POINT('',(26.1458550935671,-41.0197341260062,54.0474581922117));
#1908=CARTESIAN_POINT('',(26.4560497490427,-40.9084323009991,53.9787849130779));
#1909=CARTESIAN_POINT('',(26.6093552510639,-40.8490966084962,53.9422820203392));
#1910=CARTESIAN_POINT('',(27.1212099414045,-40.6364098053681,53.8132579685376));
#1911=CARTESIAN_POINT('',(27.4709843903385,-40.4663342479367,53.7129592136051));
#1912=CARTESIAN_POINT('',(28.1462660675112,-40.0882687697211,53.5039341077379));
#1913=CARTESIAN_POINT('',(28.4717913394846,-39.8803074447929,53.3952141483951));
#1914=CARTESIAN_POINT('',(28.7898361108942,-39.6502809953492,53.2844803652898));
#1915=CARTESIAN_POINT('',(28.7956590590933,-39.646059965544,53.2824513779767));
#1916=CARTESIAN_POINT('',(28.8014773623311,-39.6418327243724,53.280422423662));
#1917=B_SPLINE_CURVE_WITH_KNOTS('',3,(#1899,#1900,#1901,#1902,#1903,#1904,#1905,#1906,#1907,
#1908,#1909,#1910,#1911,#1912,#1913,#1914,#1915,#1916),.UNSPECIFIED.,.F.,.F.,(4,2,2,2,2,2,2,2,
4),(0.,0.252899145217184,0.50575925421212,1.0110458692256,1.51589324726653,2.02086477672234,
3.222826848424,4.42388542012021,4.44630337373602),.UNSPECIFIED.);
#1918=CARTESIAN_POINT('',(24.8613885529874,-41.3621200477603,54.2463482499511));
#1919=VERTEX_POINT('',#1918);
#1920=CARTESIAN_POINT('',(28.8014773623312,-39.6418327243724,53.280422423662));
#1921=VERTEX_POINT('',#1920);
#1922=EDGE_CURVE('E536',#1919,#1921,#1917,.T.);
#1923=ORIENTED_EDGE('',*,*,#1922,.T.);
#1924=CARTESIAN_POINT('',(28.8014773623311,-39.6418327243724,53.280422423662));
#1925=CARTESIAN_POINT('',(28.807295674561,-39.6376054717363,53.2824513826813));
#1926=CARTESIAN_POINT('',(28.8131095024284,-39.6333718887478,53.2844803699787));
#1927=CARTESIAN_POINT('',(29.0794045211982,-39.4390180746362,53.3774874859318));
#1928=CARTESIAN_POINT('',(29.3308544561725,-39.2361890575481,53.4684668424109));
#1929=CARTESIAN_POINT('',(29.8140973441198,-38.8060493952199,53.6455062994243));
#1930=CARTESIAN_POINT('',(30.0458753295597,-38.578720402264,53.731562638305));
#1931=CARTESIAN_POINT('',(30.3992009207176,-38.1964930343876,53.8606421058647));
#1932=CARTESIAN_POINT('',(30.527677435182,-38.0491095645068,53.9070824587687));
#1933=CARTESIAN_POINT('',(30.7764641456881,-37.7461225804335,53.9946488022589));
#1934=CARTESIAN_POINT('',(30.8967759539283,-37.590520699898,54.0357758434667));
#1935=CARTESIAN_POINT('',(31.129033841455,-37.2709591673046,54.1110036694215));
#1936=CARTESIAN_POINT('',(31.2409607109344,-37.1069816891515,54.1450886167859));
#1937=CARTESIAN_POINT('',(31.4019396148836,-36.8552574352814,54.1890783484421));
#1938=CARTESIAN_POINT('',(31.4544737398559,-36.7703424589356,54.2025573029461));
#1939=CARTESIAN_POINT('',(31.5571507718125,-36.5986655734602,54.2267365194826));
#1940=CARTESIAN_POINT('',(31.6072931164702,-36.511903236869,54.2374361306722));
#1941=CARTESIAN_POINT('',(31.6561956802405,-36.4242602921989,54.2465482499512));
#1942=B_SPLINE_CURVE_WITH_KNOTS('',3,(#1924,#1925,#1926,#1927,#1928,#1929,#1930,#1931,#1932,
#1933,#1934,#1935,#1936,#1937,#1938,#1939,#1940,#1941),.UNSPECIFIED.,.F.,.F.,(4,2,2,2,2,2,2,2,
4),(0.,0.0224179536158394,1.02762032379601,2.0335807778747,2.63610666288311,3.23851322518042,
3.84226017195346,4.14445886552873,4.44672826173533),.UNSPECIFIED.);
#1943=CARTESIAN_POINT('',(31.6551222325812,-36.4261836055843,54.2463482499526));
#1944=VERTEX_POINT('',#1943);
#1945=EDGE_CURVE('E545',#1921,#1944,#1942,.T.);
#1946=ORIENTED_EDGE('',*,*,#1945,.T.);
#1947=EDGE_CURVE('E793',#1919,#1944,#1752,.T.);
#1948=ORIENTED_EDGE('',*,*,#1947,.F.);
#1949=EDGE_LOOP('',(#1923,#1946,#1948));
#1950=FACE_BOUND('',#1949,.T.);
#1951=ADVANCED_FACE('F754',(#1950),#1699,.T.);
#1952=CARTESIAN_POINT('',(22.9236248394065,-31.5516627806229,0.));
#1953=DIRECTION('',(0.,0.,1.));
#1954=DIRECTION('',(1.,0.,0.));
#1955=AXIS2_PLACEMENT_3D('',#1952,#1953,#1954);
#1956=CYLINDRICAL_SURFACE('',#1955,10.);
#1957=ORIENTED_EDGE('',*,*,#1945,.F.);
#1958=ORIENTED_EDGE('',*,*,#1922,.F.);
#1959=CARTESIAN_POINT('',(19.1256079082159,-40.8023420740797,55.1028258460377));
#1960=CARTESIAN_POINT('',(19.3046719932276,-40.875864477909,55.0646242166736));
#1961=CARTESIAN_POINT('',(19.4860117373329,-40.944235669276,55.027260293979));
#1962=CARTESIAN_POINT('',(19.8531653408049,-41.0705940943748,54.9541861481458));
#1963=CARTESIAN_POINT('',(20.0389899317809,-41.1285528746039,54.9184806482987));
#1964=CARTESIAN_POINT('',(20.4935422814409,-41.2558665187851,54.8341661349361));
#1965=CARTESIAN_POINT('',(20.7640298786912,-41.3196416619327,54.7865013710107));
#1966=CARTESIAN_POINT('',(21.3101549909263,-41.4245591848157,54.6951161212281));
#1967=CARTESIAN_POINT('',(21.585795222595,-41.4656892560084,54.6513977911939));
#1968=CARTESIAN_POINT('',(22.1400324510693,-41.5248072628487,54.5681586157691));
#1969=CARTESIAN_POINT('',(22.4186278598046,-41.5428070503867,54.5286356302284));
#1970=CARTESIAN_POINT('',(22.9767942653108,-41.5554141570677,54.4539693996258));
#1971=CARTESIAN_POINT('',(23.2563646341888,-41.550034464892,54.4188237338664));
#1972=CARTESIAN_POINT('',(23.758201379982,-41.5192758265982,54.3597003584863));
#1973=CARTESIAN_POINT('',(23.9806428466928,-41.4981533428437,54.3349004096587));
#1974=CARTESIAN_POINT('',(24.4236851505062,-41.4410324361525,54.2882816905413));
#1975=CARTESIAN_POINT('',(24.6442877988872,-41.4050510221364,54.2664595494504));
#1976=CARTESIAN_POINT('',(25.0089569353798,-41.3329392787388,54.2326780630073));
#1977=CARTESIAN_POINT('',(25.1537759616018,-41.300940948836,54.2198723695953));
#1978=CARTESIAN_POINT('',(25.4420432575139,-41.2304850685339,54.1955971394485));
#1979=CARTESIAN_POINT('',(25.5854905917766,-41.1920234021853,54.1841284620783));
#1980=CARTESIAN_POINT('',(25.9812427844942,-41.0763942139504,54.1541827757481));
#1981=CARTESIAN_POINT('',(26.2316849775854,-40.9923434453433,54.1371692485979));
#1982=CARTESIAN_POINT('',(26.7254491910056,-40.8045516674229,54.1075059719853));
#1983=CARTESIAN_POINT('',(26.9687677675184,-40.7008013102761,54.094858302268));
#1984=CARTESIAN_POINT('',(27.4469952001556,-40.4740648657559,54.0739721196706));
#1985=CARTESIAN_POINT('',(27.6818887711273,-40.3510457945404,54.0657412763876));
#1986=CARTESIAN_POINT('',(28.1412545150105,-40.0866833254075,54.0537587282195));
#1987=CARTESIAN_POINT('',(28.3657262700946,-39.9453391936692,54.0500072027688));
#1988=CARTESIAN_POINT('',(28.8119408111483,-39.6389379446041,54.0469371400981));
#1989=CARTESIAN_POINT('',(29.0331727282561,-39.4731340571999,54.0478114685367));
#1990=CARTESIAN_POINT('',(29.4611196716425,-39.1238131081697,54.0544384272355));
#1991=CARTESIAN_POINT('',(29.6678338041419,-38.9402949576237,54.0601913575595));
#1992=CARTESIAN_POINT('',(30.0651570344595,-38.5569943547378,54.0765438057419));
#1993=CARTESIAN_POINT('',(30.2557750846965,-38.3572210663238,54.0871406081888));
#1994=CARTESIAN_POINT('',(30.6197069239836,-37.9427795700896,54.1131297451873));
#1995=CARTESIAN_POINT('',(30.793020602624,-37.7281112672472,54.1285221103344));
#1996=CARTESIAN_POINT('',(31.1210997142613,-37.2855320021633,54.1640230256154));
#1997=CARTESIAN_POINT('',(31.2758719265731,-37.057625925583,54.1841298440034));
#1998=CARTESIAN_POINT('',(31.5659174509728,-36.5901588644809,54.2289683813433));
#1999=CARTESIAN_POINT('',(31.7011905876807,-36.3505977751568,54.2537001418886));
#2000=CARTESIAN_POINT('',(31.9514350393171,-35.8614372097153,54.3076863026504));
#2001=CARTESIAN_POINT('',(32.0663962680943,-35.6118328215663,54.3369429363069));
#2002=CARTESIAN_POINT('',(32.2752367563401,-35.104493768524,54.3998337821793));
#2003=CARTESIAN_POINT('',(32.3691161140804,-34.8467591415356,54.4334679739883));
#2004=CARTESIAN_POINT('',(32.5359016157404,-34.3229888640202,54.5052334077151));
#2005=CARTESIAN_POINT('',(32.6086414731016,-34.0569047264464,54.5433971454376));
#2006=CARTESIAN_POINT('',(32.7318146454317,-33.5202226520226,54.6238366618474));
#2007=CARTESIAN_POINT('',(32.7822468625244,-33.2496244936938,54.6661126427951));
#2008=CARTESIAN_POINT('',(32.860591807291,-32.7058329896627,54.7545797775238));
#2009=CARTESIAN_POINT('',(32.8885050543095,-32.4326397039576,54.800770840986));
#2010=CARTESIAN_POINT('',(32.9218131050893,-31.8855507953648,54.896849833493));
#2011=CARTESIAN_POINT('',(32.9272095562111,-31.6116552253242,54.946737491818));
#2012=CARTESIAN_POINT('',(32.921349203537,-31.338337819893,54.9983672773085));
#2013=B_SPLINE_CURVE_WITH_KNOTS('',3,(#1959,#1960,#1961,#1962,#1963,#1964,#1965,#1966,#1967,
#1968,#1969,#1970,#1971,#1972,#1973,#1974,#1975,#1976,#1977,#1978,#1979,#1980,#1981,#1982,#1983,
#1984,#1985,#1986,#1987,#1988,#1989,#1990,#1991,#1992,#1993,#1994,#1995,#1996,#1997,#1998,#1999,
#2000,#2001,#2002,#2003,#2004,#2005,#2006,#2007,#2008,#2009,#2010,#2011,#2012),.UNSPECIFIED.,
.F.,.F.,(4,2,2,2,2,2,2,2,2,2,2,2,2,2,2,2,2,2,2,2,2,2,2,2,2,2,4),(0.,0.591795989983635,
1.18518533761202,2.03004697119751,2.87536737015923,3.72025445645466,4.56467221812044,
5.23862803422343,5.91181450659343,6.35826292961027,6.80499674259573,7.59822142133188,
8.39182344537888,9.18679909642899,9.98180659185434,10.8102148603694,11.6386740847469,
12.4666694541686,13.2946701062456,14.1223670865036,14.9500715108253,15.7781857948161,
16.606296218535,17.4407545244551,18.275253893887,19.1097340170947,19.944153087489),.UNSPECIFIED.);
#2014=CARTESIAN_POINT('',(20.2267277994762,-41.1811355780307,54.8836573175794));
#2015=VERTEX_POINT('',#2014);
#2016=EDGE_CURVE('E779',#2015,#1919,#2013,.T.);
#2017=ORIENTED_EDGE('',*,*,#2016,.F.);
#2018=DIRECTION('',(0.,0.,1.));
#2019=VECTOR('',#2018,1.);
#2020=CARTESIAN_POINT('',(20.2267277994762,-41.1811355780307,0.));
#2021=LINE('',#2020,#2019);
#2022=EDGE_CURVE('E797',#1491,#2015,#2021,.T.);
#2023=ORIENTED_EDGE('',*,*,#2022,.F.);
#2024=ORIENTED_EDGE('',*,*,#1492,.F.);
#2025=ORIENTED_EDGE('',*,*,#963,.F.);
#2026=ORIENTED_EDGE('',*,*,#940,.F.);
#2027=ORIENTED_EDGE('',*,*,#1472,.F.);
#2028=ORIENTED_EDGE('',*,*,#1892,.T.);
#2029=EDGE_CURVE('E728',#1944,#1885,#2013,.T.);
#2030=ORIENTED_EDGE('',*,*,#2029,.F.);
#2031=EDGE_LOOP('',(#1957,#1958,#2017,#2023,#2024,#2025,#2026,#2027,#2028,#2030));
#2032=FACE_BOUND('',#2031,.T.);
#2033=ADVANCED_FACE('F742',(#2032),#1956,.T.);
#2034=CARTESIAN_POINT('',(0.,-113.402181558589,0.));
#2035=DIRECTION('',(0.,0.,1.));
#2036=DIRECTION('',(1.,0.,0.));
#2037=AXIS2_PLACEMENT_3D('',#2034,#2035,#2036);
#2038=CYLINDRICAL_SURFACE('',#2037,75.);
#2039=CARTESIAN_POINT('',(20.2269277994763,-41.1811915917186,54.8836202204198));
#2040=CARTESIAN_POINT('',(19.3282213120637,-40.9294826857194,55.0502985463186));
#2041=CARTESIAN_POINT('',(18.4234800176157,-40.6941909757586,55.2095460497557));
#2042=CARTESIAN_POINT('',(16.6029538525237,-40.2569962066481,55.5107828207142));
#2043=CARTESIAN_POINT('',(15.6871670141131,-40.055099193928,55.6527689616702));
#2044=CARTESIAN_POINT('',(13.8447953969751,-39.6851173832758,55.9171831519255));
#2045=CARTESIAN_POINT('',(12.9181989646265,-39.5170735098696,56.0395874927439));
#2046=CARTESIAN_POINT('',(11.056763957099,-39.2156814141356,56.2621348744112));
#2047=CARTESIAN_POINT('',(10.1219258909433,-39.0823310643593,56.3622792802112));
#2048=CARTESIAN_POINT('',(8.27344816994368,-38.8542685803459,56.5353772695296));
#2049=CARTESIAN_POINT('',(7.36000324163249,-38.7585267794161,56.6090499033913));
#2050=CARTESIAN_POINT('',(5.52852407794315,-38.6005759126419,56.7314445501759));
#2051=CARTESIAN_POINT('',(4.61048978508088,-38.5383672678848,56.7801662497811));
#2052=CARTESIAN_POINT('',(2.7723931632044,-38.447795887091,56.8513349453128));
#2053=CARTESIAN_POINT('',(1.85233276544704,-38.41940886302,56.8738007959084));
#2054=CARTESIAN_POINT('',(0.0115464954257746,-38.3965348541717,56.8918906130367));
#2055=CARTESIAN_POINT('',(-0.909179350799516,-38.4020466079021,56.8875155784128));
#2056=CARTESIAN_POINT('',(-2.6012235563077,-38.4433255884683,56.854913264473));
#2057=CARTESIAN_POINT('',(-3.37274764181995,-38.4740825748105,56.830636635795));
#2058=CARTESIAN_POINT('',(-4.9136659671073,-38.5593376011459,56.7637639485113));
#2059=CARTESIAN_POINT('',(-5.68306026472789,-38.6138349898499,56.7211683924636));
#2060=CARTESIAN_POINT('',(-7.21893573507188,-38.7464298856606,56.6184255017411));
#2061=CARTESIAN_POINT('',(-7.9854156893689,-38.8245363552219,56.5582715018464));
#2062=CARTESIAN_POINT('',(-9.51410348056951,-39.0041011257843,56.4214757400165));
#2063=CARTESIAN_POINT('',(-10.2763112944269,-39.1055595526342,56.3448338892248));
#2064=CARTESIAN_POINT('',(-12.5943506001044,-39.4504197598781,56.0876289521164));
#2065=CARTESIAN_POINT('',(-14.1422220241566,-39.7309220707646,55.8825120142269));
#2066=CARTESIAN_POINT('',(-16.4417198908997,-40.2223724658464,55.5353671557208));
#2067=CARTESIAN_POINT('',(-17.2042571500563,-40.3979036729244,55.4131200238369));
#2068=CARTESIAN_POINT('',(-18.7215354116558,-40.7722003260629,55.1568546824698));
#2069=CARTESIAN_POINT('',(-19.476277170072,-40.9709634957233,55.0228376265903));
#2070=CARTESIAN_POINT('',(-20.2269284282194,-41.1811917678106,54.8836201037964));
#2071=B_SPLINE_CURVE_WITH_KNOTS('',3,(#2039,#2040,#2041,#2042,#2043,#2044,#2045,#2046,#2047,
#2048,#2049,#2050,#2051,#2052,#2053,#2054,#2055,#2056,#2057,#2058,#2059,#2060,#2061,#2062,#2063,
#2064,#2065,#2066,#2067,#2068,#2069,#2070),.UNSPECIFIED.,.F.,.F.,(4,2,2,2,2,2,2,2,2,2,2,2,2,2,2,
4),(0.,2.8440643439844,5.68864307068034,8.53664019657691,11.3844626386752,14.1477289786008,
16.9110300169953,19.6723454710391,22.4335581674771,24.7505398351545,27.0674579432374,
29.3852567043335,31.7030679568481,36.4572515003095,38.8328021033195,41.2081201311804),.UNSPECIFIED.);
#2072=CARTESIAN_POINT('',(-20.2267284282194,-41.1811357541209,54.883657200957));
#2073=VERTEX_POINT('',#2072);
#2074=EDGE_CURVE('E798',#2015,#2073,#2071,.T.);
#2075=ORIENTED_EDGE('',*,*,#2074,.T.);
#2076=DIRECTION('',(0.,0.,1.));
#2077=VECTOR('',#2076,1.);
#2078=CARTESIAN_POINT('',(-20.2267284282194,-41.1811357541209,0.));
#2079=LINE('',#2078,#2077);
#2080=EDGE_CURVE('E800',#1528,#2073,#2079,.T.);
#2081=ORIENTED_EDGE('',*,*,#2080,.F.);
#2082=ORIENTED_EDGE('',*,*,#1529,.T.);
#2083=ORIENTED_EDGE('',*,*,#2022,.T.);
#2084=EDGE_LOOP('',(#2075,#2081,#2082,#2083));
#2085=FACE_BOUND('',#2084,.T.);
#2086=ADVANCED_FACE('F755',(#2085),#2038,.F.);
#2087=CARTESIAN_POINT('',(-32.6640085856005,-33.815492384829,53.1069746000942));
#2088=CARTESIAN_POINT('',(-32.6651929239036,-33.8103959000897,53.1231095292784));
#2089=CARTESIAN_POINT('',(-32.6662170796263,-33.8059721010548,53.1394641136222));
#2090=CARTESIAN_POINT('',(-32.6679313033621,-33.7985509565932,53.1725158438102));
#2091=CARTESIAN_POINT('',(-32.6686212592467,-33.795554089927,53.1892131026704));
#2092=CARTESIAN_POINT('',(-32.670161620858,-33.7888586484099,53.2394428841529));
#2093=CARTESIAN_POINT('',(-32.6704979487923,-33.7873882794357,53.2733217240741));
#2094=CARTESIAN_POINT('',(-32.6697612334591,-33.7905971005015,53.3408296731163));
#2095=CARTESIAN_POINT('',(-32.6686847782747,-33.7952911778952,53.3744579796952));
#2096=CARTESIAN_POINT('',(-32.6651977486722,-33.8103826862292,53.4403247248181));
#2097=CARTESIAN_POINT('',(-32.6627865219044,-33.8207829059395,53.4725624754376));
#2098=CARTESIAN_POINT('',(-32.6561761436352,-33.8489853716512,53.5410966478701));
#2099=CARTESIAN_POINT('',(-32.6517169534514,-33.8678476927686,53.5769269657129));
#2100=CARTESIAN_POINT('',(-32.6413627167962,-33.9109132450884,53.6449954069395));
#2101=CARTESIAN_POINT('',(-32.6354645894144,-33.9351279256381,53.6772256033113));
#2102=CARTESIAN_POINT('',(-32.619236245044,-34.0004858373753,53.7531848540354));
#2103=CARTESIAN_POINT('',(-32.6081614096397,-34.0440551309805,53.7946499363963));
#2104=CARTESIAN_POINT('',(-32.5838910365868,-34.1365340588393,53.8702861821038));
#2105=CARTESIAN_POINT('',(-32.5706913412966,-34.1854541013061,53.9044427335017));
#2106=CARTESIAN_POINT('',(-32.5442374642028,-34.2803877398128,53.9627587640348));
#2107=CARTESIAN_POINT('',(-32.5311857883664,-34.326029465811,53.9876291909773));
#2108=CARTESIAN_POINT('',(-32.5038550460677,-34.418986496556,54.0332604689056));
#2109=CARTESIAN_POINT('',(-32.489575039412,-34.4663030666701,54.0540181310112));
#2110=CARTESIAN_POINT('',(-32.4450029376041,-34.609993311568,54.11104852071));
#2111=CARTESIAN_POINT('',(-32.4130194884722,-34.707959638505,54.1419943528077));
#2112=CARTESIAN_POINT('',(-32.3459552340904,-34.9027970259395,54.1924369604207));
#2113=CARTESIAN_POINT('',(-32.3109671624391,-34.9996379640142,54.2121906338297));
#2114=CARTESIAN_POINT('',(-32.2375129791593,-35.1933969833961,54.243558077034));
#2115=CARTESIAN_POINT('',(-32.1990435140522,-35.290315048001,54.255163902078));
#2116=CARTESIAN_POINT('',(-32.1188659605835,-35.4833903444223,54.2717595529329));
#2117=CARTESIAN_POINT('',(-32.0771564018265,-35.5795472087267,54.2767463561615));
#2118=CARTESIAN_POINT('',(-31.9907070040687,-35.7705495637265,54.2812509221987));
#2119=CARTESIAN_POINT('',(-31.9459685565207,-35.8653956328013,54.2807711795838));
#2120=CARTESIAN_POINT('',(-31.8611359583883,-36.0381518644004,54.2756873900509));
#2121=CARTESIAN_POINT('',(-31.8214764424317,-36.1162983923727,54.2717696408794));
#2122=CARTESIAN_POINT('',(-31.7402567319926,-36.2712651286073,54.2611525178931));
#2123=CARTESIAN_POINT('',(-31.6986991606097,-36.3480869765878,54.2544568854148));
#2124=CARTESIAN_POINT('',(-31.5746067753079,-36.5704811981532,54.2313669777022));
#2125=CARTESIAN_POINT('',(-31.4895323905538,-36.7143123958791,54.2117160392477));
#2126=CARTESIAN_POINT('',(-31.3128212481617,-36.9967673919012,54.1654330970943));
#2127=CARTESIAN_POINT('',(-31.2211813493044,-37.1353886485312,54.1387977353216));
#2128=CARTESIAN_POINT('',(-31.0314695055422,-37.4074654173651,54.0799528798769));
#2129=CARTESIAN_POINT('',(-30.9333817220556,-37.5409068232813,54.047729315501));
#2130=CARTESIAN_POINT('',(-30.7312845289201,-37.8020810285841,53.9789332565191));
#2131=CARTESIAN_POINT('',(-30.6272736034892,-37.9298123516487,53.9423596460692));
#2132=CARTESIAN_POINT('',(-30.2664829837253,-38.351289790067,53.8132135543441));
#2133=CARTESIAN_POINT('',(-29.996503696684,-38.6315198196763,53.7128604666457));
#2134=CARTESIAN_POINT('',(-29.4282399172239,-39.156888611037,53.5038265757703));
#2135=CARTESIAN_POINT('',(-29.1300053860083,-39.4020874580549,53.3951605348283));
#2136=CARTESIAN_POINT('',(-28.8131094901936,-39.6333718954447,53.2844803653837));
#2137=CARTESIAN_POINT('',(-28.8072956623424,-39.6376054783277,53.2824513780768));
#2138=CARTESIAN_POINT('',(-28.8014773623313,-39.6418327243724,53.280422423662));
#2139=B_SPLINE_CURVE_WITH_KNOTS('',3,(#2087,#2088,#2089,#2090,#2091,#2092,#2093,#2094,#2095,
#2096,#2097,#2098,#2099,#2100,#2101,#2102,#2103,#2104,#2105,#2106,#2107,#2108,#2109,#2110,#2111,
#2112,#2113,#2114,#2115,#2116,#2117,#2118,#2119,#2120,#2121,#2122,#2123,#2124,#2125,#2126,#2127,
#2128,#2129,#2130,#2131,#2132,#2133,#2134,#2135,#2136,#2137,#2138),.UNSPECIFIED.,.F.,.F.,(4,2,2,
2,2,2,2,2,2,2,2,2,2,2,2,2,2,2,2,2,2,2,2,2,2,4),(0.,0.0508593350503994,0.101735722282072,
0.20284014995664,0.304189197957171,0.405587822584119,0.527131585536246,0.648937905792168,
0.831387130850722,1.01419778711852,1.17473937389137,1.33540495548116,1.65725569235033,
1.97138377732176,2.28581773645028,2.60039523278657,2.91482918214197,3.17791565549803,
3.44064894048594,3.94498695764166,4.44956790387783,4.95543830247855,5.46143874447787,
6.66399304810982,7.8644593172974,7.88687727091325),.UNSPECIFIED.);
#2140=CARTESIAN_POINT('',(-31.6551222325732,-36.4261836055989,54.2463482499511));
#2141=VERTEX_POINT('',#2140);
#2142=CARTESIAN_POINT('',(-28.8014773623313,-39.6418327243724,53.280422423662));
#2143=VERTEX_POINT('',#2142);
#2144=EDGE_CURVE('E517',#2141,#2143,#2139,.T.);
#2145=ORIENTED_EDGE('',*,*,#2144,.T.);
#2146=CARTESIAN_POINT('',(-28.8014773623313,-39.6418327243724,53.280422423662));
#2147=CARTESIAN_POINT('',(-28.795659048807,-39.6460599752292,53.2824513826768));
#2148=CARTESIAN_POINT('',(-28.7898361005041,-39.6502810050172,53.2844803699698));
#2149=CARTESIAN_POINT('',(-28.5227049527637,-39.8434839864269,53.377487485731));
#2150=CARTESIAN_POINT('',(-28.2521007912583,-40.0199494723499,53.4684668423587));
#2151=CARTESIAN_POINT('',(-27.6936833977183,-40.3466203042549,53.6455062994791));
#2152=CARTESIAN_POINT('',(-27.4058573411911,-40.4968057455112,53.7315626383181));
#2153=CARTESIAN_POINT('',(-26.9331539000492,-40.7147235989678,53.8606421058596));
#2154=CARTESIAN_POINT('',(-26.7532824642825,-40.7913680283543,53.9070824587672));
#2155=CARTESIAN_POINT('',(-26.3882453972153,-40.9343501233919,53.9946488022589));
#2156=CARTESIAN_POINT('',(-26.2030808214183,-41.0006898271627,54.0357758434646));
#2157=CARTESIAN_POINT('',(-25.8273881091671,-41.122830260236,54.1110036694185));
#2158=CARTESIAN_POINT('',(-25.6368489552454,-41.1786072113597,54.1450886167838));
#2159=CARTESIAN_POINT('',(-25.3476997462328,-41.2539201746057,54.189078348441));
#2160=CARTESIAN_POINT('',(-25.2507068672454,-41.2776429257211,54.2025573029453));
#2161=CARTESIAN_POINT('',(-25.055703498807,-41.3222435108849,54.2267365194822));
#2162=CARTESIAN_POINT('',(-24.9576927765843,-41.3431206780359,54.237436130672));
#2163=CARTESIAN_POINT('',(-24.8592276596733,-41.3625466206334,54.2465482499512));
#2164=B_SPLINE_CURVE_WITH_KNOTS('',3,(#2146,#2147,#2148,#2149,#2150,#2151,#2152,#2153,#2154,
#2155,#2156,#2157,#2158,#2159,#2160,#2161,#2162,#2163),.UNSPECIFIED.,.F.,.F.,(4,2,2,2,2,2,2,2,
4),(0.,0.0224179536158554,1.02762032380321,2.03358077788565,2.63610666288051,3.23851322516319,
3.84226017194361,4.14445886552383,4.44672826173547),.UNSPECIFIED.);
#2165=CARTESIAN_POINT('',(-24.8613885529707,-41.3621200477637,54.2463482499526));
#2166=VERTEX_POINT('',#2165);
#2167=EDGE_CURVE('E39',#2143,#2166,#2164,.T.);
#2168=ORIENTED_EDGE('',*,*,#2167,.T.);
#2169=EDGE_CURVE('E1306',#2141,#2166,#1752,.T.);
#2170=ORIENTED_EDGE('',*,*,#2169,.F.);
#2171=EDGE_LOOP('',(#2145,#2168,#2170));
#2172=FACE_BOUND('',#2171,.T.);
#2173=ADVANCED_FACE('F512',(#2172),#1699,.T.);
#2174=CARTESIAN_POINT('',(-22.9236248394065,-31.551662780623,0.));
#2175=DIRECTION('',(0.,0.,1.));
#2176=DIRECTION('',(1.,0.,0.));
#2177=AXIS2_PLACEMENT_3D('',#2174,#2175,#2176);
#2178=CYLINDRICAL_SURFACE('',#2177,10.);
#2179=ORIENTED_EDGE('',*,*,#2167,.F.);
#2180=ORIENTED_EDGE('',*,*,#2144,.F.);
#2181=CARTESIAN_POINT('',(-32.9213492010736,-31.3383377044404,54.9983672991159));
#2182=CARTESIAN_POINT('',(-32.9235634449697,-31.4421408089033,54.9787604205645));
#2183=CARTESIAN_POINT('',(-32.9241627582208,-31.5460142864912,54.9594060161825));
#2184=CARTESIAN_POINT('',(-32.9221196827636,-31.7540055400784,54.9211774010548));
#2185=CARTESIAN_POINT('',(-32.9194716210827,-31.8581234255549,54.9023040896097));
#2186=CARTESIAN_POINT('',(-32.9038120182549,-32.239150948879,54.8341895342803));
#2187=CARTESIAN_POINT('',(-32.8808943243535,-32.5160123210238,54.7865402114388));
#2188=CARTESIAN_POINT('',(-32.8119576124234,-33.0676501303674,54.6951815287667));
#2189=CARTESIAN_POINT('',(-32.7659233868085,-33.3424250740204,54.6514747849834));
#2190=CARTESIAN_POINT('',(-32.6509069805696,-33.88782569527,54.5682275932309));
#2191=CARTESIAN_POINT('',(-32.5819214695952,-34.1584507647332,54.5286877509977));
#2192=CARTESIAN_POINT('',(-32.4213874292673,-34.6933872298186,54.4539922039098));
#2193=CARTESIAN_POINT('',(-32.3298519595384,-34.9577021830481,54.4188339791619));
#2194=CARTESIAN_POINT('',(-32.1454872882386,-35.4255592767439,54.3596997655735));
#2195=CARTESIAN_POINT('',(-32.0566604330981,-35.630585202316,54.3349000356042));
#2196=CARTESIAN_POINT('',(-31.8654337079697,-36.0342821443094,54.2882823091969));
#2197=CARTESIAN_POINT('',(-31.7630491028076,-36.2329600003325,54.266461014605));
#2198=CARTESIAN_POINT('',(-31.5392373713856,-36.6336555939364,54.2247522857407));
#2199=CARTESIAN_POINT('',(-31.4170859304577,-36.835286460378,54.2050300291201));
#2200=CARTESIAN_POINT('',(-31.1585732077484,-37.2298052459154,54.1689848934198));
#2201=CARTESIAN_POINT('',(-31.0221987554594,-37.4226848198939,54.152665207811));
#2202=CARTESIAN_POINT('',(-30.7188008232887,-37.8210491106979,54.1217527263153));
#2203=CARTESIAN_POINT('',(-30.5500634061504,-38.0252664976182,54.1076025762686));
#2204=CARTESIAN_POINT('',(-30.1967133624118,-38.4198765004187,54.0837251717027));
#2205=CARTESIAN_POINT('',(-30.0120949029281,-38.6102639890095,54.0739995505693));
#2206=CARTESIAN_POINT('',(-29.6279700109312,-38.9760946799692,54.0590110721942));
#2207=CARTESIAN_POINT('',(-29.4284445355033,-39.1515181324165,54.0537540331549));
#2208=CARTESIAN_POINT('',(-29.0160220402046,-39.4859674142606,54.0477472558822));
#2209=CARTESIAN_POINT('',(-28.803124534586,-39.6449926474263,54.0469976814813));
#2210=CARTESIAN_POINT('',(-28.3562127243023,-39.9518709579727,54.0500727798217));
#2211=CARTESIAN_POINT('',(-28.1216877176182,-40.0989791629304,54.0540899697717));
#2212=CARTESIAN_POINT('',(-27.6413436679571,-40.3732056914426,54.0670019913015));
#2213=CARTESIAN_POINT('',(-27.395524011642,-40.5003229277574,54.0758970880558));
#2214=CARTESIAN_POINT('',(-26.8944923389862,-40.7336311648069,54.0985176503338));
#2215=CARTESIAN_POINT('',(-26.6392844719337,-40.8398312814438,54.1122410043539));
#2216=CARTESIAN_POINT('',(-26.1212221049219,-41.0306698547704,54.1444537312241));
#2217=CARTESIAN_POINT('',(-25.858367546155,-41.1153081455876,54.1629431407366));
#2218=CARTESIAN_POINT('',(-25.3270391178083,-41.2624585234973,54.2045903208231));
#2219=CARTESIAN_POINT('',(-25.0585680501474,-41.3249813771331,54.2277458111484));
#2220=CARTESIAN_POINT('',(-24.5178014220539,-41.4276104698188,54.2786222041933));
#2221=CARTESIAN_POINT('',(-24.2455058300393,-41.4677165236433,54.3063431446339));
#2222=CARTESIAN_POINT('',(-23.6988923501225,-41.5253543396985,54.3662351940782));
#2223=CARTESIAN_POINT('',(-23.4245735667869,-41.5428754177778,54.3984084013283));
#2224=CARTESIAN_POINT('',(-22.875965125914,-41.5553127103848,54.4670455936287));
#2225=CARTESIAN_POINT('',(-22.6016754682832,-41.5502289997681,54.5035095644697));
#2226=CARTESIAN_POINT('',(-22.0525618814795,-41.5174830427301,54.5809070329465));
#2227=CARTESIAN_POINT('',(-21.7777552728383,-41.4896184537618,54.6218777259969));
#2228=CARTESIAN_POINT('',(-21.2319862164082,-41.4113975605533,54.7078279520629));
#2229=CARTESIAN_POINT('',(-20.9610239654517,-41.3610401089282,54.7528076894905));
#2230=CARTESIAN_POINT('',(-20.4248153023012,-41.2383316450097,54.8465650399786));
#2231=CARTESIAN_POINT('',(-20.1595686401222,-41.165981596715,54.8953424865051));
#2232=CARTESIAN_POINT('',(-19.6365503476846,-40.9999727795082,54.9964649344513));
#2233=CARTESIAN_POINT('',(-19.3787781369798,-40.9063156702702,55.0488096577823));
#2234=CARTESIAN_POINT('',(-19.1256080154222,-40.802342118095,55.1028258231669));
#2235=B_SPLINE_CURVE_WITH_KNOTS('',3,(#2181,#2182,#2183,#2184,#2185,#2186,#2187,#2188,#2189,
#2190,#2191,#2192,#2193,#2194,#2195,#2196,#2197,#2198,#2199,#2200,#2201,#2202,#2203,#2204,#2205,
#2206,#2207,#2208,#2209,#2210,#2211,#2212,#2213,#2214,#2215,#2216,#2217,#2218,#2219,#2220,#2221,
#2222,#2223,#2224,#2225,#2226,#2227,#2228,#2229,#2230,#2231,#2232,#2233,#2234),.UNSPECIFIED.,
.F.,.F.,(4,2,2,2,2,2,2,2,2,2,2,2,2,2,2,2,2,2,2,2,2,2,2,2,2,2,4),(0.,0.316949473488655,
0.634453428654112,1.4789686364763,2.32404015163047,3.16923434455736,4.01394019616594,
4.68788311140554,5.36107357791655,6.0701626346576,6.77991423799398,7.57488828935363,
8.37015558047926,9.16645674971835,9.96278686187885,10.7924042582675,11.6220667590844,
12.4513668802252,13.2806733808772,14.1095755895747,14.9384846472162,15.7677856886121,
16.59708398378,17.433829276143,18.2706172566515,19.1073685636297,19.9440547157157),.UNSPECIFIED.);
#2236=CARTESIAN_POINT('',(-32.9151846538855,-31.9624333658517,54.883657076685));
#2237=VERTEX_POINT('',#2236);
#2238=EDGE_CURVE('E806',#2237,#2141,#2235,.T.);
#2239=ORIENTED_EDGE('',*,*,#2238,.F.);
#2240=DIRECTION('',(0.,0.,1.));
#2241=VECTOR('',#2240,1.);
#2242=CARTESIAN_POINT('',(-32.9151846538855,-31.9624333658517,0.));
#2243=LINE('',#2242,#2241);
#2244=EDGE_CURVE('E1298',#1590,#2237,#2243,.T.);
#2245=ORIENTED_EDGE('',*,*,#2244,.F.);
#2246=ORIENTED_EDGE('',*,*,#1591,.F.);
#2247=ORIENTED_EDGE('',*,*,#1016,.F.);
#2248=ORIENTED_EDGE('',*,*,#993,.F.);
#2249=ORIENTED_EDGE('',*,*,#1586,.F.);
#2250=ORIENTED_EDGE('',*,*,#2080,.T.);
#2251=EDGE_CURVE('E804',#2166,#2073,#2235,.T.);
#2252=ORIENTED_EDGE('',*,*,#2251,.F.);
#2253=EDGE_LOOP('',(#2179,#2180,#2239,#2245,#2246,#2247,#2248,#2249,#2250,#2252));
#2254=FACE_BOUND('',#2253,.T.);
#2255=ADVANCED_FACE('F760',(#2254),#2178,.T.);
#2256=CARTESIAN_POINT('',(-107.851883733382,-35.0432013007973,0.));
#2257=DIRECTION('',(0.,0.,1.));
#2258=DIRECTION('',(1.,0.,0.));
#2259=AXIS2_PLACEMENT_3D('',#2256,#2257,#2258);
#2260=CYLINDRICAL_SURFACE('',#2259,75.);
#2261=CARTESIAN_POINT('',(-32.915176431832,-31.9626333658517,54.883621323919));
#2262=CARTESIAN_POINT('',(-32.9535026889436,-31.0301304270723,55.0502996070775));
#2263=CARTESIAN_POINT('',(-33.0093074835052,-30.0969612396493,55.2095470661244));
#2264=CARTESIAN_POINT('',(-33.1560842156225,-28.2304374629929,55.5107837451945));
#2265=CARTESIAN_POINT('',(-33.2470625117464,-27.2970828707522,55.6527698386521));
#2266=CARTESIAN_POINT('',(-33.4645131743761,-25.4305527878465,55.917183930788));
#2267=CARTESIAN_POINT('',(-33.5910280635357,-24.4973788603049,56.0395882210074));
#2268=CARTESIAN_POINT('',(-33.8796023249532,-22.6339138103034,56.2621354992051));
#2269=CARTESIAN_POINT('',(-34.0416595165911,-21.7036225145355,56.3622798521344));
#2270=CARTESIAN_POINT('',(-34.3959703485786,-19.8751406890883,56.5353777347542));
#2271=CARTESIAN_POINT('',(-34.5871845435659,-18.9768171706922,56.60905031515));
#2272=CARTESIAN_POINT('',(-35.0029226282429,-17.1861676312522,56.7314448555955));
#2273=CARTESIAN_POINT('',(-35.2274469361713,-16.2938416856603,56.7801665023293));
#2274=CARTESIAN_POINT('',(-35.7093116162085,-14.5177199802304,56.8513350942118));
#2275=CARTESIAN_POINT('',(-35.9666282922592,-13.633918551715,56.8738008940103));
#2276=CARTESIAN_POINT('',(-36.5137081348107,-11.8761584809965,56.891890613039));
#2277=CARTESIAN_POINT('',(-36.8034700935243,-11.0021994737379,56.8875155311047));
#2278=CARTESIAN_POINT('',(-37.3655996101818,-9.40572473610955,56.8549131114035));
#2279=CARTESIAN_POINT('',(-37.6332657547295,-8.68146511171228,56.8306363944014));
#2280=CARTESIAN_POINT('',(-38.1905190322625,-7.24230788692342,56.7637634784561));
#2281=CARTESIAN_POINT('',(-38.4801055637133,-6.52741003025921,56.7211677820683));
#2282=CARTESIAN_POINT('',(-39.0808235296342,-5.1076777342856,56.6184245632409));
#2283=CARTESIAN_POINT('',(-39.391963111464,-4.40284722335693,56.5582703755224));
#2284=CARTESIAN_POINT('',(-40.0351310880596,-3.00446537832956,56.4214741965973));
#2285=CARTESIAN_POINT('',(-40.3671595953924,-2.31091410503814,56.3448321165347));
#2286=CARTESIAN_POINT('',(-41.4114567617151,-0.212892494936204,56.0876264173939));
#2287=CARTESIAN_POINT('',(-42.1565504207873,1.1725426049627,55.8825088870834));
#2288=CARTESIAN_POINT('',(-43.3345339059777,3.20763117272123,55.535363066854));
#2289=CARTESIAN_POINT('',(-43.7371118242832,3.87860593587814,55.4131156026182));
#2290=CARTESIAN_POINT('',(-44.5619556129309,5.20596095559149,55.1568495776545));
#2291=CARTESIAN_POINT('',(-44.9842195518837,5.86234263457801,55.0228321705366));
#2292=CARTESIAN_POINT('',(-45.4161234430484,6.51129107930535,54.8836142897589));
#2293=B_SPLINE_CURVE_WITH_KNOTS('',3,(#2261,#2262,#2263,#2264,#2265,#2266,#2267,#2268,#2269,
#2270,#2271,#2272,#2273,#2274,#2275,#2276,#2277,#2278,#2279,#2280,#2281,#2282,#2283,#2284,#2285,
#2286,#2287,#2288,#2289,#2290,#2291,#2292),.UNSPECIFIED.,.F.,.F.,(4,2,2,2,2,2,2,2,2,2,2,2,2,2,2,
4),(0.,2.84406417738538,5.6886427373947,8.53663969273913,11.3844619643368,14.1477281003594,
16.9110289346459,19.6723441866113,22.4335566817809,24.7505417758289,27.0674633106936,
29.3852655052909,31.7030801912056,36.4572710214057,38.8328252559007,41.2081469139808),.UNSPECIFIED.);
#2294=CARTESIAN_POINT('',(-45.4159903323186,6.51109107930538,54.883657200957));
#2295=VERTEX_POINT('',#2294);
#2296=EDGE_CURVE('E823',#2237,#2295,#2293,.T.);
#2297=ORIENTED_EDGE('',*,*,#2296,.T.);
#2298=DIRECTION('',(0.,0.,1.));
#2299=VECTOR('',#2298,1.);
#2300=CARTESIAN_POINT('',(-45.4159903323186,6.51109107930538,0.));
#2301=LINE('',#2300,#2299);
#2302=EDGE_CURVE('E295',#1627,#2295,#2301,.T.);
#2303=ORIENTED_EDGE('',*,*,#2302,.F.);
#2304=ORIENTED_EDGE('',*,*,#1628,.T.);
#2305=ORIENTED_EDGE('',*,*,#2244,.T.);
#2306=EDGE_LOOP('',(#2297,#2303,#2304,#2305));
#2307=FACE_BOUND('',#2306,.T.);
#2308=ADVANCED_FACE('F510',(#2307),#2260,.F.);
#2309=CARTESIAN_POINT('',(-42.2411049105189,20.6236241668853,53.1634973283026));
#2310=CARTESIAN_POINT('',(-42.237926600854,20.6255333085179,53.1806237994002));
#2311=CARTESIAN_POINT('',(-42.2354332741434,20.627029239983,53.1979166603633));
#2312=CARTESIAN_POINT('',(-42.2318619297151,20.6291707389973,53.2326967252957));
#2313=CARTESIAN_POINT('',(-42.2307836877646,20.6298164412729,53.2501838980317));
#2314=CARTESIAN_POINT('',(-42.2297451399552,20.6304389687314,53.3023979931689));
#2315=CARTESIAN_POINT('',(-42.2319179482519,20.629138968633,53.3372146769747));
#2316=CARTESIAN_POINT('',(-42.2417720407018,20.6232250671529,53.4057294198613));
#2317=CARTESIAN_POINT('',(-42.2494541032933,20.6186106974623,53.4394273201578));
#2318=CARTESIAN_POINT('',(-42.2695941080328,20.6064517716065,53.5048298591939));
#2319=CARTESIAN_POINT('',(-42.2820603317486,20.5989021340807,53.5365309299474));
#2320=CARTESIAN_POINT('',(-42.3152076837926,20.5786941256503,53.606613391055));
#2321=CARTESIAN_POINT('',(-42.3372336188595,20.5651807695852,53.6441046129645));
#2322=CARTESIAN_POINT('',(-42.3859133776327,20.5349923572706,53.7145184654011));
#2323=CARTESIAN_POINT('',(-42.4125771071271,20.5183105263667,53.7474310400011));
#2324=CARTESIAN_POINT('',(-42.485475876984,20.4721496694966,53.8268370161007));
#2325=CARTESIAN_POINT('',(-42.534072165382,20.4408718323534,53.8700913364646));
#2326=CARTESIAN_POINT('',(-42.6354049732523,20.3742554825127,53.9475791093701));
#2327=CARTESIAN_POINT('',(-42.6881503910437,20.3389081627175,53.9817924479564));
#2328=CARTESIAN_POINT('',(-42.791191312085,20.2683358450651,54.0402507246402));
#2329=CARTESIAN_POINT('',(-42.841319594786,20.2333507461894,54.0650921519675));
#2330=CARTESIAN_POINT('',(-42.9424357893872,20.1613450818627,54.1096017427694));
#2331=CARTESIAN_POINT('',(-42.9934243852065,20.124322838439,54.1292655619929));
#2332=CARTESIAN_POINT('',(-43.0957164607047,20.0485303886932,54.1642322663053));
#2333=CARTESIAN_POINT('',(-43.1470203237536,20.009757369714,54.1795278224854));
#2334=CARTESIAN_POINT('',(-43.2494856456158,19.9307338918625,54.2063527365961));
#2335=CARTESIAN_POINT('',(-43.3006470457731,19.8904829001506,54.217880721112));
#2336=CARTESIAN_POINT('',(-43.4459496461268,19.7738273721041,54.2461246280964));
#2337=CARTESIAN_POINT('',(-43.539585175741,19.6958282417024,54.2588969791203));
#2338=CARTESIAN_POINT('',(-43.724390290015,19.536033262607,54.2757377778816));
#2339=CARTESIAN_POINT('',(-43.8155578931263,19.4542344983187,54.2797994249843));
#2340=CARTESIAN_POINT('',(-43.9948963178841,19.2872727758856,54.280912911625));
#2341=CARTESIAN_POINT('',(-44.0830649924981,19.2021074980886,54.2779598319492));
#2342=CARTESIAN_POINT('',(-44.256029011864,19.0287885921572,54.2663128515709));
#2343=CARTESIAN_POINT('',(-44.3408235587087,18.9406342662,54.257617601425));
#2344=CARTESIAN_POINT('',(-44.5378517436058,18.7281552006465,54.2313436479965));
#2345=CARTESIAN_POINT('',(-44.6485021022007,18.6026208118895,54.2116597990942));
#2346=CARTESIAN_POINT('',(-44.8627857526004,18.3469279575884,54.1652967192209));
#2347=CARTESIAN_POINT('',(-44.9664170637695,18.2167682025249,54.1386155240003));
#2348=CARTESIAN_POINT('',(-45.166507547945,17.9522537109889,54.0797437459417));
#2349=CARTESIAN_POINT('',(-45.2629665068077,17.8178988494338,54.0475529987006));
#2350=CARTESIAN_POINT('',(-45.4486421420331,17.5453350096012,53.9788360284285));
#2351=CARTESIAN_POINT('',(-45.5378571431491,17.4071251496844,53.9423088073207));
#2352=CARTESIAN_POINT('',(-45.8270457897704,16.9340270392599,53.8132384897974));
#2353=CARTESIAN_POINT('',(-46.0100874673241,16.5907628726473,53.7129155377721));
#2354=CARTESIAN_POINT('',(-46.3341626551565,15.8879731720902,53.5038864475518));
#2355=CARTESIAN_POINT('',(-46.4752458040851,15.5284674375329,53.3951904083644));
#2356=CARTESIAN_POINT('',(-46.5973170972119,15.1555100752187,53.284480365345));
#2357=CARTESIAN_POINT('',(-46.5995469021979,15.1486725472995,53.2824513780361));
#2358=CARTESIAN_POINT('',(-46.60176929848,15.1418327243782,53.280422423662));
#2359=B_SPLINE_CURVE_WITH_KNOTS('',3,(#2309,#2310,#2311,#2312,#2313,#2314,#2315,#2316,#2317,
#2318,#2319,#2320,#2321,#2322,#2323,#2324,#2325,#2326,#2327,#2328,#2329,#2330,#2331,#2332,#2333,
#2334,#2335,#2336,#2337,#2338,#2339,#2340,#2341,#2342,#2343,#2344,#2345,#2346,#2347,#2348,#2349,
#2350,#2351,#2352,#2353,#2354,#2355,#2356,#2357,#2358),.UNSPECIFIED.,.F.,.F.,(4,2,2,2,2,2,2,2,2,
2,2,2,2,2,2,2,2,2,2,2,2,2,2,2,4),(0.,0.0525357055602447,0.105063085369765,0.209099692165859,
0.313151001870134,0.417383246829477,0.553229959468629,0.689370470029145,0.904716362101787,
1.12053738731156,1.3182011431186,1.51603022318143,1.71418928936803,1.91242051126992,
2.27948279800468,2.64683155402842,3.01443799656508,3.38213085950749,3.88718516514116,
4.3923813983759,4.89759270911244,5.40292052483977,6.60514482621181,7.80594113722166,
7.82835909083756),.UNSPECIFIED.);
#2360=CARTESIAN_POINT('',(-44.4253300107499,18.8495004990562,54.2463482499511));
#2361=VERTEX_POINT('',#2360);
#2362=CARTESIAN_POINT('',(-46.6017692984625,15.1418327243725,53.280422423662));
#2363=VERTEX_POINT('',#2362);
#2364=EDGE_CURVE('E570',#2361,#2363,#2359,.T.);
#2365=ORIENTED_EDGE('',*,*,#2364,.T.);
#2366=CARTESIAN_POINT('',(-46.60176929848,15.1418327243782,53.280422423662));
#2367=CARTESIAN_POINT('',(-46.6039916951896,15.1349928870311,53.2824513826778));
#2368=CARTESIAN_POINT('',(-46.6062067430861,15.1281505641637,53.2844803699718));
#2369=CARTESIAN_POINT('',(-46.707405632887,14.8143907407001,53.377487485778));
#2370=CARTESIAN_POINT('',(-46.7916129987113,14.5025000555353,53.4684668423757));
#2371=CARTESIAN_POINT('',(-46.9297349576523,13.8704667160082,53.6455062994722));
#2372=CARTESIAN_POINT('',(-46.9836266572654,13.5503180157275,53.7315626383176));
#2373=CARTESIAN_POINT('',(-47.0448054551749,13.0334100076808,53.8606421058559));
#2374=CARTESIAN_POINT('',(-47.062115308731,12.8386576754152,53.9070824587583));
#2375=CARTESIAN_POINT('',(-47.0852967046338,12.4473028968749,53.9946488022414));
#2376=CARTESIAN_POINT('',(-47.0911705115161,12.2507008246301,54.0357758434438));
#2377=CARTESIAN_POINT('',(-47.0912375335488,11.8556523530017,54.1110036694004));
#2378=CARTESIAN_POINT('',(-47.0854047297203,11.6572028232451,54.1450886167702));
#2379=CARTESIAN_POINT('',(-47.0676795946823,11.3589325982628,54.1890783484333));
#2380=CARTESIAN_POINT('',(-47.0602688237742,11.2593561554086,54.2025573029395));
#2381=CARTESIAN_POINT('',(-47.0424271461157,11.060114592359,54.2267365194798));
#2382=CARTESIAN_POINT('',(-47.0319955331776,10.9604494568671,54.237436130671));
#2383=CARTESIAN_POINT('',(-47.0200433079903,10.8608006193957,54.2465482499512));
#2384=B_SPLINE_CURVE_WITH_KNOTS('',3,(#2366,#2367,#2368,#2369,#2370,#2371,#2372,#2373,#2374,
#2375,#2376,#2377,#2378,#2379,#2380,#2381,#2382,#2383),.UNSPECIFIED.,.F.,.F.,(4,2,2,2,2,2,2,2,
4),(0.,0.0224179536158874,1.02762032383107,2.03358077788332,2.63610666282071,3.23851322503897,
3.84226017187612,4.14445886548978,4.44672826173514),.UNSPECIFIED.);
#2385=CARTESIAN_POINT('',(-47.0203053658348,10.8629875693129,54.2463482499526));
#2386=VERTEX_POINT('',#2385);
#2387=EDGE_CURVE('E606',#2363,#2386,#2384,.T.);
#2388=ORIENTED_EDGE('',*,*,#2387,.T.);
#2389=EDGE_CURVE('E651',#2361,#2386,#1752,.T.);
#2390=ORIENTED_EDGE('',*,*,#2389,.F.);
#2391=EDGE_LOOP('',(#2365,#2388,#2390));
#2392=FACE_BOUND('',#2391,.T.);
#2393=ADVANCED_FACE('F507',(#2392),#1699,.T.);
#2394=CARTESIAN_POINT('',(-37.091204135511,12.051662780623,0.));
#2395=DIRECTION('',(0.,0.,1.));
#2396=DIRECTION('',(1.,0.,0.));
#2397=AXIS2_PLACEMENT_3D('',#2394,#2395,#2396);
#2398=CYLINDRICAL_SURFACE('',#2397,10.);
#2399=ORIENTED_EDGE('',*,*,#2387,.F.);
#2400=ORIENTED_EDGE('',*,*,#2364,.F.);
#2401=CARTESIAN_POINT('',(-38.56799026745,21.9420168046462,55.2876141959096));
#2402=CARTESIAN_POINT('',(-38.7378306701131,21.9166555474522,55.2514191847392));
#2403=CARTESIAN_POINT('',(-38.9071098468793,21.8869070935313,55.2158345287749));
#2404=CARTESIAN_POINT('',(-39.2441770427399,21.8186633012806,55.145932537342));
#2405=CARTESIAN_POINT('',(-39.4119649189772,21.7801671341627,55.1116153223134));
#2406=CARTESIAN_POINT('',(-39.9134412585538,21.6513625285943,55.0104530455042));
#2407=CARTESIAN_POINT('',(-40.2442698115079,21.5478827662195,54.9456042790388));
#2408=CARTESIAN_POINT('',(-40.8294109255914,21.3308280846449,54.834128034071));
#2409=CARTESIAN_POINT('',(-41.0858293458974,21.2233782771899,54.786445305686));
#2410=CARTESIAN_POINT('',(-41.5895228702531,20.9871255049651,54.6950268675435));
#2411=CARTESIAN_POINT('',(-41.836794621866,20.8583148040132,54.6512925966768));
#2412=CARTESIAN_POINT('',(-42.3198916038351,20.5803440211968,54.5680641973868));
#2413=CARTESIAN_POINT('',(-42.555732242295,20.4312124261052,54.5285642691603));
#2414=CARTESIAN_POINT('',(-43.0144777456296,20.1134625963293,54.4539377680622));
#2415=CARTESIAN_POINT('',(-43.2373893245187,19.9448546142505,54.4188089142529));
#2416=CARTESIAN_POINT('',(-43.6251901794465,19.6250935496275,54.3597028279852));
#2417=CARTESIAN_POINT('',(-43.7927184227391,19.4772720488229,54.3349050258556));
#2418=CARTESIAN_POINT('',(-44.1175860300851,19.1706355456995,54.2882842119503));
#2419=CARTESIAN_POINT('',(-44.2749353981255,19.0118316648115,54.2664582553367));
#2420=CARTESIAN_POINT('',(-44.4298625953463,18.8446085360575,54.2457421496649));
#2421=CARTESIAN_POINT('',(-44.4328974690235,18.841328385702,54.2453366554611));
#2422=CARTESIAN_POINT('',(-44.6141963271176,18.6451130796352,54.2211318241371));
#2423=CARTESIAN_POINT('',(-44.7850626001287,18.4449204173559,54.1994067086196));
#2424=CARTESIAN_POINT('',(-45.110731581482,18.0313394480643,54.1602138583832));
#2425=CARTESIAN_POINT('',(-45.2655235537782,17.8179424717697,54.1427489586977));
#2426=CARTESIAN_POINT('',(-45.5582524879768,17.3788441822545,54.1121272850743));
#2427=CARTESIAN_POINT('',(-45.6961491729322,17.1531152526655,54.0989806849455));
#2428=CARTESIAN_POINT('',(-45.9537068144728,16.6912713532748,54.0771104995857));
#2429=CARTESIAN_POINT('',(-46.073366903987,16.4551558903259,54.0683871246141));
#2430=CARTESIAN_POINT('',(-46.2982338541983,15.9640218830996,54.0551306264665));
#2431=CARTESIAN_POINT('',(-46.4026284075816,15.7086257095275,54.0507877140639));
#2432=CARTESIAN_POINT('',(-46.589975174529,15.1900329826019,54.046964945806));
#2433=CARTESIAN_POINT('',(-46.6729258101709,14.9268358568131,54.0474854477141));
#2434=CARTESIAN_POINT('',(-46.8167511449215,14.3946671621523,54.0533862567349));
#2435=CARTESIAN_POINT('',(-46.8776365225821,14.125698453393,54.0587642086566));
#2436=CARTESIAN_POINT('',(-46.9769745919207,13.5837933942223,54.0743510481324));
#2437=CARTESIAN_POINT('',(-47.0154276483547,13.3108571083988,54.0845598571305));
#2438=CARTESIAN_POINT('',(-47.0696734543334,12.7629552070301,54.1097603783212));
#2439=CARTESIAN_POINT('',(-47.0854656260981,12.4879895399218,54.1247522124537));
#2440=CARTESIAN_POINT('',(-47.09433984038,11.9379897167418,54.1594481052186));
#2441=CARTESIAN_POINT('',(-47.0874217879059,11.6629555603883,54.1791521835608));
#2442=CARTESIAN_POINT('',(-47.0510086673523,11.1147838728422,54.2231782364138));
#2443=CARTESIAN_POINT('',(-47.0215155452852,10.8416461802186,54.2474998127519));
#2444=CARTESIAN_POINT('',(-46.9402612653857,10.2991500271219,54.3006485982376));
#2445=CARTESIAN_POINT('',(-46.8885000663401,10.0297915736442,54.3294758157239));
#2446=CARTESIAN_POINT('',(-46.7628387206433,9.49524316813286,54.3916731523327));
#2447=CARTESIAN_POINT('',(-46.6888184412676,9.23008426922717,54.4250673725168));
#2448=CARTESIAN_POINT('',(-46.5193862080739,8.7072805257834,54.4961213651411));
#2449=CARTESIAN_POINT('',(-46.4239740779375,8.44963574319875,54.5337811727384));
#2450=CARTESIAN_POINT('',(-46.2125059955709,7.94348658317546,54.6132099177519));
#2451=CARTESIAN_POINT('',(-46.096441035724,7.69498625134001,54.6549806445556));
#2452=CARTESIAN_POINT('',(-45.8446271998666,7.20888300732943,54.7424265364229));
#2453=CARTESIAN_POINT('',(-45.7088778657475,6.97128034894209,54.7881017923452));
#2454=CARTESIAN_POINT('',(-45.4161610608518,6.50437895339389,54.8839975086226));
#2455=CARTESIAN_POINT('',(-45.2588579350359,6.27530431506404,54.9342845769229));
#2456=CARTESIAN_POINT('',(-44.926181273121,5.83152996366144,55.0384534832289));
#2457=CARTESIAN_POINT('',(-44.7508066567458,5.61683111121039,55.0923355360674));
#2458=CARTESIAN_POINT('',(-44.3833468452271,5.20322246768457,55.203433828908));
#2459=CARTESIAN_POINT('',(-44.1912633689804,5.00431105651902,55.2606497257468));
#2460=CARTESIAN_POINT('',(-43.7918304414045,4.62348071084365,55.3781424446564));
#2461=CARTESIAN_POINT('',(-43.5844823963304,4.44156021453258,55.4384189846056));
#2462=CARTESIAN_POINT('',(-43.3702142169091,4.2687306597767,55.5000920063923));
#2463=B_SPLINE_CURVE_WITH_KNOTS('',3,(#2401,#2402,#2403,#2404,#2405,#2406,#2407,#2408,#2409,
#2410,#2411,#2412,#2413,#2414,#2415,#2416,#2417,#2418,#2419,#2420,#2421,#2422,#2423,#2424,#2425,
#2426,#2427,#2428,#2429,#2430,#2431,#2432,#2433,#2434,#2435,#2436,#2437,#2438,#2439,#2440,#2441,
#2442,#2443,#2444,#2445,#2446,#2447,#2448,#2449,#2450,#2451,#2452,#2453,#2454,#2455,#2456,#2457,
#2458,#2459,#2460,#2461,#2462),.UNSPECIFIED.,.F.,.F.,(4,2,2,2,2,2,2,2,2,2,2,2,2,2,2,2,2,2,2,2,2,
2,2,2,2,2,2,2,2,2,4),(0.,0.526361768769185,1.05277342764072,2.10859735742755,2.9539363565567,
3.79958217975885,4.6440545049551,5.48808429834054,6.16199394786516,6.83523087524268,
6.84869230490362,7.63996463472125,8.43176210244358,9.22541186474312,10.0190993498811,
10.8459333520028,11.6728281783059,12.4993222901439,13.3258029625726,14.1523047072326,
14.9788099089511,15.8052438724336,16.6316793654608,17.4626577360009,18.2936429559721,
19.1249914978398,19.9563593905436,20.8025755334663,21.6488422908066,22.4950220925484,
23.341124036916),.UNSPECIFIED.);
#2464=CARTESIAN_POINT('',(-40.5694319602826,21.4272657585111,54.8836570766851));
#2465=VERTEX_POINT('',#2464);
#2466=EDGE_CURVE('E578',#2465,#2361,#2463,.T.);
#2467=ORIENTED_EDGE('',*,*,#2466,.F.);
#2468=DIRECTION('',(0.,0.,1.));
#2469=VECTOR('',#2468,1.);
#2470=CARTESIAN_POINT('',(-40.5694319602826,21.4272657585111,0.));
#2471=LINE('',#2470,#2469);
#2472=EDGE_CURVE('E825',#1200,#2465,#2471,.T.);
#2473=ORIENTED_EDGE('',*,*,#2472,.F.);
#2474=ORIENTED_EDGE('',*,*,#1201,.F.);
#2475=ORIENTED_EDGE('',*,*,#1069,.F.);
#2476=ORIENTED_EDGE('',*,*,#1046,.F.);
#2477=ORIENTED_EDGE('',*,*,#1630,.F.);
#2478=ORIENTED_EDGE('',*,*,#2302,.T.);
#2479=EDGE_CURVE('E613',#2386,#2295,#2463,.T.);
#2480=ORIENTED_EDGE('',*,*,#2479,.F.);
#2481=EDGE_LOOP('',(#2399,#2400,#2467,#2473,#2474,#2475,#2476,#2477,#2478,#2480));
#2482=FACE_BOUND('',#2481,.T.);
#2483=ADVANCED_FACE('F457',(#2482),#2398,.T.);
#2484=CARTESIAN_POINT('',(-66.656129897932,91.7442920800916,0.));
#2485=DIRECTION('',(0.,0.,1.));
#2486=DIRECTION('',(1.,0.,0.));
#2487=AXIS2_PLACEMENT_3D('',#2484,#2485,#2486);
#2488=CYLINDRICAL_SURFACE('',#2487,75.);
#2489=CARTESIAN_POINT('',(-40.5696319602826,21.427191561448,54.8836189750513));
#2490=CARTESIAN_POINT('',(-39.6946122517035,21.7518011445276,55.0502973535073));
#2491=CARTESIAN_POINT('',(-38.8243600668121,22.0932396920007,55.20954491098));
#2492=CARTESIAN_POINT('',(-37.0945466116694,22.8096200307,55.5107817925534));
#2493=CARTESIAN_POINT('',(-36.2349873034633,23.1845678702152,55.6527679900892));
#2494=CARTESIAN_POINT('',(-34.5270072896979,23.9681650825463,55.9171822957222));
#2495=CARTESIAN_POINT('',(-33.6786012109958,24.3768544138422,56.0395866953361));
#2496=CARTESIAN_POINT('',(-31.995514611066,25.2271470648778,56.2621341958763));
#2497=CARTESIAN_POINT('',(-31.1608332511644,25.6687483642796,56.362278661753));
#2498=CARTESIAN_POINT('',(-29.5313314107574,26.5707498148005,56.5353767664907));
#2499=CARTESIAN_POINT('',(-28.7360632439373,27.0302024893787,56.6090494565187));
#2500=CARTESIAN_POINT('',(-27.1615241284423,27.9789339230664,56.7314442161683));
#2501=CARTESIAN_POINT('',(-26.3822533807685,28.4682130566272,56.7801659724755));
#2502=CARTESIAN_POINT('',(-24.8419652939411,29.4753452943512,56.8513347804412));
#2503=CARTESIAN_POINT('',(-24.0809352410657,29.9931776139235,56.8738006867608));
#2504=CARTESIAN_POINT('',(-22.5782626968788,31.0566591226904,56.8918906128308));
#2505=CARTESIAN_POINT('',(-21.8366194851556,31.6023072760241,56.8875156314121));
#2506=CARTESIAN_POINT('',(-20.4919883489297,32.6302625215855,56.8549133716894));
#2507=CARTESIAN_POINT('',(-19.8858890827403,33.1086372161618,56.830636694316));
#2508=CARTESIAN_POINT('',(-18.6893683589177,34.0833417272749,56.7637638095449));
#2509=CARTESIAN_POINT('',(-18.0989464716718,34.5796710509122,56.7211681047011));
#2510=CARTESIAN_POINT('',(-16.9343313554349,35.5897103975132,56.6184248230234));
#2511=CARTESIAN_POINT('',(-16.3601443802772,36.1034269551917,56.5582705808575));
#2512=CARTESIAN_POINT('',(-15.2289526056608,37.1472410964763,56.4214742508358));
#2513=CARTESIAN_POINT('',(-14.671947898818,37.677338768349,56.3448320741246));
#2514=CARTESIAN_POINT('',(-12.9993142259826,39.3188508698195,56.0876260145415));
#2515=CARTESIAN_POINT('',(-11.9119324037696,40.4556015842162,55.8825081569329));
#2516=CARTESIAN_POINT('',(-10.3404632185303,42.2048098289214,55.5353617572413));
#2517=CARTESIAN_POINT('',(-9.82673112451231,42.7950276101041,55.4131140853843));
#2518=CARTESIAN_POINT('',(-8.8192311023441,43.9896776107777,55.1568476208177));
#2519=CARTESIAN_POINT('',(-8.32546122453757,44.5941084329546,55.022829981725));
#2520=CARTESIAN_POINT('',(-7.84173970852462,45.2054104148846,54.8836118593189));
#2521=B_SPLINE_CURVE_WITH_KNOTS('',3,(#2489,#2490,#2491,#2492,#2493,#2494,#2495,#2496,#2497,
#2498,#2499,#2500,#2501,#2502,#2503,#2504,#2505,#2506,#2507,#2508,#2509,#2510,#2511,#2512,#2513,
#2514,#2515,#2516,#2517,#2518,#2519,#2520),.UNSPECIFIED.,.F.,.F.,(4,2,2,2,2,2,2,2,2,2,2,2,2,2,2,
4),(0.,2.84406460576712,5.68864359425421,8.53664098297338,11.3844636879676,14.147730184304,
16.9110313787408,19.6723469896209,22.4335598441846,24.7505478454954,27.0674722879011,
29.3852773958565,31.7030949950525,36.4572920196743,38.8328493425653,41.2081740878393),.UNSPECIFIED.);
#2522=CARTESIAN_POINT('',(-7.84189796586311,45.2052104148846,54.8836574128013));
#2523=VERTEX_POINT('',#2522);
#2524=EDGE_CURVE('E1277',#2465,#2523,#2521,.T.);
#2525=ORIENTED_EDGE('',*,*,#2524,.T.);
#2526=DIRECTION('',(0.,0.,1.));
#2527=VECTOR('',#2526,1.);
#2528=CARTESIAN_POINT('',(-7.84189796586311,45.2052104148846,0.));
#2529=LINE('',#2528,#2527);
#2530=EDGE_CURVE('E296',#1237,#2523,#2529,.T.);
#2531=ORIENTED_EDGE('',*,*,#2530,.F.);
#2532=ORIENTED_EDGE('',*,*,#1238,.T.);
#2533=ORIENTED_EDGE('',*,*,#2472,.T.);
#2534=EDGE_LOOP('',(#2525,#2531,#2532,#2533));
#2535=FACE_BOUND('',#2534,.T.);
#2536=ADVANCED_FACE('F312',(#2535),#2488,.F.);
#2537=CARTESIAN_POINT('',(4.19875832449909,48.0758155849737,54.2463482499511));
#2538=VERTEX_POINT('',#2537);
#2539=CARTESIAN_POINT('',(-4.19875832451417,48.0758155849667,54.2463482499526));
#2540=VERTEX_POINT('',#2539);
#2541=EDGE_CURVE('E647',#2538,#2540,#1752,.T.);
#2542=ORIENTED_EDGE('',*,*,#2541,.F.);
#2543=CARTESIAN_POINT('',(4.20075725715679,48.0748905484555,54.246548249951));
#2544=CARTESIAN_POINT('',(4.12455933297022,48.1101627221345,54.2389284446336));
#2545=CARTESIAN_POINT('',(4.04801924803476,48.1444274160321,54.2301927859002));
#2546=CARTESIAN_POINT('',(3.89432743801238,48.2109295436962,54.2107288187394));
#2547=CARTESIAN_POINT('',(3.81717580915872,48.2431672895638,54.2000008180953));
#2548=CARTESIAN_POINT('',(3.58500992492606,48.3367839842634,54.1652025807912));
#2549=CARTESIAN_POINT('',(3.42915381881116,48.3951268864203,54.1385042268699));
#2550=CARTESIAN_POINT('',(3.1158249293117,48.5036363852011,54.0796296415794));
#2551=CARTESIAN_POINT('',(2.95835366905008,48.5538100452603,54.0474581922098));
#2552=CARTESIAN_POINT('',(2.6419793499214,48.6460928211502,53.9787849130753));
#2553=CARTESIAN_POINT('',(2.48307594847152,48.6881999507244,53.9422820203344));
#2554=CARTESIAN_POINT('',(1.94396263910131,48.816993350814,53.8132579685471));
#2555=CARTESIAN_POINT('',(1.56102126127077,48.8849915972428,53.7129592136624));
#2556=CARTESIAN_POINT('',(0.792485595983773,48.9760508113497,53.5039341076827));
#2557=CARTESIAN_POINT('',(0.406893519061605,48.999145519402,53.3952141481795));
#2558=CARTESIAN_POINT('',(0.0143837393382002,48.9999922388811,53.2844803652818));
#2559=CARTESIAN_POINT('',(0.00719181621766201,48.9999999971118,53.2824513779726));
#2560=CARTESIAN_POINT('',(0.,49.0000000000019,53.280422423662));
#2561=B_SPLINE_CURVE_WITH_KNOTS('',3,(#2543,#2544,#2545,#2546,#2547,#2548,#2549,#2550,#2551,
#2552,#2553,#2554,#2555,#2556,#2557,#2558,#2559,#2560),.UNSPECIFIED.,.F.,.F.,(4,2,2,2,2,2,2,2,
4),(0.,0.252899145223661,0.505759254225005,1.01104586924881,1.51589324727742,2.02086477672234,
3.22282684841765,4.42388542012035,4.44630337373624),.UNSPECIFIED.);
#2562=CARTESIAN_POINT('',(0.,49.,53.280422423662));
#2563=VERTEX_POINT('',#2562);
#2564=EDGE_CURVE('E482',#2538,#2563,#2561,.T.);
#2565=ORIENTED_EDGE('',*,*,#2564,.T.);
#2566=CARTESIAN_POINT('',(0.,49.0000000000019,53.280422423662));
#2567=CARTESIAN_POINT('',(-0.00719183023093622,48.9999999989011,53.282451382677));
#2568=CARTESIAN_POINT('',(-0.0143837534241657,48.9999922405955,53.2844803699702));
#2569=CARTESIAN_POINT('',(-0.344059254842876,48.9992809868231,53.3774874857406));
#2570=CARTESIAN_POINT('',(-0.666706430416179,48.9829874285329,53.4684668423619));
#2571=CARTESIAN_POINT('',(-1.31048788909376,48.9190401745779,53.6455062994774));
#2572=CARTESIAN_POINT('',(-1.63162084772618,48.8713628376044,53.7315626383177));
#2573=CARTESIAN_POINT('',(-2.14213486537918,48.7698139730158,53.8606421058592));
#2574=CARTESIAN_POINT('',(-2.33270437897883,48.7260948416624,53.9070824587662));
#2575=CARTESIAN_POINT('',(-2.71206833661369,48.6272063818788,53.9946488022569));
#2576=CARTESIAN_POINT('',(-2.9008631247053,48.5720393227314,54.0357758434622));
#2577=CARTESIAN_POINT('',(-3.27659725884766,48.4500263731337,54.1110036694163));
#2578=CARTESIAN_POINT('',(-3.46353154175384,48.3831547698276,54.145088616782));
#2579=CARTESIAN_POINT('',(-3.74172601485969,48.2741265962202,54.1890783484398));
#2580=CARTESIAN_POINT('',(-3.83413878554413,48.2363077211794,54.2025573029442));
#2581=CARTESIAN_POINT('',(-4.01811539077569,48.1577702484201,54.2267365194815));
#2582=CARTESIAN_POINT('',(-4.10967902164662,48.1170509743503,54.2374361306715));
#2583=CARTESIAN_POINT('',(-4.20075725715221,48.0748905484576,54.2465482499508));
#2584=B_SPLINE_CURVE_WITH_KNOTS('',3,(#2566,#2567,#2568,#2569,#2570,#2571,#2572,#2573,#2574,
#2575,#2576,#2577,#2578,#2579,#2580,#2581,#2582,#2583),.UNSPECIFIED.,.F.,.F.,(4,2,2,2,2,2,2,2,
4),(0.,0.0224179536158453,1.0276203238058,2.03358077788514,2.6361066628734,3.23851322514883,
3.84226017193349,4.14445886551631,4.44672826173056),.UNSPECIFIED.);
#2585=EDGE_CURVE('E495',#2563,#2540,#2584,.T.);
#2586=ORIENTED_EDGE('',*,*,#2585,.T.);
#2587=EDGE_LOOP('',(#2542,#2565,#2586));
#2588=FACE_BOUND('',#2587,.T.);
#2589=ADVANCED_FACE('F455',(#2588),#1699,.T.);
#2590=CARTESIAN_POINT('',(0.,39.,0.));
#2591=DIRECTION('',(0.,0.,1.));
#2592=DIRECTION('',(1.,0.,0.));
#2593=AXIS2_PLACEMENT_3D('',#2590,#2591,#2592);
#2594=CYLINDRICAL_SURFACE('',#2593,10.);
#2595=ORIENTED_EDGE('',*,*,#2585,.F.);
#2596=ORIENTED_EDGE('',*,*,#2564,.F.);
#2597=CARTESIAN_POINT('',(7.98042026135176,45.0260179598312,54.9245394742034));
#2598=CARTESIAN_POINT('',(7.93499664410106,45.0861758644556,54.9107917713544));
#2599=CARTESIAN_POINT('',(7.88887123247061,45.1458456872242,54.8971787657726));
#2600=CARTESIAN_POINT('',(7.67012260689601,45.4222998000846,54.8342115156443));
#2601=CARTESIAN_POINT('',(7.48889363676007,45.6327682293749,54.7865725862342));
#2602=CARTESIAN_POINT('',(7.10898058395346,46.0384448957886,54.6952333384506));
#2603=CARTESIAN_POINT('',(6.91028521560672,46.2336431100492,54.6515356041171));
#2604=CARTESIAN_POINT('',(6.49667642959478,46.6072928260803,54.5682843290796));
#2605=CARTESIAN_POINT('',(6.28175299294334,46.7857338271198,54.528733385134));
#2606=CARTESIAN_POINT('',(5.83735304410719,47.1242400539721,54.4540170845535));
#2607=CARTESIAN_POINT('',(5.60788477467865,47.2843155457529,54.4188492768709));
#2608=CARTESIAN_POINT('',(5.18373662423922,47.5544526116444,54.3597151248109));
#2609=CARTESIAN_POINT('',(4.99142903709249,47.6680760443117,54.3349229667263));
#2610=CARTESIAN_POINT('',(4.59942950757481,47.8822923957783,54.288301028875));
#2611=CARTESIAN_POINT('',(4.39974019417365,47.9828898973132,54.2664702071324));
#2612=CARTESIAN_POINT('',(3.94769192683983,48.1918989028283,54.2212117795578));
#2613=CARTESIAN_POINT('',(3.69366942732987,48.2968978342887,54.198547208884));
#2614=CARTESIAN_POINT('',(3.17739650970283,48.4857657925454,54.1578639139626));
#2615=CARTESIAN_POINT('',(2.91514214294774,48.5696244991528,54.1398474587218));
#2616=CARTESIAN_POINT('',(2.38399951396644,48.7155796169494,54.108537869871));
#2617=CARTESIAN_POINT('',(2.11510314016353,48.7776478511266,54.0952508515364));
#2618=CARTESIAN_POINT('',(1.57303257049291,48.8793523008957,54.0735002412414));
#2619=CARTESIAN_POINT('',(1.29986026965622,48.9189981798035,54.0650345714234));
#2620=CARTESIAN_POINT('',(0.73709277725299,48.9770067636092,54.0526521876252));
#2621=CARTESIAN_POINT('',(0.447369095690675,48.9941841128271,54.0489888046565));
#2622=CARTESIAN_POINT('',(-0.131641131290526,49.0033236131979,54.0470415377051));
#2623=CARTESIAN_POINT('',(-0.420926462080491,48.9953596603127,54.048741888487));
#2624=CARTESIAN_POINT('',(-0.709274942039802,48.9748147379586,54.0531216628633));
#2625=B_SPLINE_CURVE_WITH_KNOTS('',3,(#2597,#2598,#2599,#2600,#2601,#2602,#2603,#2604,#2605,
#2606,#2607,#2608,#2609,#2610,#2611,#2612,#2613,#2614,#2615,#2616,#2617,#2618,#2619,#2620,#2621,
#2622,#2623,#2624),.UNSPECIFIED.,.F.,.F.,(4,2,2,2,2,2,2,2,2,2,2,2,2,4),(0.,0.22989159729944,
1.07420700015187,1.9190720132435,2.76446296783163,3.60937903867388,4.28309344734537,
4.95657018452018,5.78297349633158,6.60977946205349,7.43765065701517,8.26516479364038,
9.13477740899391,10.0018364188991),.UNSPECIFIED.);
#2626=EDGE_CURVE('E488',#1674,#2538,#2625,.T.);
#2627=ORIENTED_EDGE('',*,*,#2626,.F.);
#2628=ORIENTED_EDGE('',*,*,#1690,.F.);
#2629=ORIENTED_EDGE('',*,*,#1289,.F.);
#2630=ORIENTED_EDGE('',*,*,#1124,.F.);
#2631=ORIENTED_EDGE('',*,*,#1103,.F.);
#2632=ORIENTED_EDGE('',*,*,#1269,.F.);
#2633=ORIENTED_EDGE('',*,*,#2530,.T.);
#2634=CARTESIAN_POINT('',(-4.19676130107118,48.0767392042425,54.2461482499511));
#2635=CARTESIAN_POINT('',(-4.45388260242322,47.9578941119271,54.2718846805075));
#2636=CARTESIAN_POINT('',(-4.70571350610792,47.8281603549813,54.3000518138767));
#2637=CARTESIAN_POINT('',(-5.19714055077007,47.5480728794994,54.3610988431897));
#2638=CARTESIAN_POINT('',(-5.43673294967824,47.3977129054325,54.3939801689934));
#2639=CARTESIAN_POINT('',(-5.89737309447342,47.0806992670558,54.4636112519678));
#2640=CARTESIAN_POINT('',(-6.11868986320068,46.9144169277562,54.500273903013));
#2641=CARTESIAN_POINT('',(-6.54625857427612,46.5645714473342,54.5777842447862));
#2642=CARTESIAN_POINT('',(-6.75251797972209,46.3810169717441,54.6186298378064));
#2643=CARTESIAN_POINT('',(-7.10954794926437,46.0358513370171,54.6958514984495));
#2644=CARTESIAN_POINT('',(-7.26322749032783,45.8770752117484,54.7315149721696));
#2645=CARTESIAN_POINT('',(-7.56066115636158,45.548733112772,54.8056059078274));
#2646=CARTESIAN_POINT('',(-7.70432715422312,45.3790917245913,54.8440530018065));
#2647=CARTESIAN_POINT('',(-7.84205672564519,45.2050097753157,54.8837031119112));
#2648=B_SPLINE_CURVE_WITH_KNOTS('',3,(#2634,#2635,#2636,#2637,#2638,#2639,#2640,#2641,#2642,
#2643,#2644,#2645,#2646,#2647),.UNSPECIFIED.,.F.,.F.,(4,2,2,2,2,2,4),(0.,0.852995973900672,
1.70625121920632,2.54300585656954,3.37934290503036,4.05035350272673,4.72667188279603),.UNSPECIFIED.);
#2649=EDGE_CURVE('E501',#2540,#2523,#2648,.T.);
#2650=ORIENTED_EDGE('',*,*,#2649,.F.);
#2651=EDGE_LOOP('',(#2595,#2596,#2627,#2628,#2629,#2630,#2631,#2632,#2633,#2650));
#2652=FACE_BOUND('',#2651,.T.);
#2653=ADVANCED_FACE('F452',(#2652),#2594,.T.);
#2654=CARTESIAN_POINT('',(0.,0.,58.));
#2655=DIRECTION('',(0.,0.,-1.));
#2656=DIRECTION('',(-1.,0.,0.));
#2657=AXIS2_PLACEMENT_3D('',#2654,#2655,#2656);
#2658=CONICAL_SURFACE('',#2657,34.25,1.30899693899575);
#2659=ORIENTED_EDGE('',*,*,#2626,.T.);
#2660=ORIENTED_EDGE('',*,*,#2541,.T.);
#2661=ORIENTED_EDGE('',*,*,#2649,.T.);
#2662=ORIENTED_EDGE('',*,*,#2524,.F.);
#2663=ORIENTED_EDGE('',*,*,#2466,.T.);
#2664=ORIENTED_EDGE('',*,*,#2389,.T.);
#2665=ORIENTED_EDGE('',*,*,#2479,.T.);
#2666=ORIENTED_EDGE('',*,*,#2296,.F.);
#2667=ORIENTED_EDGE('',*,*,#2238,.T.);
#2668=ORIENTED_EDGE('',*,*,#2169,.T.);
#2669=ORIENTED_EDGE('',*,*,#2251,.T.);
#2670=ORIENTED_EDGE('',*,*,#2074,.F.);
#2671=ORIENTED_EDGE('',*,*,#2016,.T.);
#2672=ORIENTED_EDGE('',*,*,#1947,.T.);
#2673=ORIENTED_EDGE('',*,*,#2029,.T.);
#2674=ORIENTED_EDGE('',*,*,#1886,.F.);
#2675=ORIENTED_EDGE('',*,*,#1828,.T.);
#2676=ORIENTED_EDGE('',*,*,#1753,.T.);
#2677=ORIENTED_EDGE('',*,*,#1841,.T.);
#2678=ORIENTED_EDGE('',*,*,#1677,.F.);
#2679=EDGE_LOOP('',(#2659,#2660,#2661,#2662,#2663,#2664,#2665,#2666,#2667,#2668,#2669,#2670,
#2671,#2672,#2673,#2674,#2675,#2676,#2677,#2678));
#2680=FACE_BOUND('',#2679,.T.);
#2681=CARTESIAN_POINT('',(0.,0.,58.));
#2682=DIRECTION('',(0.,0.,1.));
#2683=DIRECTION('',(1.,0.,0.));
#2684=AXIS2_PLACEMENT_3D('',#2681,#2682,#2683);
#2685=CIRCLE('',#2684,34.25);
#2686=CARTESIAN_POINT('',(34.25,0.,58.));
#2687=VERTEX_POINT('',#2686);
#2688=EDGE_CURVE('E650',#2687,#2687,#2685,.T.);
#2689=ORIENTED_EDGE('',*,*,#2688,.F.);
#2690=EDGE_LOOP('',(#2689));
#2691=FACE_BOUND('',#2690,.T.);
#2692=ADVANCED_FACE('F338',(#2680,#2691),#2658,.T.);
#2693=CARTESIAN_POINT('',(0.,0.,58.));
#2694=DIRECTION('',(0.,0.,1.));
#2695=DIRECTION('',(1.,0.,0.));
#2696=AXIS2_PLACEMENT_3D('',#2693,#2694,#2695);
#2697=CYLINDRICAL_SURFACE('',#2696,34.25);
#2698=ORIENTED_EDGE('',*,*,#31,.F.);
#2699=EDGE_LOOP('',(#2698));
#2700=FACE_BOUND('',#2699,.T.);
#2701=ORIENTED_EDGE('',*,*,#2688,.T.);
#2702=EDGE_LOOP('',(#2701));
#2703=FACE_BOUND('',#2702,.T.);
#2704=ADVANCED_FACE('F980',(#2700,#2703),#2697,.F.);
#2705=CLOSED_SHELL('',(#46,#66,#86,#95,#112,#132,#149,#249,#305,#328,#359,#383,#407,#431,#455,
#472,#492,#517,#537,#557,#577,#666,#686,#709,#729,#749,#769,#789,#884,#969,#1022,#1075,#1128,
#1634,#1694,#1757,#1845,#1898,#1951,#2033,#2086,#2173,#2255,#2308,#2393,#2483,#2536,#2589,#2653,
#2692,#2704));
#2706=MANIFOLD_SOLID_BREP('B1',#2705);
#2707=ADVANCED_BREP_SHAPE_REPRESENTATION('',(#18,#2706),#14);
#2708=SHAPE_DEFINITION_REPRESENTATION(#9,#2707);
ENDSEC;
END-ISO-10303-21;
